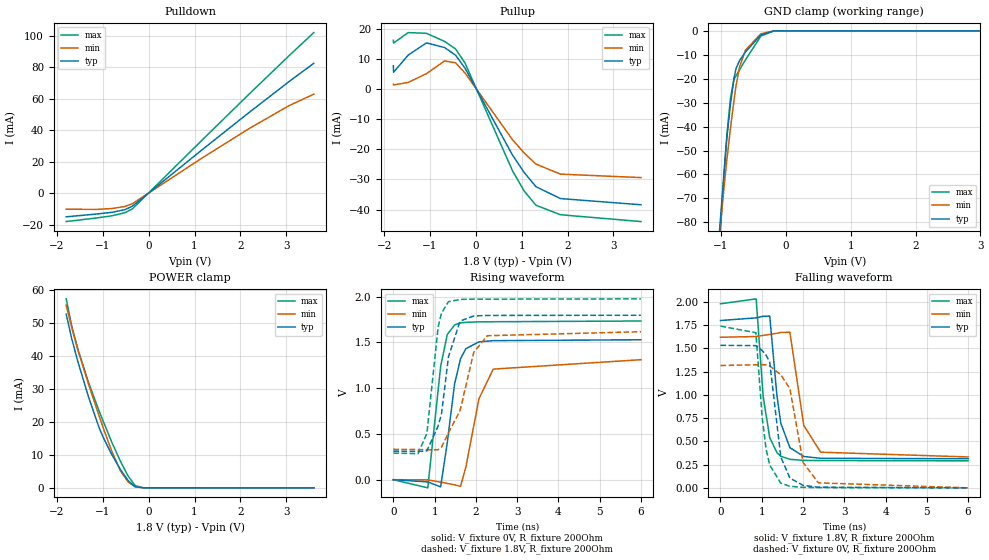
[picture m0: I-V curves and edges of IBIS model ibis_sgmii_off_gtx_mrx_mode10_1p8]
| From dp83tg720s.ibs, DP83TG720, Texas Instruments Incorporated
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|Place the individual model from SIMDE post processing here.
|   ibis_sgmii_off_gtx_mrx_mode10_1p8
[Model]   ibis_sgmii_off_gtx_mrx_mode10_1p8
Model_type   I/O
Polarity   Non-Inverting
Enable   Active-Low
Vinl = 0.54
Vinh = 1.26
Vmeas = 0.9
Vref = 0
Cref = 2pF
Rref = 100000
|   typ   min   max
C_comp   3.8pF   3.76pF   4.1pF
[Voltage Range]   1.8   1.62   1.98
[Temperature Range]   27   150   -40
[Pullup Reference]   1.8   1.62   1.98
[Pulldown Reference]   -0   -0   -0
[Power Clamp Reference]   1.8   1.62   1.98
[GND Clamp Reference]   0   0   0
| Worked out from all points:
|   slope of the pulldown table from 0 to 0.27 V, typ, clamps not added: 42.1 ohm
|   slope of the pullup table from 0 to 0.27 V, typ, clamps not added: 34.5 ohm
|   GND clamp passes 1 mA (typ) near -0.34 V on its own axis
|   POWER clamp passes 1 mA (typ) near -0.37 V on its own axis
|   falling waveform, V_fixture 1.8V, R_fixture 200Ohm: 20-80 % time 226ps typ, 271ps min, 204ps max; typ from 1.8 V to 0.313 V
|   rising waveform, V_fixture 0V, R_fixture 200Ohm: 20-80 % time 281ps typ, 381ps min, 236ps max; typ from 0 V to 1.53 V
|   rising waveform, V_fixture 1.8V, R_fixture 200Ohm: 20-80 % time 283ps typ, 526ps min, 217ps max; typ from 0.313 V to 1.8 V
|   falling waveform, V_fixture 0V, R_fixture 200Ohm: 20-80 % time 251ps typ, 323ps min, 214ps max; typ from 1.53 V to 0 V
[Pulldown]
|   Voltage   I(typ)   I(min)   I(max)
-1.8V     -15.07mA   -10.25mA   -18.09mA
-1.147V   -13.34mA   -10.38mA   -15.84mA
-801mV    -12.23mA   -9.812mA   -14.43mA
-514.8mV  -10.51mA   -8.508mA   -12.42mA
-352.8mV  -8.251mA   -6.687mA   -9.971mA
1.148V    27.12mA    21.97mA    33.18mA
2.191V    51.23mA    40.99mA    62.89mA
3.06V     70.77mA    55.5mA     87.2mA
3.6V      82.43mA    62.79mA    101.9mA
[GND Clamp]
|   Voltage   I(typ)   I(min)   I(max)
-1.8V     -413mA     -361.3mA   -461.4mA
-1.022V   -83.06mA   -84.73mA   -87.93mA
-941.4mV  -54.43mA   -61.85mA   -55.74mA
-909mV    -44.33mA   -53.48mA   -43.2mA
-855mV    -30.54mA   -40.73mA   -28.24mA
-801mV    -19.92mA   -29.1mA    -20.25mA
-768.6mV  -15.71mA   -22.89mA   -18.77mA
-714.6mV  -12.42mA   -15.06mA   -16.29mA
-622.8mV  -8.805mA   -8.036mA   -12.09mA
-385.2mV  -1.682mA   -1.218mA   -2.156mA
-185.4mV  -38.15uA   -31.25uA   -36.48uA
3.6V      0A         0A         0A
[Pullup]
|   Voltage   I(typ)   I(min)   I(max)
-1.8V     7.801mA    1.623mA    16.26mA
-1.795V   5.648mA    1.447mA    15.36mA
-1.476V   11.34mA    2.257mA    18.84mA
-1.076V   15.41mA    5.196mA    18.59mA
-682.2mV  13.86mA    9.417mA    15.91mA
-444.6mV  11.35mA    8.796mA    13.42mA
-239.4mV  7.081mA    5.456mA    8.8mA
797.4mV   -21.84mA   -16.75mA   -27.06mA
1.051V    -27.63mA   -21.17mA   -33.8mA
1.31V     -32.4mA    -24.89mA   -38.57mA
1.845V    -36.36mA   -28.23mA   -41.73mA
3.6V      -38.41mA   -29.38mA   -44mA
[POWER Clamp]
|   Voltage   I(typ)   I(min)   I(max)
-1.8V     52.72mA    55.43mA    57.36mA
-1.681V   45.36mA    48.74mA    49.19mA
-1.546V   38.34mA    41.85mA    42.08mA
-1.319V   27.84mA    31.74mA    32.21mA
-1.082V   18.24mA    21.83mA    23.29mA
-979.2mV  14.91mA    17.7mA     19.75mA
-806.4mV  10.12mA    11.14mA    13.88mA
-612mV    5.438mA    5.014mA    7.891mA
-444.6mV  2.133mA    1.733mA    3.461mA
-293.4mV  326.9uA    317uA      674.2uA
-109.8mV  6.028uA    13.64uA    2.638uA
3.6V      0A         0A         0A
[Ramp]
R_load = 200
|   typ   min   max
dV/dt_r   0.917781/2.79321e-10   0.787416/3.77429e-10   1.04117/2.35852e-10
dV/dt_f   0.891973/2.23452e-10   0.772299/2.67931e-10   1.01309/2.01443e-10
[Falling Waveform]
V_fixture = 1.8V
V_fixture_min = 1.62V
V_fixture_max = 1.98V
R_fixture = 200Ohm
C_fixture = 0F
|   Time   V(typ)   V(min)   V(max)
0s        1.8V       1.62V      1.98V
865.1ps   1.829V     1.628V     2.033V
1.035ns   1.846V     1.64V      981.3mV
1.194ns   1.847V     1.65V      539.7mV
1.368ns   994.6mV    1.663V     379.3mV
1.462ns   695.9mV    1.672V     340.2mV
1.682ns   432.7mV    1.674V     307.1mV
2.019ns   337.1mV    671.1mV    295.7mV
2.428ns   318.2mV    383.7mV    294mV
6ns       313.2mV    332.5mV    291.3mV
[Rising Waveform]
V_fixture = 0V
V_fixture_min = 0V
V_fixture_max = 0V
R_fixture = 200Ohm
C_fixture = 0F
|   Time   V(typ)   V(min)   V(max)
0s        44.44uV    38.89uV    69.25uV
834.6ps   -24.23mV   -1.87mV    -89.05mV
1.146ns   -78.51mV   -26.32mV   1.237V
1.307ns   404mV      -40.44mV   1.587V
1.484ns   1.046V     -56.39mV   1.692V
1.629ns   1.323V     -73.09mV   1.714V
1.757ns   1.432V     137.8mV    1.72V
2.075ns   1.507V     884.7mV    1.726V
2.42ns    1.52V      1.209V     1.727V
6ns       1.53V      1.312V     1.735V
[Rising Waveform]
V_fixture = 1.8V
V_fixture_min = 1.62V
V_fixture_max = 1.98V
R_fixture = 200Ohm
C_fixture = 0F
|   Time   V(typ)   V(min)   V(max)
0s        313.1mV    332.4mV    291.2mV
596.9ps   308.6mV    329.5mV    284.5mV
813.8ps   315.6mV    328.4mV    507.9mV
1.085ns   586.3mV    327.1mV    1.665V
1.166ns   714.4mV    354.1mV    1.821V
1.336ns   1.343V     513mV      1.946V
1.617ns   1.734V     755.3mV    1.971V
1.949ns   1.79V      1.392V     1.974V
2.275ns   1.796V     1.574V     1.974V
6ns       1.798V     1.618V     1.977V
[Falling Waveform]
|Gnd
V_fixture = 0V
V_fixture_min = 0V
V_fixture_max = 0V
R_fixture = 200Ohm
C_fixture = 0F
|   Time   V(typ)   V(min)   V(max)
0s        1.533V     1.316V     1.74V
858.3ps   1.53V      1.324V     1.669V
1.011ns   1.476V     1.325V     757.6mV
1.104ns   1.429V     1.325V     419.4mV
1.194ns   1.352V     1.311V     244.5mV
1.462ns   331.7mV    1.216V     50.62mV
1.682ns   105.6mV    1.068V     17.18mV
2.003ns   26.42mV    272.7mV    5.574mV
2.371ns   7.221mV    53.98mV    3.225mV
6ns       182.1uV    185.6uV    179.8uV
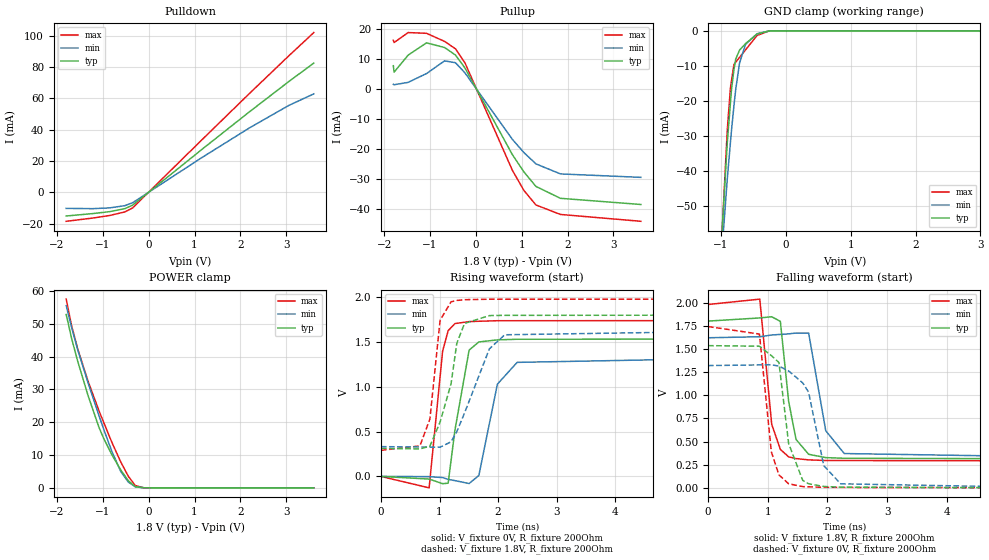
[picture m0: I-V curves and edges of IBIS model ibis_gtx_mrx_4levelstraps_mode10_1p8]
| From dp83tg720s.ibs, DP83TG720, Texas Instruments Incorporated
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|   ibis_gtx_mrx_4levelstraps_mode10_1p8
[Model]   ibis_gtx_mrx_4levelstraps_mode10_1p8
Model_type   I/O
Polarity   Non-Inverting
Enable   Active-Low
Vinl = 0.54
Vinh = 1.26
Vmeas = 0.9
Vref = 0
Cref = 2pF
Rref = 100000
|   typ   min   max
C_comp   2.51pF   2.4pF   2.6pF
[Voltage Range]   1.8   1.62   1.98
[Temperature Range]   27   150   -40
[Pullup Reference]   1.8   1.62   1.98
[Pulldown Reference]   0   0   0
[Power Clamp Reference]   1.8   1.62   1.98
[GND Clamp Reference]   0   0   0
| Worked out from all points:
|   slope of the pulldown table from 0 to 0.27 V, typ, clamps not added: 42.1 ohm
|   slope of the pullup table from 0 to 0.27 V, typ, clamps not added: 34.5 ohm
|   GND clamp passes 1 mA (typ) near -0.45 V on its own axis
|   POWER clamp passes 1 mA (typ) near -0.36 V on its own axis
|   falling waveform, V_fixture 1.8V, R_fixture 200Ohm: 20-80 % time 161ps typ, 197ps min, 154ps max; typ from 1.8 V to 0.313 V
|   rising waveform, V_fixture 0V, R_fixture 200Ohm: 20-80 % time 176ps typ, 255ps min, 141ps max; typ from 0 V to 1.53 V
|   rising waveform, V_fixture 1.8V, R_fixture 200Ohm: 20-80 % time 288ps typ, 460ps min, 151ps max; typ from 0.313 V to 1.8 V
|   falling waveform, V_fixture 0V, R_fixture 200Ohm: 20-80 % time 184ps typ, 254ps min, 161ps max; typ from 1.53 V to 0 V
[Pulldown]
|   Voltage   I(typ)   I(min)   I(max)
-1.8V     -15.11mA   -10.25mA   -18.49mA
-1.222V   -13.57mA   -10.43mA   -16.42mA
-855mV    -12.34mA   -9.942mA   -14.81mA
-520.2mV  -10.44mA   -8.509mA   -12.5mA
-352.8mV  -8.213mA   -6.658mA   -9.977mA
1.165V    27.5mA     22.27mA    33.64mA
2.191V    51.23mA    40.99mA    62.89mA
3.06V     70.77mA    55.5mA     87.2mA
3.6V      82.43mA    62.79mA    101.9mA
[GND Clamp]
|   Voltage   I(typ)   I(min)   I(max)
-1.8V     -379.6mA   -329.3mA   -423.1mA
-1.017V   -67.63mA   -70.66mA   -69.46mA
-903.6mV  -31.87mA   -42.25mA   -28.2mA
-855mV    -20.54mA   -31.86mA   -16.22mA
-838.8mV  -16.76mA   -28.4mA    -14.23mA
-801mV    -11.03mA   -21.37mA   -9.591mA
-774mV    -8.085mA   -16.75mA   -8.964mA
-714.6mV  -5.501mA   -9.181mA   -7.586mA
-622.8mV  -3.665mA   -3.879mA   -5.456mA
-444.6mV  -924.3uA   -826.8uA   -1.321mA
-255.6mV  -12.26uA   -28.29uA   -12.59uA
3.6V      0A         0A         0A
[Pullup]
|   Voltage   I(typ)   I(min)   I(max)
-1.8V     7.801mA    1.623mA    16.26mA
-1.784V   5.659mA    1.465mA    15.52mA
-1.476V   11.34mA    2.257mA    18.84mA
-1.076V   15.41mA    5.196mA    18.59mA
-682.2mV  13.86mA    9.417mA    15.9mA
-444.6mV  11.35mA    8.796mA    13.42mA
-239.4mV  7.081mA    5.456mA    8.8mA
797.4mV   -21.84mA   -16.75mA   -27.06mA
1.051V    -27.63mA   -21.17mA   -33.8mA
1.31V     -32.4mA    -24.89mA   -38.57mA
1.845V    -36.36mA   -28.23mA   -41.73mA
3.6V      -38.41mA   -29.38mA   -44.01mA
[POWER Clamp]
|   Voltage   I(typ)   I(min)   I(max)
-1.8V     52.83mA    55.52mA    57.51mA
-1.681V   45.46mA    48.83mA    49.33mA
-1.546V   38.43mA    41.93mA    42.21mA
-1.319V   27.92mA    31.81mA    32.31mA
-1.082V   18.31mA    21.88mA    23.38mA
-979.2mV  14.97mA    17.75mA    19.83mA
-806.4mV  10.17mA    11.18mA    13.94mA
-612mV    5.477mA    5.044mA    7.945mA
-444.6mV  2.163mA    1.755mA    3.504mA
-293.4mV  350.1uA    334.1uA    708uA
-109.8mV  25.24uA    27.21uA    30.53uA
3.6V      0A         0A         0A
[Ramp]
R_load = 200
|   typ   min   max
dV/dt_r   0.919818/1.76122e-10   0.790484/2.52767e-10   1.04328/1.40855e-10
dV/dt_f   0.891938/1.59769e-10   0.772285/1.94589e-10   1.01304/1.51539e-10
[Falling Waveform]
V_fixture = 1.8V
V_fixture_min = 1.62V
V_fixture_max = 1.98V
R_fixture = 200Ohm
C_fixture = 0F
|   Time   V(typ)   V(min)   V(max)
0s        1.8V       1.62V      1.979V
866.5ps   1.834V     1.631V     2.037V
1.066ns   1.847V     1.65V      686.5mV
1.211ns   1.797V     1.656V     415.5mV
1.35ns    932.9mV    1.662V     334.5mV
1.474ns   522.4mV    1.671V     315.9mV
1.685ns   362.6mV    1.671V     302.1mV
1.972ns   326.3mV    616.3mV    295.4mV
2.282ns   319.4mV    370.4mV    295.1mV
6ns       313mV      332.4mV    291mV
[Rising Waveform]
V_fixture = 0V
V_fixture_min = 0V
V_fixture_max = 0V
R_fixture = 200Ohm
C_fixture = 0F
|   Time   V(typ)   V(min)   V(max)
0s        92.9uV     209.8uV    55.31uV
823ps     -29.62mV   -2.618mV   -127.8mV
1.053ns   -81.1mV    -13.01mV   1.397V
1.148ns   -75.68mV   -33.13mV   1.627V
1.263ns   514.4mV    -46.94mV   1.706V
1.506ns   1.41V      -79.53mV   1.728V
1.672ns   1.501V     10.55mV    1.732V
1.989ns   1.524V     1.03V      1.738V
2.326ns   1.531V     1.273V     1.738V
6ns       1.533V     1.318V     1.739V
[Rising Waveform]
V_fixture = 1.8V
V_fixture_min = 1.62V
V_fixture_max = 1.98V
R_fixture = 200Ohm
C_fixture = 0F
|   Time   V(typ)   V(min)   V(max)
0s        313mV      332.4mV    291mV
665.3ps   306.6mV    328.3mV    341mV
836.2ps   337.7mV    327.3mV    641.3mV
1.01ns    606.7mV    326.2mV    1.742V
1.197ns   1.033V     386.1mV    1.949V
1.296ns   1.487V     500.2mV    1.964V
1.428ns   1.708V     707.8mV    1.973V
1.851ns   1.795V     1.423V     1.978V
2.114ns   1.798V     1.581V     1.978V
6ns       1.8V       1.62V      1.979V
[Falling Waveform]
|Gnd
V_fixture = 0V
V_fixture_min = 0V
V_fixture_max = 0V
R_fixture = 200Ohm
C_fixture = 0F
|   Time   V(typ)   V(min)   V(max)
0s        1.535V     1.32V      1.741V
860.6ps   1.529V     1.327V     1.66V
1.06ns    1.428V     1.329V     389.4mV
1.187ns   1.353V     1.314V     140.3mV
1.35ns    478.4mV    1.262V     43.65mV
1.586ns   80.76mV    1.133V     13.6mV
1.684ns   44.33mV    1.033V     11.38mV
1.939ns   14.94mV    239.6mV    5.603mV
2.222ns   7.432mV    43.74mV    4.695mV
6ns       91.91uV    209.8uV    54.4uV
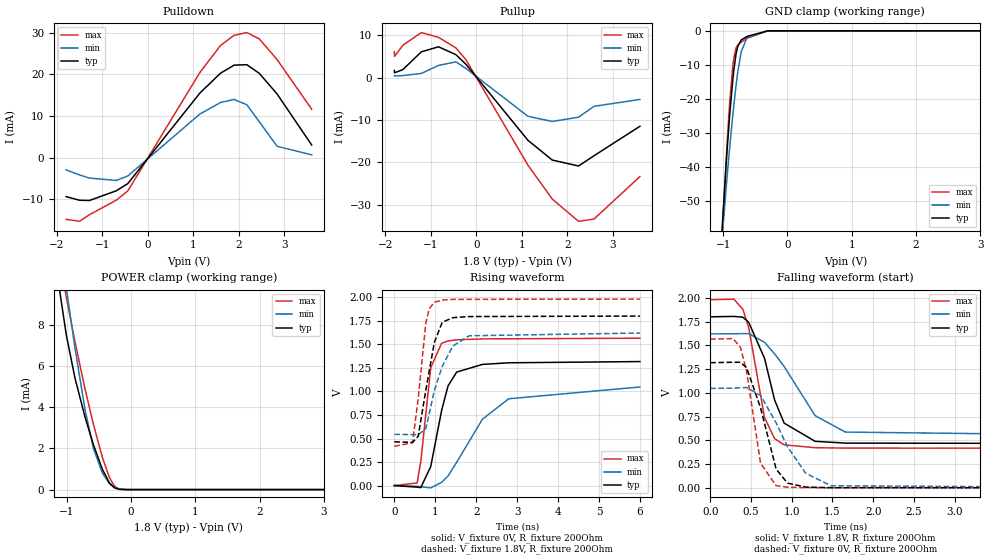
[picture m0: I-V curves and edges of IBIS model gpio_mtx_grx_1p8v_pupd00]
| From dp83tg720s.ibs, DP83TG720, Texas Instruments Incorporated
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|   gpio_mtx_grx_1p8v_pupd00
[Model]   gpio_mtx_grx_1p8v_pupd00
Model_type   I/O
Polarity   Non-Inverting
Enable   Active-Low
Vinl = 0.54
Vinh = 1.26
Vmeas = 0.9
Vref = 0
Cref = 2pF
Rref = 100000
|   typ   min   max
C_comp   1.46pF   1.44pF   1.48pF
[Voltage Range]   1.8   1.62   1.98
[Temperature Range]   27   150   -40
[Pullup Reference]   1.8   1.62   1.98
[Pulldown Reference]   0   0   0
[Power Clamp Reference]   1.8   1.62   1.98
[GND Clamp Reference]   0   0   0
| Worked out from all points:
|   slope of the pulldown table from 0 to 0.27 V, typ, clamps not added: 68.8 ohm
|   slope of the pullup table from 0 to 0.27 V, typ, clamps not added: 71.1 ohm
|   GND clamp passes 1 mA (typ) near -0.54 V on its own axis
|   POWER clamp passes 1 mA (typ) near -0.45 V on its own axis
|   falling waveform, V_fixture 1.8V, R_fixture 200Ohm: 20-80 % time 266ps typ, 493ps min, 194ps max; typ from 1.8 V to 0.465 V
|   rising waveform, V_fixture 0V, R_fixture 200Ohm: 20-80 % time 389ps typ, 983ps min, 229ps max; typ from 0 V to 1.32 V
|   rising waveform, V_fixture 1.8V, R_fixture 200Ohm: 20-80 % time 322ps typ, 467ps min, 220ps max; typ from 0.465 V to 1.8 V
|   falling waveform, V_fixture 0V, R_fixture 200Ohm: 20-80 % time 224ps typ, 394ps min, 162ps max; typ from 1.32 V to 0 V
[Pulldown]
|   Voltage   I(typ)   I(min)   I(max)
-1.8V     -9.373mA   -2.955mA   -14.83mA
-1.503V   -10.24mA   -4.167mA   -15.29mA
-1.287V   -10.3mA    -4.916mA   -13.7mA
-698.4mV  -7.972mA   -5.494mA   -10.23mA
-444.6mV  -6.254mA   -4.425mA   -8.011mA
1.143V    15.5mA     10.46mA    20.44mA
1.597V    20.26mA    13.22mA    26.92mA
1.894V    22.18mA    13.95mA    29.34mA
2.174V    22.29mA    12.67mA    30mA
2.45V     20.2mA     8.58mA     28.46mA
2.839V    15.27mA    2.714mA    23.52mA
3.6V      3.022mA    656uA      11.6mA
[GND Clamp]
|   Voltage   I(typ)   I(min)   I(max)
-1.8V     -346.2mA   -302.9mA   -380.3mA
-1.012V   -56.65mA   -60.01mA   -58.31mA
-941.4mV  -35.72mA   -43.38mA   -33.87mA
-898.2mV  -24.6mA    -34.15mA   -20.97mA
-849.6mV  -14.24mA   -24.66mA   -10.21mA
-833.4mV  -11.4mA    -21.73mA   -7.856mA
-801mV    -6.941mA   -16.28mA   -5.124mA
-774mV    -4.614mA   -12.27mA   -4.191mA
-720mV    -2.708mA   -6.198mA   -3.314mA
-628.2mV  -1.639mA   -1.93mA    -2.196mA
-309.6mV  -16.4uA    -21.72uA   -26.01uA
3.6V      0A         0A         0A
[Pullup]
|   Voltage   I(typ)   I(min)   I(max)
-1.8V     1.744mA    480.7uA    6.165mA
-1.795V   1.177mA    422.4uA    5.078mA
-1.611V   1.951mA    521.8uA    7.703mA
-1.206V   6.14mA     1.032mA    10.69mA
-828mV    7.327mA    2.927mA    9.562mA
-444.6mV  5.46mA     3.758mA    7.052mA
-223.2mV  3.171mA    2.189mA    4.237mA
1.138V    -14.78mA   -9.105mA   -20.65mA
1.672V    -19.44mA   -10.32mA   -28.66mA
2.25V     -20.85mA   -9.32mA    -33.92mA
2.59V     -18.43mA   -6.745mA   -33.39mA
3.6V      -11.46mA   -5.119mA   -23.35mA
[POWER Clamp]
|   Voltage   I(typ)   I(min)   I(max)
-1.8V     52.81mA    31.92mA    32.51mA
-1.13V    10.09mA    12.58mA    11.5mA
-1.006V   7.504mA    9.779mA    9.342mA
-871.2mV  5.41mA     6.878mA    7.176mA
-714.6mV  3.521mA    3.876mA    4.882mA
-585mV    2.184mA    2.004mA    3.173mA
-444.6mV  982.3uA    801.8uA    1.557mA
-336.6mV  328.7uA    288.4uA    594.4uA
-255.6mV  81.4uA     92.37uA    159.3uA
-180mV    13.18uA    22.88uA    22.76uA
-66.6mV   360nA      1.566uA    374.7nA
3.6V      0A         0A         0A
[Ramp]
R_load = 200
|   typ   min   max
dV/dt_r   0.789805/3.87903e-10   0.628237/9.78082e-10   0.938914/2.28306e-10
dV/dt_f   0.800806/2.63607e-10   0.645754/4.91884e-10   0.937756/1.9384e-10
[Falling Waveform]
V_fixture = 1.8V
V_fixture_min = 1.62V
V_fixture_max = 1.98V
R_fixture = 200Ohm
C_fixture = 0F
|   Time   V(typ)   V(min)   V(max)
0s        1.8V       1.62V      1.98V
288.8ps   1.804V     1.622V     1.986V
399.5ps   1.796V     1.623V     1.88V
471.8ps   1.742V     1.623V     1.686V
666ps     1.364V     1.532V     740.1mV
790.1ps   924.2mV    1.41V      517.9mV
907ps     681.3mV    1.277V     453.1mV
1.287ns   490mV      760.1mV    422.7mV
1.659ns   471.1mV    587.2mV    418.6mV
6ns       465.2mV    543.4mV    417mV
[Rising Waveform]
V_fixture = 0V
V_fixture_min = 0V
V_fixture_max = 0V
R_fixture = 200Ohm
C_fixture = 0F
|   Time   V(typ)   V(min)   V(max)
0s        267.1uV    157.4uV    423uV
556.9ps   -16.34mV   -7.615mV   27.92mV
646.4ps   -21.28mV   -12.52mV   256.5mV
889.3ps   202.7mV    -23.97mV   1.252V
1.155ns   797.4mV    34.87mV    1.511V
1.312ns   1.059V     101.9mV    1.536V
1.522ns   1.205V     247.3mV    1.548V
2.153ns   1.287V     705.5mV    1.558V
2.795ns   1.304V     922.1mV    1.559V
6ns       1.317V     1.047V     1.565V
[Rising Waveform]
V_fixture = 1.8V
V_fixture_min = 1.62V
V_fixture_max = 1.98V
R_fixture = 200Ohm
C_fixture = 0F
|   Time   V(typ)   V(min)   V(max)
0s        465.2mV    543.4mV    417mV
445.8ps   458.9mV    542.1mV    455.8mV
582.9ps   523.9mV    537.3mV    925.5mV
769.4ps   1.014V     606.6mV    1.727V
851.4ps   1.212V     760.9mV    1.876V
976.4ps   1.519V     1.008V     1.946V
1.17ns    1.734V     1.266V     1.971V
1.428ns   1.783V     1.481V     1.977V
1.829ns   1.795V     1.591V     1.978V
6ns       1.8V       1.62V      1.98V
[Falling Waveform]
|Gnd
V_fixture = 0V
V_fixture_min = 0V
V_fixture_max = 0V
R_fixture = 200Ohm
C_fixture = 0F
|   Time   V(typ)   V(min)   V(max)
0s        1.317V     1.047V     1.565V
279.9ps   1.322V     1.049V     1.571V
369.8ps   1.321V     1.053V     1.48V
445.8ps   1.265V     1.056V     1.227V
617.5ps   841.8mV    973mV      257.9mV
808.4ps   198.1mV    684.3mV    23.38mV
948.6ps   50.01mV    432.6mV    6.809mV
1.171ns   8.353mV    154.3mV    3.273mV
1.482ns   1.941mV    22.36mV    1.599mV
6ns       267.3uV    157.4uV    423.4uV
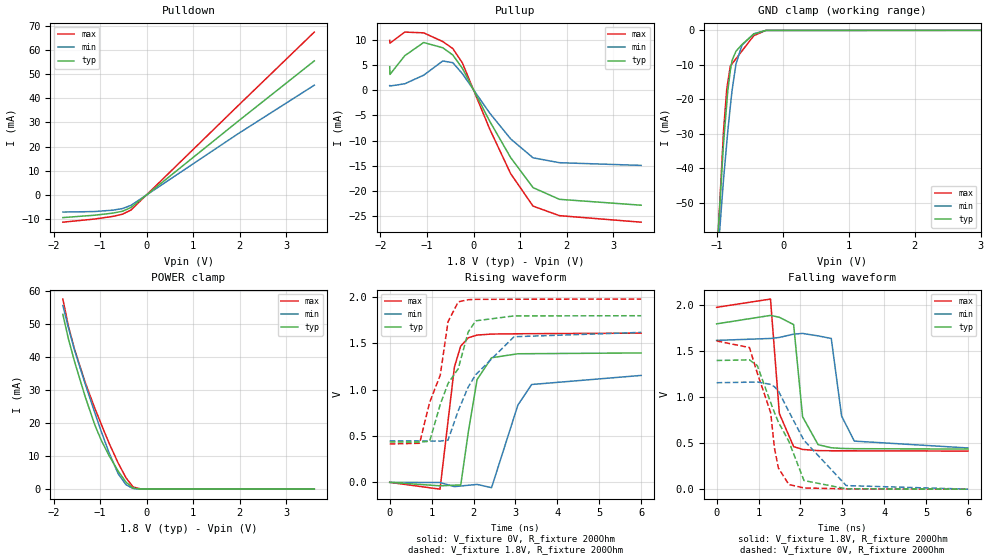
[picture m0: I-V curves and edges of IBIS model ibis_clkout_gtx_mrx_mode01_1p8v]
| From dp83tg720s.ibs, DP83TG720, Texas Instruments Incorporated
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|   ibis_clkout_gtx_mrx_mode01_1p8v
[Model]   ibis_clkout_gtx_mrx_mode01_1p8v
Model_type   I/O
Polarity   Non-Inverting
Enable   Active-Low
Vinl = 0.54
Vinh = 1.26
Vmeas = 0.9
Vref = 0
Cref = 2pF
Rref = 100000
|   typ   min   max
C_comp   3pF   2.97pF   3.04pF
[Voltage Range]   1.8   1.62   1.98
[Temperature Range]   27   150   -40
[Pullup Reference]   1.8   1.62   1.98
[Pulldown Reference]   0   0   0
[Power Clamp Reference]   1.8   1.62   1.98
[GND Clamp Reference]   0   0   0
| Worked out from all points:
|   slope of the pulldown table from 0 to 0.27 V, typ, clamps not added: 64 ohm
|   slope of the pullup table from 0 to 0.27 V, typ, clamps not added: 56 ohm
|   GND clamp passes 1 mA (typ) near -0.44 V on its own axis
|   POWER clamp passes 1 mA (typ) near -0.37 V on its own axis
|   falling waveform, V_fixture 1.8V, R_fixture 200Ohm: 20-80 % time 210ps typ, 247ps min, 182ps max; typ from 1.8 V to 0.437 V
|   rising waveform, V_fixture 0V, R_fixture 200Ohm: 20-80 % time 288ps typ, 439ps min, 244ps max; typ from 0 V to 1.4 V
|   rising waveform, V_fixture 1.8V, R_fixture 200Ohm: 20-80 % time 685ps typ, 1ns min, 487ps max; typ from 0.437 V to 1.8 V
|   falling waveform, V_fixture 0V, R_fixture 200Ohm: 20-80 % time 741ps typ, 1.08ns min, 471ps max; typ from 1.4 V to 0 V
[Pulldown]
|   Voltage   I(typ)   I(min)   I(max)
-1.8V     -9.335mA   -7.039mA   -11.23mA
-1.125V   -8.357mA   -6.843mA   -9.933mA
-730.8mV  -7.492mA   -6.267mA   -8.857mA
-520.2mV  -6.702mA   -5.599mA   -7.923mA
-336.6mV  -5.159mA   -4.278mA   -6.208mA
1.958V    30.4mA     25.25mA    36.82mA
3.6V      55.42mA    45.38mA    67.32mA
[GND Clamp]
|   Voltage   I(typ)   I(min)   I(max)
-1.8V     -382.3mA   -332mA     -425.2mA
-1.017V   -68.67mA   -71.81mA   -70.53mA
-903.6mV  -32.69mA   -43.18mA   -29.12mA
-855mV    -21.28mA   -32.69mA   -17.07mA
-838.8mV  -17.47mA   -29.2mA    -15.06mA
-801mV    -11.68mA   -22.1mA    -10.37mA
-774mV    -8.705mA   -17.42mA   -9.699mA
-714.6mV  -6.046mA   -9.737mA   -8.229mA
-622.8mV  -4.089mA   -4.277mA   -5.956mA
-444.6mV  -1.097mA   -992.9uA   -1.545mA
-261mV    -16.1uA    -40.15uA   -15.49uA
3.6V      0A         0A         0A
[Pullup]
|   Voltage   I(typ)   I(min)   I(max)
-1.8V     4.689mA    939.1uA    9.925mA
-1.795V   3.153mA    845.1uA    9.384mA
-1.476V   6.89mA     1.297mA    11.58mA
-1.071V   9.509mA    3.003mA    11.43mA
-660.6mV  8.461mA    5.831mA    9.698mA
-444.6mV  7.017mA    5.487mA    8.294mA
-239.4mV  4.366mA    3.3mA      5.438mA
343.8mV   -6.101mA   -4.498mA   -7.647mA
797.4mV   -13.4mA    -9.678mA   -16.6mA
1.278V    -19.37mA   -13.44mA   -23.05mA
1.845V    -21.7mA    -14.41mA   -24.95mA
3.6V      -22.87mA   -14.95mA   -26.25mA
[POWER Clamp]
|   Voltage   I(typ)   I(min)   I(max)
-1.8V     53.01mA    55.69mA    57.65mA
-1.681V   45.61mA    48.97mA    49.43mA
-1.546V   38.55mA    42.04mA    42.27mA
-1.319V   27.98mA    31.85mA    32.33mA
-1.114V   19.49mA    23.18mA    24.54mA
-979.2mV  14.96mA    17.66mA    19.84mA
-811.8mV  10.29mA    11.19mA    14.09mA
-612mV    5.452mA    4.68mA     7.912mA
-444.6mV  2.137mA    1.369mA    3.468mA
-293.4mV  327.2uA    184.8uA    675uA
-109.8mV  6.037uA    6.332uA    2.646uA
3.6V      0A         0A         0A
[Ramp]
R_load = 200
|   typ   min   max
dV/dt_r   0.838848/2.87315e-10   0.692873/4.38235e-10   0.966919/2.4247e-10
dV/dt_f   0.817974/2.09252e-10   0.702789/2.45239e-10   0.939142/1.7948e-10
[Falling Waveform]
V_fixture = 1.8V
V_fixture_min = 1.62V
V_fixture_max = 1.98V
R_fixture = 200Ohm
C_fixture = 0F
|   Time   V(typ)   V(min)   V(max)
0s        1.8V       1.62V      1.98V
1.286ns   1.892V     1.641V     2.07V
1.497ns   1.872V     1.652V     823.1mV
1.838ns   1.792V     1.688V     463.4mV
2.052ns   788.5mV    1.696V     432.7mV
2.422ns   484.2mV    1.669V     419.9mV
2.736ns   451.1mV    1.641V     418mV
2.983ns   443.5mV    796mV      417.8mV
3.286ns   440.8mV    523.3mV    417.5mV
6ns       436.7mV    448.6mV    414.8mV
[Rising Waveform]
V_fixture = 0V
V_fixture_min = 0V
V_fixture_max = 0V
R_fixture = 200Ohm
C_fixture = 0F
|   Time   V(typ)   V(min)   V(max)
0s        2.503uV    19.89uV    777.6nV
1.2ns     -37.68mV   -1.647mV   -73.76mV
1.544ns   -30.53mV   -46.12mV   1.247V
1.694ns   -29.97mV   -39.57mV   1.472V
1.877ns   548.3mV    -31.56mV   1.562V
2.085ns   1.111V     -22.49mV   1.591V
2.43ns    1.346V     -57.61mV   1.602V
3.058ns   1.389V     834.7mV    1.605V
3.386ns   1.39V      1.057V     1.606V
6ns       1.398V     1.155V     1.612V
[Rising Waveform]
V_fixture = 1.8V
V_fixture_min = 1.62V
V_fixture_max = 1.98V
R_fixture = 200Ohm
C_fixture = 0F
|   Time   V(typ)   V(min)   V(max)
0s        436.7mV    448.6mV    414.8mV
713.2ps   434.4mV    446.9mV    422.2mV
953.1ps   444.1mV    446.4mV    864.5mV
1.206ns   842.3mV    445.8mV    1.159V
1.391ns   1.068V     456.6mV    1.735V
1.635ns   1.228V     773.8mV    1.95V
1.872ns   1.623V     1.029V     1.973V
2.052ns   1.745V     1.163V     1.977V
2.966ns   1.798V     1.573V     1.978V
6ns       1.8V       1.62V      1.98V
[Falling Waveform]
|Gnd
V_fixture = 0V
V_fixture_min = 0V
V_fixture_max = 0V
R_fixture = 200Ohm
C_fixture = 0F
|   Time   V(typ)   V(min)   V(max)
0s        1.401V     1.159V     1.614V
783.7ps   1.408V     1.165V     1.542V
971.8ps   1.345V     1.167V     1.263V
1.289ns   944.9mV    1.141V     835.5mV
1.381ns   832.9mV    1.115V     446.7mV
1.475ns   730.2mV    1.068V     229.7mV
1.724ns   520.1mV    845.6mV    50.6mV
2.085ns   93.85mV    531.6mV    13.06mV
3.093ns   3.86mV     39.02mV    2.941mV
6ns       2.705uV    19.82uV    1.105uV
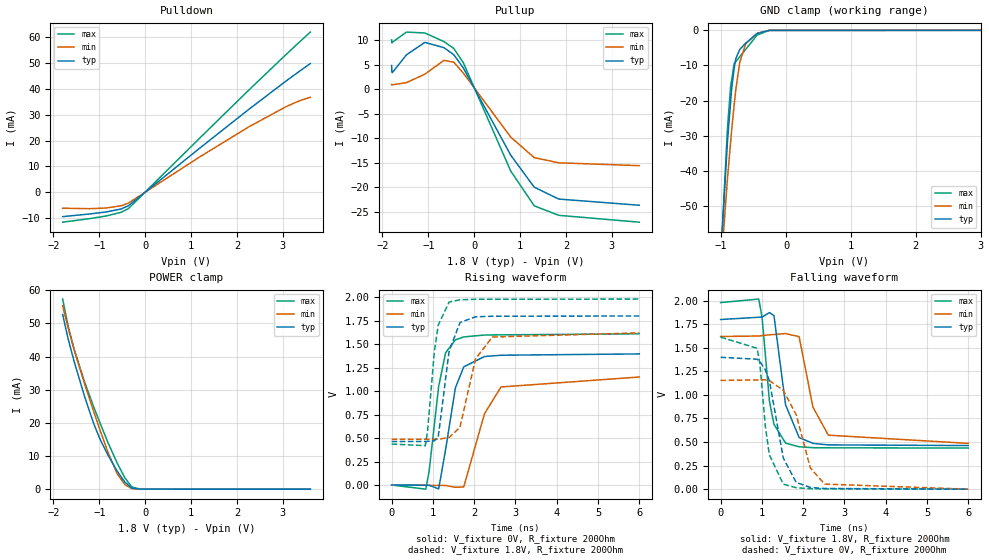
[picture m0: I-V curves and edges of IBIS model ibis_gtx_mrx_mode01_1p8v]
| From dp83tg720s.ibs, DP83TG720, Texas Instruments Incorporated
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| ibis_gtx_mrx_mode01_1p8v
[Model]   ibis_gtx_mrx_mode01_1p8v
Model_type   I/O
Polarity   Non-Inverting
Enable   Active-Low
Vinl = 0.54
Vinh = 1.26
Vmeas = 0.9
Vref = 0.9
Cref = 2pF
Rref = 100000
|   typ   min   max
C_comp   2.91pF   2.88pF   2.94pF
[Voltage Range]   1.8   1.62   1.98
[Temperature Range]   27   150   -40
[Pullup Reference]   1.8   1.62   1.98
[Pulldown Reference]   0   0   0
[Power Clamp Reference]   1.8   1.62   1.98
[GND Clamp Reference]   0   0   0
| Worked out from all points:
|   slope of the pulldown table from 0 to 0.27 V, typ, clamps not added: 69.1 ohm
|   slope of the pullup table from 0 to 0.27 V, typ, clamps not added: 55.9 ohm
|   GND clamp passes 1 mA (typ) near -0.45 V on its own axis
|   POWER clamp passes 1 mA (typ) near -0.37 V on its own axis
|   falling waveform, V_fixture 1.8V, R_fixture 200Ohm: 20-80 % time 268ps typ, 348ps min, 222ps max; typ from 1.8 V to 0.463 V
|   rising waveform, V_fixture 0V, R_fixture 200Ohm: 20-80 % time 320ps typ, 489ps min, 276ps max; typ from 0 V to 1.4 V
|   rising waveform, V_fixture 1.8V, R_fixture 200Ohm: 20-80 % time 251ps typ, 365ps min, 209ps max; typ from 0.463 V to 1.8 V
|   falling waveform, V_fixture 0V, R_fixture 200Ohm: 20-80 % time 342ps typ, 472ps min, 240ps max; typ from 1.4 V to 0 V
[Pulldown]
|   Voltage   I(typ)   I(min)   I(max)
-1.8V     -9.394mA   -6.144mA   -11.54mA
-1.211V   -8.365mA   -6.324mA   -10.16mA
-855mV    -7.603mA   -6.065mA   -9.157mA
-520.2mV  -6.406mA   -5.184mA   -7.692mA
-363.6mV  -5.143mA   -4.14mA    -6.255mA
1.165V    16.73mA    13.42mA    20.53mA
2.261V    32.07mA    25.31mA    39.52mA
3.076V    43.05mA    33.12mA    53.31mA
3.368V    46.82mA    35.39mA    58.12mA
3.6V      49.74mA    36.73mA    61.88mA
[GND Clamp]
|   Voltage   I(typ)   I(min)   I(max)
-1.8V     -380.2mA   -330.5mA   -422.8mA
-1.017V   -67.69mA   -70.97mA   -69.38mA
-903.6mV  -31.87mA   -42.44mA   -28.15mA
-855mV    -20.52mA   -32.01mA   -16.18mA
-838.8mV  -16.74mA   -28.53mA   -14.19mA
-801mV    -11mA      -21.47mA   -9.556mA
-774mV    -8.056mA   -16.83mA   -8.932mA
-714.6mV  -5.478mA   -9.212mA   -7.557mA
-622.8mV  -3.648mA   -3.867mA   -5.433mA
-444.6mV  -916.7uA   -819.7uA   -1.31mA
-261mV    -11.9uA    -29.84uA   -11.43uA
3.6V      0A         0A         0A
[Pullup]
|   Voltage   I(typ)   I(min)   I(max)
-1.8V     4.808mA    957.6uA    10.03mA
-1.795V   3.542mA    861.1uA    9.417mA
-1.784V   3.36mA     871.7uA    9.556mA
-1.476V   6.992mA    1.327mA    11.62mA
-1.076V   9.516mA    3.034mA    11.44mA
-660.6mV  8.453mA    5.857mA    9.69mA
-444.6mV  7.008mA    5.495mA    8.283mA
-239.4mV  4.362mA    3.307mA    5.431mA
797.4mV   -13.47mA   -9.792mA   -16.7mA
1.31V     -19.99mA   -13.97mA   -23.79mA
1.845V    -22.41mA   -15.02mA   -25.72mA
3.6V      -23.67mA   -15.6mA    -27.12mA
[POWER Clamp]
|   Voltage   I(typ)   I(min)   I(max)
-1.8V     52.72mA    55.38mA    57.36mA
-1.681V   45.36mA    48.69mA    49.19mA
-1.546V   38.34mA    41.79mA    42.08mA
-1.319V   27.84mA    31.66mA    32.21mA
-1.114V   19.41mA    23.05mA    24.46mA
-979.2mV  14.91mA    17.57mA    19.78mA
-811.8mV  10.26mA    11.13mA    14.04mA
-612mV    5.438mA    4.663mA    7.891mA
-444.6mV  2.133mA    1.367mA    3.461mA
-293.4mV  326.9uA    184.7uA    674.2uA
-109.8mV  6.036uA    6.315uA    2.646uA
3.6V      0A         0A         0A
[Ramp]
R_load = 200
|   typ   min   max
dV/dt_r   0.837405/3.16973e-10   0.690224/4.8684e-10   0.965873/2.74882e-10
dV/dt_f   0.802303/2.64697e-10   0.680375/3.45056e-10   0.926321/2.21636e-10
[Falling Waveform]
V_fixture = 1.8V
V_fixture_min = 1.62V
V_fixture_max = 1.98V
R_fixture = 200Ohm
C_fixture = 0F
|   Time   V(typ)   V(min)   V(max)
0s        1.8V       1.62V      1.98V
924.6ps   1.824V     1.625V     2.017V
1.005ns   1.826V     1.629V     1.824V
1.184ns   1.874V     1.638V     932.9mV
1.293ns   1.841V     1.641V     689mV
1.575ns   894.4mV    1.651V     488.3mV
1.903ns   548.3mV    1.618V     449.6mV
2.238ns   485.7mV    870.3mV    440mV
2.61ns    469.8mV    573mV      438.8mV
6ns       462.7mV    485.8mV    436.1mV
[Rising Waveform]
V_fixture = 0V
V_fixture_min = 0V
V_fixture_max = 0V
R_fixture = 200Ohm
C_fixture = 0F
|   Time   V(typ)   V(min)   V(max)
0s        2.874uV    15.9uV     1.096uV
828.6ps   -2.215mV   -3.227mV   -44.24mV
907.1ps   -2.425mV   -3.534mV   141.8mV
1.14ns    -41.2mV    -4.445mV   1.051V
1.309ns   380.7mV    -5.107mV   1.409V
1.544ns   1.032V     -24.12mV   1.546V
1.747ns   1.258V     -20.99mV   1.577V
2.249ns   1.368V     757.7mV    1.597V
2.65ns    1.382V     1.044V     1.599V
6ns       1.396V     1.15V      1.61V
[Rising Waveform]
V_fixture = 1.8V
V_fixture_min = 1.62V
V_fixture_max = 1.98V
R_fixture = 200Ohm
C_fixture = 0F
|   Time   V(typ)   V(min)   V(max)
0s        462.7mV    485.8mV    436.1mV
817.5ps   463.4mV    486.8mV    418.9mV
871ps     465.7mV    486.9mV    575.4mV
1.036ns   471.1mV    487.1mV    1.422V
1.129ns   509.8mV    487.2mV    1.703V
1.392ns   1.422V     506.6mV    1.948V
1.656ns   1.73V      614mV      1.972V
2.032ns   1.791V     1.343V     1.978V
2.44ns    1.797V     1.576V     1.978V
6ns       1.8V       1.62V      1.98V
[Falling Waveform]
|Gnd
V_fixture = 0V
V_fixture_min = 0V
V_fixture_max = 0V
R_fixture = 200Ohm
C_fixture = 0F
|   Time   V(typ)   V(min)   V(max)
0s        1.399V     1.154V     1.613V
883.7ps   1.379V     1.159V     1.495V
951.1ps   1.355V     1.159V     1.336V
1.086ns   1.265V     1.16V      660.2mV
1.181ns   1.153V     1.152V     365.4mV
1.519ns   331.2mV    1.049V     53.14mV
1.832ns   71.03mV    789.6mV    15.53mV
2.175ns   18.25mV    224.4mV    4.329mV
2.522ns   7.403mV    53.83mV    3.202mV
6ns       2.542uV    15.89uV    1.068uV
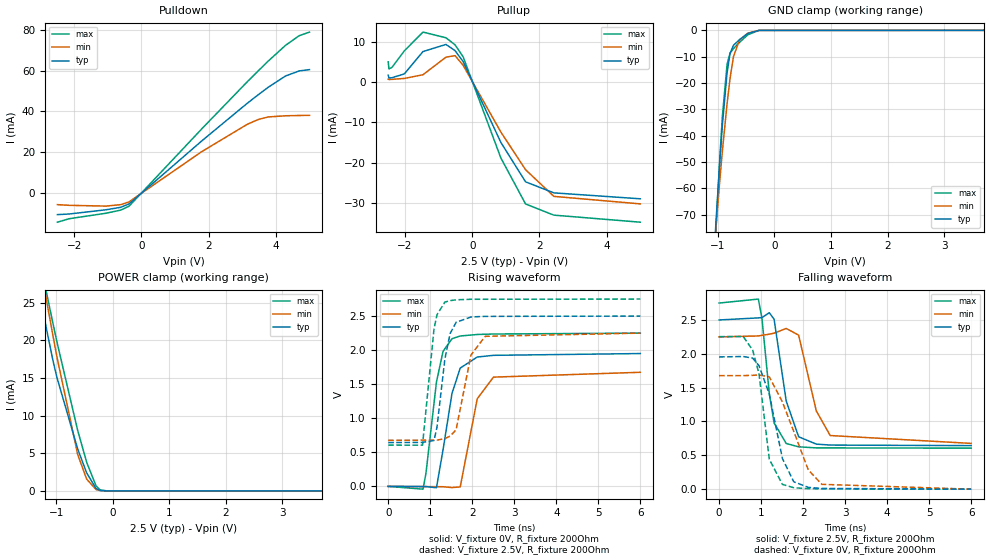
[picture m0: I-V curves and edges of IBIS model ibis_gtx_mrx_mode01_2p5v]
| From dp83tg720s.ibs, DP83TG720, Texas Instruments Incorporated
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| ibis_gtx_mrx_mode01_2p5v
[Model]   ibis_gtx_mrx_mode01_2p5v
Model_type   I/O
Polarity   Non-Inverting
Enable   Active-Low
Vinl = 0.54
Vinh = 1.26
Vmeas = 0.9
Vref = 0.9
Cref = 2pF
Rref = 100000
|   typ   min   max
C_comp   2.89pF   2.86pF   2.93pF
[Voltage Range]   2.5   2.25   2.75
[Temperature Range]   27   150   -40
[Pullup Reference]   2.5   2.25   2.75
[Pulldown Reference]   0   0   0
[Power Clamp Reference]   2.5   2.25   2.75
[GND Clamp Reference]   0   0   0
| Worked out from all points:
|   slope of the pulldown table from 0 to 0.375 V, typ, clamps not added: 69.2 ohm
|   slope of the pullup table from 0 to 0.375 V, typ, clamps not added: 54.5 ohm
|   GND clamp passes 1 mA (typ) near -0.45 V on its own axis
|   POWER clamp passes 1 mA (typ) near -0.37 V on its own axis
|   falling waveform, V_fixture 2.5V, R_fixture 200Ohm: 20-80 % time 278ps typ, 360ps min, 231ps max; typ from 2.5 V to 0.643 V
|   rising waveform, V_fixture 0V, R_fixture 200Ohm: 20-80 % time 325ps typ, 327ps min, 277ps max; typ from 0 V to 1.95 V
|   rising waveform, V_fixture 2.5V, R_fixture 200Ohm: 20-80 % time 232ps typ, 278ps min, 193ps max; typ from 0.643 V to 2.5 V
|   falling waveform, V_fixture 0V, R_fixture 200Ohm: 20-80 % time 423ps typ, 611ps min, 270ps max; typ from 1.95 V to 0 V
[Pulldown]
|   Voltage   I(typ)   I(min)   I(max)
-2.5V     -10.43mA   -5.548mA   -14.13mA
-2.147V   -10.12mA   -5.882mA   -12.43mA
-1.052V   -8.054mA   -6.263mA   -9.745mA
-617.5mV  -6.858mA   -5.55mA    -8.231mA
-370mV    -5.221mA   -4.201mA   -6.338mA
1.798V    25.65mA    20.41mA    31.55mA
3.147V    43.98mA    33.72mA    54.49mA
3.485V    48.3mA     36.14mA    60.02mA
3.777V    51.89mA    37.33mA    64.7mA
4.287V    57.35mA    37.9mA     72.33mA
4.692V    59.82mA    38.04mA    77.04mA
5V        60.47mA    38.12mA    78.82mA
[GND Clamp]
|   Voltage   I(typ)   I(min)   I(max)
-2.5V     -672.4mA   -578.6mA   -749.1mA
-1.097V   -97.01mA   -94.22mA   -103.2mA
-1.03V    -72.28mA   -74.57mA   -74.7mA
-962.5mV  -49.34mA   -56.59mA   -48.07mA
-917.5mV  -35.71mA   -45.65mA   -32.42mA
-835mV    -16.02mA   -27.78mA   -12.86mA
-782.5mV  -8.753mA   -18.2mA    -8.647mA
-722.5mV  -5.688mA   -10.01mA   -6.949mA
-617.5mV  -3.554mA   -3.701mA   -4.596mA
-467.5mV  -1.199mA   -1.052mA   -1.675mA
-272.5mV  -16.77uA   -38.36uA   -18.24uA
5V        0A         0A         0A
[Pullup]
|   Voltage   I(typ)   I(min)   I(max)
-2.5V     1.678mA    684.9uA    4.967mA
-2.478V   944.2uA    591uA      3.207mA
-2.388V   1.038mA    629.8uA    3.61mA
-2.02V    1.986mA    857.1uA    7.704mA
-1.465V   7.527mA    1.782mA    12.35mA
-782.5mV  9.287mA    6.133mA    10.94mA
-512.5mV  7.761mA    6.51mA     9.196mA
-272.5mV  5.053mA    4.138mA    6.248mA
852.5mV   -15.02mA   -12.45mA   -18.88mA
1.587V    -24.78mA   -21.78mA   -30.27mA
2.428V    -27.51mA   -28.38mA   -33.03mA
5V        -28.98mA   -30.24mA   -34.78mA
[POWER Clamp]
|   Voltage   I(typ)   I(min)   I(max)
-2.5V     144.5mA    109.4mA    191.7mA
-1.427V   32.73mA    36.35mA    36.62mA
-1.248V   24.72mA    28.61mA    29.23mA
-1.18V    21.93mA    25.78mA    26.73mA
-1.06V    17.49mA    20.82mA    22.43mA
-985mV    15.08mA    17.8mA     19.8mA
-617.5mV  5.56mA     4.81mA     8.015mA
-460mV    2.396mA    1.576mA    3.822mA
-295mV    328.2uA    185.9uA    693.1uA
-220mV    57.95uA    41.65uA    125.1uA
-92.5mV   988.6nA    1.88uA     1.238uA
5V        0A         0A         0A
[Ramp]
R_load = 200
|   typ   min   max
dV/dt_r   1.16978/3.24103e-10   1.005/3.24301e-10   1.35015/2.76259e-10
dV/dt_f   1.11392/2.75116e-10   0.944118/3.58503e-10   1.28631/2.28808e-10
[Falling Waveform]
V_fixture = 2.5V
V_fixture_min = 2.25V
V_fixture_max = 2.75V
R_fixture = 200Ohm
C_fixture = 0F
|   Time   V(typ)   V(min)   V(max)
0s        2.5V       2.25V      2.75V
935.8ps   2.531V     2.264V     2.809V
1.02ns    2.535V     2.273V     2.53V
1.196ns   2.607V     2.29V      1.413V
1.31ns    2.511V     2.305V     978.6mV
1.599ns   1.301V     2.375V     674.8mV
1.894ns   774.2mV    2.276V     625.8mV
2.315ns   665.7mV    1.156V     609.9mV
2.646ns   651.5mV    792.4mV    609.6mV
6ns       643.4mV    676.2mV    606.1mV
[Rising Waveform]
V_fixture = 0V
V_fixture_min = 0V
V_fixture_max = 0V
R_fixture = 200Ohm
C_fixture = 0F
|   Time   V(typ)   V(min)   V(max)
0s        2.374uV    15.5uV     1.345uV
828.1ps   -2.162mV   -3.221mV   -40.91mV
898.4ps   -2.345mV   -3.496mV   192.5mV
1.148ns   -20.29mV   -4.471mV   1.531V
1.305ns   538mV      -5.084mV   1.983V
1.518ns   1.365V     -17.51mV   2.168V
1.714ns   1.737V     -7.981mV   2.208V
2.119ns   1.899V     1.286V     2.23V
2.506ns   1.924V     1.604V     2.237V
6ns       1.95V      1.675V     2.25V
[Rising Waveform]
V_fixture = 2.5V
V_fixture_min = 2.25V
V_fixture_max = 2.75V
R_fixture = 200Ohm
C_fixture = 0F
|   Time   V(typ)   V(min)   V(max)
0s        643.4mV    676.2mV    606.1mV
815.9ps   645.5mV    678.4mV    604.5mV
1.09ns    674.1mV    679.1mV    2.313V
1.161ns   870.1mV    679.3mV    2.52V
1.348ns   1.868V     701.1mV    2.705V
1.474ns   2.244V     738.4mV    2.727V
1.616ns   2.409V     830.8mV    2.739V
1.97ns    2.487V     1.929V     2.747V
2.308ns   2.496V     2.203V     2.747V
6ns       2.5V       2.25V      2.75V
[Falling Waveform]
|Gnd
V_fixture = 0V
V_fixture_min = 0V
V_fixture_max = 0V
R_fixture = 200Ohm
C_fixture = 0F
|   Time   V(typ)   V(min)   V(max)
0s        1.954V     1.678V     2.254V
576.6ps   1.96V      1.678V     2.255V
802.1ps   1.936V     1.682V     2.052V
951.7ps   1.823V     1.688V     1.703V
1.196ns   1.405V     1.659V     443.1mV
1.507ns   453.5mV    1.29V      70.69mV
1.779ns   109mV      851.1mV    21.44mV
2.124ns   26.4mV     284.7mV    7.113mV
2.446ns   10.67mV    71.22mV    4.021mV
6ns       2.613uV    15.55uV    1.162uV
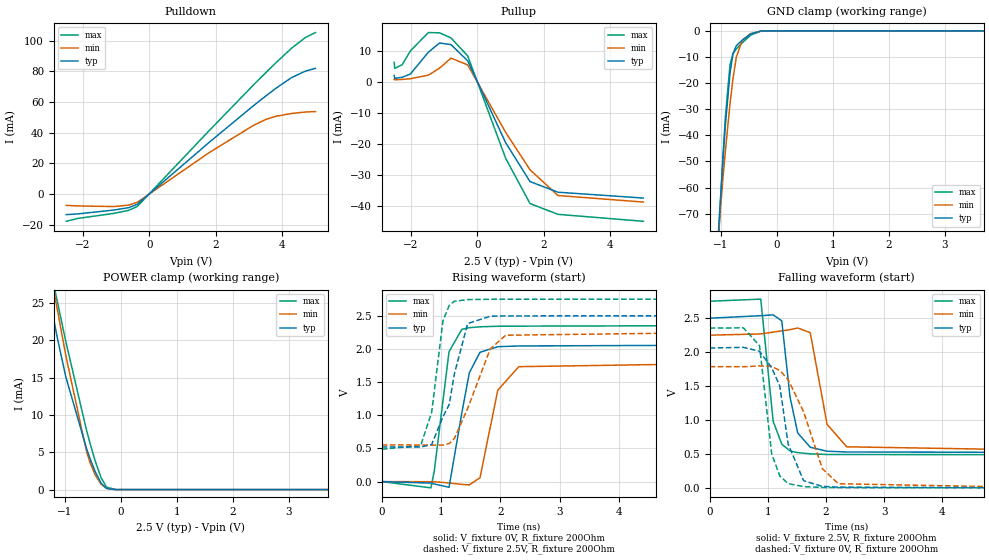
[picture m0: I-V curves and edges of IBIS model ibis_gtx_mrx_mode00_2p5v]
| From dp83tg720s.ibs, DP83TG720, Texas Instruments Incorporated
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| ibis_gtx_mrx_mode00_2p5v
[Model]   ibis_gtx_mrx_mode00_2p5v
Model_type   I/O
Polarity   Non-Inverting
Enable   Active-Low
Vinl = 0.75
Vinh = 1.75
Vmeas = 1.25
Vref = 1.25
Cref = 2pF
Rref = 100000
|   typ   min   max
C_comp   2.91pF   2.88pF   2.94pF
[Voltage Range]   2.5   2.25   2.75
[Temperature Range]   27   150   -40
[Pullup Reference]   2.5   2.25   2.75
[Pulldown Reference]   0   0   0
[Power Clamp Reference]   2.5   2.25   2.75
[GND Clamp Reference]   0   0   0
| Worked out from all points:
|   slope of the pulldown table from 0 to 0.375 V, typ, clamps not added: 52.8 ohm
|   slope of the pullup table from 0 to 0.375 V, typ, clamps not added: 42.1 ohm
|   GND clamp passes 1 mA (typ) near -0.45 V on its own axis
|   POWER clamp passes 1 mA (typ) near -0.37 V on its own axis
|   falling waveform, V_fixture 2.5V, R_fixture 200Ohm: 20-80 % time 178ps typ, 215ps min, 151ps max; typ from 2.5 V to 0.522 V
|   rising waveform, V_fixture 0V, R_fixture 200Ohm: 20-80 % time 231ps typ, 252ps min, 189ps max; typ from 0 V to 2.06 V
|   rising waveform, V_fixture 2.5V, R_fixture 200Ohm: 20-80 % time 317ps typ, 441ps min, 190ps max; typ from 0.522 V to 2.5 V
|   falling waveform, V_fixture 0V, R_fixture 200Ohm: 20-80 % time 263ps typ, 456ps min, 170ps max; typ from 2.06 V to 0 V
[Pulldown]
|   Voltage   I(typ)   I(min)   I(max)
-2.5V     -13.49mA   -7.447mA   -17.85mA
-2.17V    -13.06mA   -7.815mA   -16.03mA
-1.067V   -10.5mA    -8.222mA   -12.67mA
-617.5mV  -8.928mA   -7.264mA   -10.69mA
-362.5mV  -6.716mA   -5.43mA    -8.145mA
1.798V    33.66mA    26.98mA    41.3mA
3.147V    57.88mA    44.96mA    71.47mA
3.515V    64.15mA    48.74mA    79.44mA
3.815V    69.08mA    50.77mA    85.79mA
4.28V     75.97mA    52.55mA    95.16mA
4.692V    80.18mA    53.5mA     102.1mA
5V        82.04mA    53.81mA    105.4mA
[GND Clamp]
|   Voltage   I(typ)   I(min)   I(max)
-2.5V     -672.4mA   -578.6mA   -749.1mA
-1.097V   -97.01mA   -94.22mA   -103.2mA
-1.03V    -72.28mA   -74.57mA   -74.7mA
-962.5mV  -49.34mA   -56.59mA   -48.07mA
-917.5mV  -35.71mA   -45.65mA   -32.42mA
-835mV    -16.02mA   -27.78mA   -12.86mA
-782.5mV  -8.753mA   -18.2mA    -8.647mA
-722.5mV  -5.688mA   -10.01mA   -6.949mA
-617.5mV  -3.554mA   -3.702mA   -4.596mA
-467.5mV  -1.199mA   -1.052mA   -1.675mA
-272.5mV  -16.77uA   -38.63uA   -18.24uA
5V        0A         0A         0A
[Pullup]
|   Voltage   I(typ)   I(min)   I(max)
-2.5V     2.157mA    868.3uA    6.373mA
-2.485V   1.208mA    740.3uA    4.414mA
-2.26V    1.571mA    875.1uA    5.61mA
-2.013V   2.607mA    1.09mA     10.05mA
-1.472V   9.629mA    2.234mA    15.95mA
-1.135V   12.59mA    4.492mA    15.87mA
-790mV    12.07mA    7.725mA    14.22mA
-287.5mV  6.857mA    5.545mA    8.444mA
852.5mV   -19.44mA   -16.14mA   -24.45mA
1.587V    -32mA      -28.2mA    -39.07mA
2.428V    -35.43mA   -36.49mA   -42.55mA
5V        -37.31mA   -38.6mA    -44.79mA
[POWER Clamp]
|   Voltage   I(typ)   I(min)   I(max)
-2.5V     144.5mA    109.4mA    191.7mA
-1.42V    32.38mA    36.09mA    36.29mA
-1.248V   24.72mA    28.69mA    29.23mA
-1.15V    20.76mA    24.63mA    25.64mA
-985mV    15.08mA    17.93mA    19.8mA
-617.5mV  5.56mA     5.156mA    8.015mA
-550mV    4.112mA    3.562mA    6.126mA
-460mV    2.396mA    1.954mA    3.822mA
-355mV    860uA      725.3uA    1.597mA
-257.5mV  148.6uA    170.2uA    327.9uA
-92.5mV   988.6nA    4.315uA    1.238uA
5V        0A         0A         0A
[Ramp]
R_load = 200
|   typ   min   max
dV/dt_r   1.23438/2.30716e-10   1.06981/2.51046e-10   1.41077/1.88997e-10
dV/dt_f   1.18653/1.76194e-10   1.01854/2.12735e-10   1.35689/1.5082e-10
[Falling Waveform]
V_fixture = 2.5V
V_fixture_min = 2.25V
V_fixture_max = 2.75V
R_fixture = 200Ohm
C_fixture = 0F
|   Time   V(typ)   V(min)   V(max)
0s        2.5V       2.25V      2.75V
878.7ps   2.537V     2.268V     2.781V
1.092ns   2.549V     2.295V     984mV
1.24ns    2.462V     2.313V     644.6mV
1.382ns   1.34V      2.331V     544.1mV
1.514ns   809.8mV    2.356V     519.2mV
1.73ns    598mV      2.287V     501.1mV
2.02ns    540.1mV    934.8mV    491.8mV
2.357ns   528.6mV    605.1mV    491.6mV
6ns       522.4mV    552.3mV    488.5mV
[Rising Waveform]
V_fixture = 0V
V_fixture_min = 0V
V_fixture_max = 0V
R_fixture = 200Ohm
C_fixture = 0F
|   Time   V(typ)   V(min)   V(max)
0s        1.909uV    24.69uV    896.8nV
829.1ps   -22.76mV   -2.126mV   -94.4mV
887.2ps   -35.77mV   -2.277mV   168.9mV
1.135ns   -86.04mV   -20.53mV   1.959V
1.352ns   1.042V     -42.15mV   2.296V
1.477ns   1.64V      -49.8mV    2.319V
1.657ns   1.949V     58.92mV    2.333V
1.957ns   2.033V     1.378V     2.341V
2.311ns   2.044V     1.732V     2.343V
6ns       2.057V     1.783V     2.351V
[Rising Waveform]
V_fixture = 2.5V
V_fixture_min = 2.25V
V_fixture_max = 2.75V
R_fixture = 200Ohm
C_fixture = 0F
|   Time   V(typ)   V(min)   V(max)
0s        522.4mV    552.3mV    488.5mV
656.5ps   520.6mV    551.4mV    542.5mV
842ps     558.7mV    551.1mV    1.045V
1.032ns   976.9mV    550.8mV    2.422V
1.138ns   1.161V     573.6mV    2.655V
1.224ns   1.621V     647.5mV    2.718V
1.449ns   2.381V     1.102V     2.743V
1.829ns   2.493V     1.998V     2.748V
2.09ns    2.497V     2.206V     2.748V
6ns       2.5V       2.25V      2.75V
[Falling Waveform]
|Gnd
V_fixture = 0V
V_fixture_min = 0V
V_fixture_max = 0V
R_fixture = 200Ohm
C_fixture = 0F
|   Time   V(typ)   V(min)   V(max)
0s        2.061V     1.786V     2.354V
580.6ps   2.07V      1.785V     2.358V
857.4ps   2.013V     1.796V     2.096V
1.067ns   1.77V      1.79V      500.9mV
1.206ns   1.503V     1.73V      175.4mV
1.35ns    646.3mV    1.596V     62.13mV
1.616ns   105.4mV    1.12V      18.22mV
1.938ns   21.3mV     282.9mV    6.015mV
2.214ns   10.25mV    60.51mV    3.497mV
6ns       1.984uV    24.71uV    983.4nV
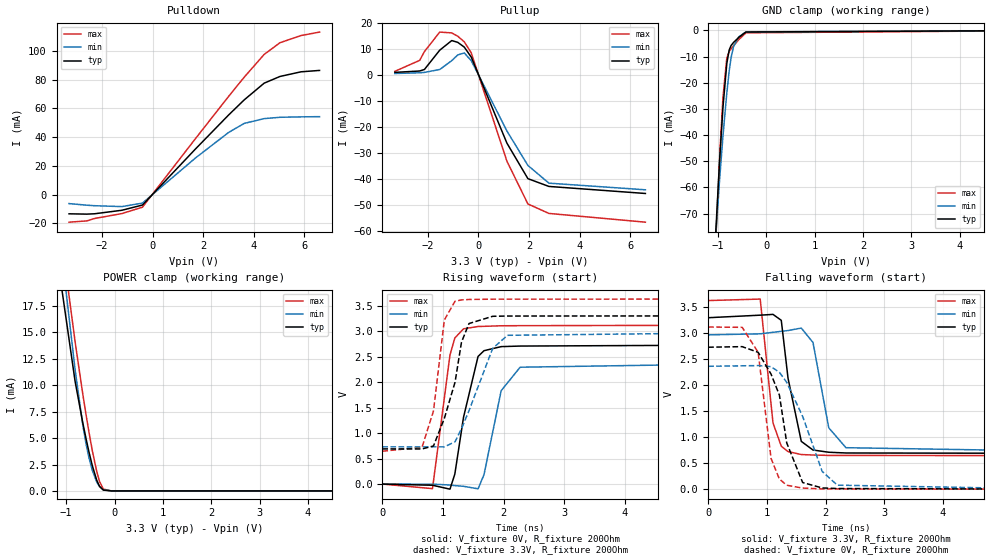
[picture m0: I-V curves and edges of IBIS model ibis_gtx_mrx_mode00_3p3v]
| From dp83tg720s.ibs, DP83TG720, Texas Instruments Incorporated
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| ibis_gtx_mrx_mode00_3p3v
[Model]   ibis_gtx_mrx_mode00_3p3v
Model_type   I/O
Polarity   Non-Inverting
Enable   Active-Low
Vinl = 0.99
Vinh = 2.31
Vmeas = 1.65
Vref = 1.65
Cref = 2pF
Rref = 100000
|   typ   min   max
C_comp   2.9pF   2.93pF   2.87pF
[Voltage Range]   3.3   2.97   3.63
[Temperature Range]   27   150   -40
[Pullup Reference]   3.3   2.97   3.63
[Pulldown Reference]   0   0   0
[Power Clamp Reference]   3.3   2.97   3.63
[GND Clamp Reference]   0   0   0
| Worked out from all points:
|   slope of the pulldown table from 0 to 0.495 V, typ, clamps not added: 52.8 ohm
|   slope of the pullup table from 0 to 0.495 V, typ, clamps not added: 41.1 ohm
|   GND clamp passes 1 mA (typ) near -0.45 V on its own axis
|   POWER clamp passes 1 mA (typ) near -0.37 V on its own axis
|   falling waveform, V_fixture 3.3V, R_fixture 200Ohm: 20-80 % time 180ps typ, 219ps min, 151ps max; typ from 3.3 V to 0.69 V
|   rising waveform, V_fixture 0V, R_fixture 200Ohm: 20-80 % time 228ps typ, 252ps min, 187ps max; typ from 0 V to 2.73 V
|   rising waveform, V_fixture 3.3V, R_fixture 200Ohm: 20-80 % time 308ps typ, 432ps min, 195ps max; typ from 0.69 V to 3.3 V
|   falling waveform, V_fixture 0V, R_fixture 200Ohm: 20-80 % time 316ps typ, 487ps min, 179ps max; typ from 2.73 V to 0 V
[Pulldown]
|   Voltage   I(typ)   I(min)   I(max)
-3.3V     -13.32mA   -6.214mA   -19.15mA
-2.597V   -13.54mA   -7.325mA   -18.24mA
-2.29V    -13.29mA   -7.689mA   -16.56mA
-1.211V   -10.85mA   -8.305mA   -13.15mA
-399.3mV  -7.224mA   -5.844mA   -8.717mA
1.69V     31.67mA    25.43mA    38.85mA
3.006V    55.42mA    43.29mA    68.37mA
3.62V     65.9mA     49.57mA    81.68mA
4.412V    77.59mA    52.92mA    97.6mA
5.036V    82.23mA    53.83mA    105.7mA
5.867V    85.47mA    54.12mA    110.7mA
6.6V      86.43mA    54.28mA    113.1mA
[GND Clamp]
|   Voltage   I(typ)   I(min)   I(max)
-3.3V     -1.011A    -865.8mA   -1.126A
-1.082V   -91.37mA   -89.71mA   -96.69mA
-1.053V   -80.45mA   -81.02mA   -84.12mA
-963.6mV  -49.69mA   -56.87mA   -48.48mA
-894.3mV  -29.4mA    -40.34mA   -25.48mA
-815.1mV  -12.66mA   -23.94mA   -10.6mA
-765.6mV  -7.479mA   -15.54mA   -8.067mA
-726mV    -5.787mA   -10.39mA   -7.032mA
-676.5mV  -4.645mA   -6.247mA   -5.893mA
-567.6mV  -2.701mA   -2.49mA    -3.55mA
-419.1mV  -641.7uA   -597.9uA   -944.7uA
6.6V      0A         0A         0A
[Pullup]
|   Voltage   I(typ)   I(min)   I(max)
-3.3V     1.024mA    596.1uA    1.43mA
-2.32V    1.558mA    868.7uA    5.65mA
-2.132V   2.15mA     1.016mA    9.03mA
-1.528V   9.563mA    2.138mA    16.53mA
-1.053V   13.27mA    5.538mA    16.22mA
-815.1mV  12.58mA    7.751mA    14.93mA
-557.7mV  10.75mA    8.499mA    12.79mA
-280.5mV  6.871mA    5.515mA    8.509mA
1.125V    -26.16mA   -21.49mA   -33.1mA
1.957V    -39.88mA   -34.79mA   -49.62mA
2.788V    -42.87mA   -41.61mA   -53.26mA
6.6V      -45.58mA   -44.16mA   -56.63mA
[POWER Clamp]
|   Voltage   I(typ)   I(min)   I(max)
-3.3V     317.9mA    237mA      400.5mA
-1.181V   21.99mA    25.93mA    26.78mA
-815.1mV  10.35mA    11.45mA    14.1mA
-656.7mV  6.45mA     6.234mA    9.162mA
-587.4mV  4.9mA      4.403mA    7.158mA
-528mV    3.668mA    3.117mA    5.537mA
-458.7mV  2.373mA    1.935mA    3.791mA
-369.6mV  1.032mA    856.8uA    1.866mA
-310.2mV  435.4uA    402.4uA    888uA
-231mV    77.39uA    103.3uA    169.6uA
-62.7mV   288.6nA    1.815uA    282.8nA
6.6V      0A         0A         0A
[Ramp]
R_load = 200
|   typ   min   max
dV/dt_r   1.63673/2.28449e-10   1.41658/2.50163e-10   1.87047/1.86163e-10
dV/dt_f   1.56582/1.78632e-10   1.34358/2.1855e-10   1.79086/1.50296e-10
[Falling Waveform]
V_fixture = 3.3V
V_fixture_min = 2.97V
V_fixture_max = 3.63V
R_fixture = 200Ohm
C_fixture = 0F
|   Time   V(typ)   V(min)   V(max)
0s        3.3V       2.97V      3.63V
886.1ps   3.349V     2.99V      3.659V
1.104ns   3.364V     3.019V     1.274V
1.245ns   3.25V      3.038V     827.6mV
1.36ns    2.135V     3.053V     723.3mV
1.586ns   919.7mV    3.101V     666.4mV
1.785ns   753.6mV    2.824V     657.2mV
2.054ns   710.6mV    1.181V     649.5mV
2.347ns   696.3mV    798.3mV    649.2mV
6ns       690.3mV    730.6mV    645.2mV
[Rising Waveform]
V_fixture = 0V
V_fixture_min = 0V
V_fixture_max = 0V
R_fixture = 200Ohm
C_fixture = 0F
|   Time   V(typ)   V(min)   V(max)
0s        1.97uV     25.02uV    1.138uV
826.9ps   -22.52mV   -1.982mV   -88.84mV
1.115ns   -99.52mV   -17.63mV   2.534V
1.195ns   196mV      -29.74mV   2.866V
1.338ns   1.309V     -42.95mV   3.046V
1.578ns   2.504V     -93.04mV   3.092V
1.676ns   2.617V     184.3mV    3.095V
1.959ns   2.697V     1.832V     3.106V
2.272ns   2.708V     2.293V     3.108V
6ns       2.728V     2.361V     3.117V
[Rising Waveform]
V_fixture = 3.3V
V_fixture_min = 2.97V
V_fixture_max = 3.63V
R_fixture = 200Ohm
C_fixture = 0F
|   Time   V(typ)   V(min)   V(max)
0s        690.3mV    730.6mV    645.2mV
654.3ps   689.6mV    730.4mV    722.6mV
843ps     747.8mV    730.4mV    1.435V
1.022ns   1.288V     730.4mV    3.219V
1.199ns   2.001V     829.6mV    3.589V
1.305ns   2.785V     1.088V     3.613V
1.429ns   3.15V      1.441V     3.622V
1.819ns   3.292V     2.663V     3.628V
2.065ns   3.297V     2.919V     3.628V
6ns       3.3V       2.97V      3.63V
[Falling Waveform]
|Gnd
V_fixture = 0V
V_fixture_min = 0V
V_fixture_max = 0V
R_fixture = 200Ohm
C_fixture = 0F
|   Time   V(typ)   V(min)   V(max)
0s        2.732V     2.365V     3.121V
579.1ps   2.743V     2.374V     3.115V
850.9ps   2.634V     2.379V     2.635V
1.071ns   2.214V     2.357V     590.4mV
1.213ns   1.81V      2.249V     193.9mV
1.338ns   890.1mV    2.056V     75.94mV
1.609ns   127.7mV    1.401V     20.82mV
1.941ns   23.61mV    341.8mV    5.193mV
2.2ns     12.32mV    76.96mV    4.636mV
6ns       2.035uV    25.1uV     1.208uV
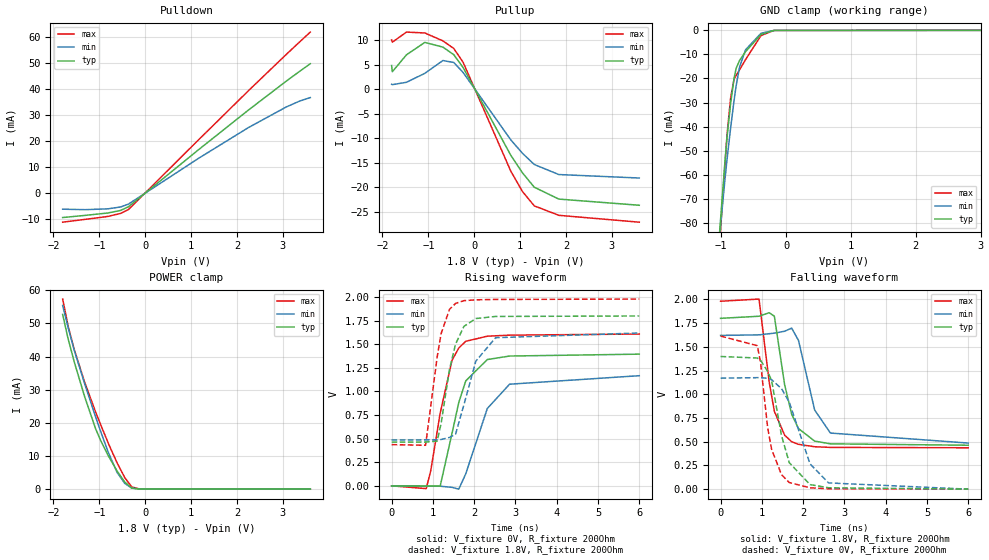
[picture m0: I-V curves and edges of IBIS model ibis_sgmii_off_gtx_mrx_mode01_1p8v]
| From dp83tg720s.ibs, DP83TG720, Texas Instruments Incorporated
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| ibis_sgmii_off_gtx_mrx_mode01_1p8v
[Model]   ibis_sgmii_off_gtx_mrx_mode01_1p8v
Model_type   I/O
Polarity   Non-Inverting
Enable   Active-Low
Vinl = 0.54
Vinh = 1.26
Vmeas = 0.9
Vref = 0.9
Cref = 2pF
Rref = 100000
|   typ   min   max
C_comp   3.96pF   3.92pF   4.01pF
[Voltage Range]   1.8   1.62   1.98
[Temperature Range]   27   150   -40
[Pullup Reference]   1.8   1.62   1.98
[Pulldown Reference]   0   0   0
[Power Clamp Reference]   1.8   1.62   1.98
[GND Clamp Reference]   0   0   0
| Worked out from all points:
|   slope of the pulldown table from 0 to 0.27 V, typ, clamps not added: 69.1 ohm
|   slope of the pullup table from 0 to 0.27 V, typ, clamps not added: 55.9 ohm
|   GND clamp passes 1 mA (typ) near -0.34 V on its own axis
|   POWER clamp passes 1 mA (typ) near -0.37 V on its own axis
|   falling waveform, V_fixture 1.8V, R_fixture 200Ohm: 20-80 % time 358ps typ, 440ps min, 300ps max; typ from 1.8 V to 0.463 V
|   rising waveform, V_fixture 0V, R_fixture 200Ohm: 20-80 % time 465ps typ, 593ps min, 420ps max; typ from 0 V to 1.39 V
|   rising waveform, V_fixture 1.8V, R_fixture 200Ohm: 20-80 % time 348ps typ, 444ps min, 298ps max; typ from 0.463 V to 1.8 V
|   falling waveform, V_fixture 0V, R_fixture 200Ohm: 20-80 % time 409ps typ, 569ps min, 315ps max; typ from 1.4 V to 0 V
[Pulldown]
|   Voltage   I(typ)   I(min)   I(max)
-1.8V     -9.357mA   -6.143mA   -11.14mA
-1.314V   -8.53mA    -6.332mA   -10.07mA
-817.2mV  -7.619mA   -6.018mA   -8.943mA
-536.4mV  -6.617mA   -5.291mA   -7.764mA
-363.6mV  -5.19mA    -4.174mA   -6.249mA
1.165V    16.73mA    13.42mA    20.53mA
2.255V    31.99mA    25.25mA    39.43mA
3.076V    43.05mA    33.12mA    53.31mA
3.368V    46.82mA    35.39mA    58.12mA
3.6V      49.74mA    36.73mA    61.88mA
[GND Clamp]
|   Voltage   I(typ)   I(min)   I(max)
-1.8V     -413mA     -361.3mA   -461.4mA
-1.022V   -83.06mA   -84.73mA   -87.93mA
-941.4mV  -54.43mA   -61.85mA   -55.74mA
-909mV    -44.33mA   -53.48mA   -43.2mA
-855mV    -30.54mA   -40.73mA   -28.24mA
-801mV    -19.92mA   -29.1mA    -20.25mA
-768.6mV  -15.71mA   -22.89mA   -18.77mA
-714.6mV  -12.42mA   -15.06mA   -16.29mA
-622.8mV  -8.805mA   -8.036mA   -12.09mA
-385.2mV  -1.682mA   -1.218mA   -2.156mA
-185.4mV  -38.15uA   -31.25uA   -36.48uA
3.6V      0A         0A         0A
[Pullup]
|   Voltage   I(typ)   I(min)   I(max)
-1.8V     4.808mA    1.002mA    10.03mA
-1.784V   3.543mA    903.4uA    9.57mA
-1.476V   6.992mA    1.393mA    11.62mA
-1.076V   9.516mA    3.213mA    11.44mA
-682.2mV  8.561mA    5.824mA    9.831mA
-444.6mV  7.009mA    5.431mA    8.283mA
-239.4mV  4.37mA     3.367mA    5.431mA
797.4mV   -13.47mA   -10.33mA   -16.7mA
1.051V    -17.04mA   -13.06mA   -20.85mA
1.31V     -19.99mA   -15.36mA   -23.79mA
1.845V    -22.41mA   -17.41mA   -25.72mA
3.6V      -23.67mA   -18.12mA   -27.12mA
[POWER Clamp]
|   Voltage   I(typ)   I(min)   I(max)
-1.8V     52.72mA    55.43mA    57.36mA
-1.681V   45.36mA    48.74mA    49.19mA
-1.546V   38.34mA    41.85mA    42.08mA
-1.319V   27.84mA    31.74mA    32.21mA
-1.082V   18.24mA    21.83mA    23.29mA
-979.2mV  14.91mA    17.7mA     19.75mA
-806.4mV  10.12mA    11.14mA    13.88mA
-612mV    5.438mA    5.014mA    7.891mA
-444.6mV  2.133mA    1.733mA    3.461mA
-293.4mV  326.9uA    317uA      674.2uA
-109.8mV  6.028uA    13.64uA    2.638uA
3.6V      0A         0A         0A
[Ramp]
R_load = 200
|   typ   min   max
dV/dt_r   0.836625/4.6343e-10   0.699395/5.92737e-10   0.964308/4.16869e-10
dV/dt_f   0.80208/3.56393e-10   0.680128/4.39905e-10   0.926047/2.99055e-10
[Falling Waveform]
V_fixture = 1.8V
V_fixture_min = 1.62V
V_fixture_max = 1.98V
R_fixture = 200Ohm
C_fixture = 0F
|   Time   V(typ)   V(min)   V(max)
0s        1.8V       1.62V      1.98V
931.6ps   1.822V     1.626V     2.003V
1.177ns   1.859V     1.638V     1.132V
1.303ns   1.822V     1.644V     820.3mV
1.552ns   1.1V       1.664V     568.9mV
1.722ns   789.9mV    1.697V     500.1mV
1.888ns   638.4mV    1.567V     472.4mV
2.279ns   506.7mV    834mV      447.3mV
2.661ns   477.9mV    591.4mV    440.2mV
6ns       463mV      486mV      436.3mV
[Rising Waveform]
V_fixture = 0V
V_fixture_min = 0V
V_fixture_max = 0V
R_fixture = 200Ohm
C_fixture = 0F
|   Time   V(typ)   V(min)   V(max)
0s        60.38uV    61.77uV    96.55uV
837.9ps   -1.786mV   -2.655mV   -29.1mV
948.6ps   -2.03mV    -3.013mV   161.1mV
1.177ns   -1.82mV    -3.754mV   771mV
1.463ns   555.1mV    -15.91mV   1.329V
1.627ns   882.6mV    -34.97mV   1.459V
1.796ns   1.111V     127.4mV    1.53V
2.318ns   1.337V     818.7mV    1.584V
2.858ns   1.374V     1.076V     1.595V
6ns       1.394V     1.166V     1.607V
[Rising Waveform]
V_fixture = 1.8V
V_fixture_min = 1.62V
V_fixture_max = 1.98V
R_fixture = 200Ohm
C_fixture = 0F
|   Time   V(typ)   V(min)   V(max)
0s        462.8mV    485.8mV    436.2mV
823ps     463.7mV    486.7mV    429.6mV
1.104ns   473.4mV    487mV      1.365V
1.199ns   660.7mV    490.7mV    1.611V
1.401ns   1.231V     512.2mV    1.867V
1.549ns   1.5V       546.7mV    1.931V
1.752ns   1.688V     859.1mV    1.96V
2.04ns    1.771V     1.32V      1.969V
2.519ns   1.793V     1.568V     1.973V
6ns       1.798V     1.618V     1.977V
[Falling Waveform]
|Gnd
V_fixture = 0V
V_fixture_min = 0V
V_fixture_max = 0V
R_fixture = 200Ohm
C_fixture = 0F
|   Time   V(typ)   V(min)   V(max)
0s        1.398V     1.17V      1.613V
889.6ps   1.382V     1.175V     1.512V
966ps     1.359V     1.176V     1.344V
1.139ns   1.242V     1.168V     650.6mV
1.237ns   1.144V     1.153V     419mV
1.477ns   564.3mV    1.059V     152.4mV
1.664ns   279.4mV    916.6mV    70.1mV
2.167ns   48.52mV    267.1mV    14.8mV
2.616ns   15.19mV    66.15mV    4.118mV
6ns       253.7uV    245uV      264.9uV
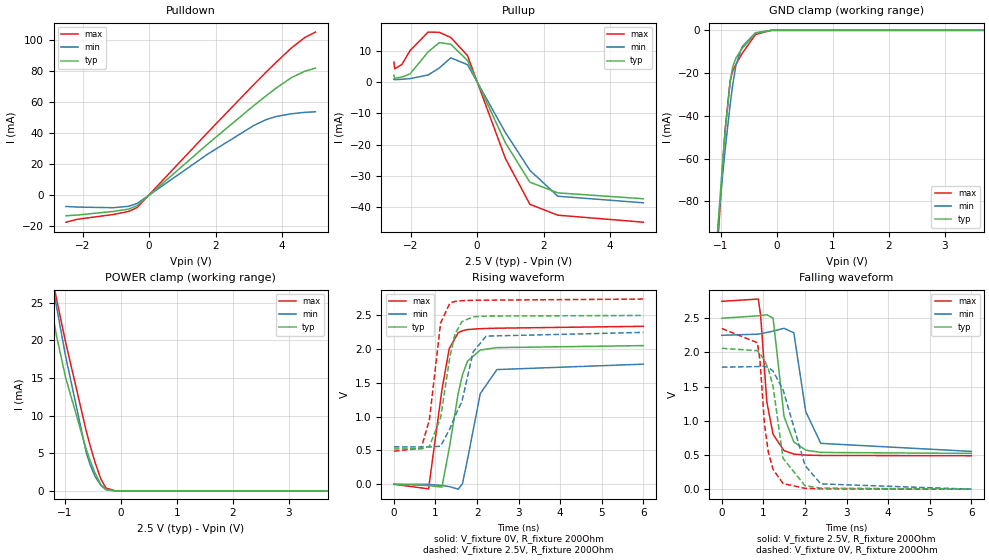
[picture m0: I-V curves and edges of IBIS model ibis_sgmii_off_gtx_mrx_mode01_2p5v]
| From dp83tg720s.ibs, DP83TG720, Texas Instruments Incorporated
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| ibis_sgmii_off_gtx_mrx_mode01_2p5v
[Model]   ibis_sgmii_off_gtx_mrx_mode01_2p5v
Model_type   I/O
Polarity   Non-Inverting
Enable   Active-Low
Vinl = 0.75
Vinh = 1.75
Vmeas = 1.25
Vref = 1.25
Cref = 2pF
Rref = 100000
|   typ   min   max
C_comp   3.97pF   3.96pF   4.03pF
[Voltage Range]   2.5   2.25   2.75
[Temperature Range]   27   150   -40
[Pullup Reference]   2.5   2.25   2.75
[Pulldown Reference]   0   -0   0
[Power Clamp Reference]   2.5   2.25   2.75
[GND Clamp Reference]   0   0   0
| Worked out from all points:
|   slope of the pulldown table from 0 to 0.375 V, typ, clamps not added: 52.8 ohm
|   slope of the pullup table from 0 to 0.375 V, typ, clamps not added: 42.1 ohm
|   GND clamp passes 1 mA (typ) near -0.35 V on its own axis
|   POWER clamp passes 1 mA (typ) near -0.37 V on its own axis
|   falling waveform, V_fixture 2.5V, R_fixture 200Ohm: 20-80 % time 248ps typ, 296ps min, 210ps max; typ from 2.5 V to 0.523 V
|   rising waveform, V_fixture 0V, R_fixture 200Ohm: 20-80 % time 359ps typ, 360ps min, 304ps max; typ from 0 V to 2.05 V
|   rising waveform, V_fixture 2.5V, R_fixture 200Ohm: 20-80 % time 346ps typ, 490ps min, 246ps max; typ from 0.522 V to 2.49 V
|   falling waveform, V_fixture 0V, R_fixture 200Ohm: 20-80 % time 305ps typ, 506ps min, 226ps max; typ from 2.06 V to 0 V
[Pulldown]
|   Voltage   I(typ)   I(min)   I(max)
-2.5V     -13.45mA   -7.447mA   -17.61mA
-2.155V   -12.97mA   -7.831mA   -15.71mA
-1.075V   -10.65mA   -8.235mA   -12.62mA
-617.5mV  -9.154mA   -7.316mA   -10.68mA
-362.5mV  -6.904mA   -5.51mA    -8.139mA
1.768V    33.1mA     26.55mA    40.62mA
3.147V    57.88mA    44.96mA    71.47mA
3.515V    64.15mA    48.74mA    79.44mA
3.815V    69.08mA    50.77mA    85.79mA
4.28V     75.97mA    52.55mA    95.16mA
4.692V    80.18mA    53.5mA     102.1mA
5V        82.04mA    53.81mA    105.4mA
[GND Clamp]
|   Voltage   I(typ)   I(min)   I(max)
-2.5V     -724mA     -627mA     -809.2mA
-1.105V   -115.2mA   -110.6mA   -124.9mA
-1.038V   -88.81mA   -89.31mA   -94.59mA
-970mV    -64.1mA    -69.63mA   -65.98mA
-917.5mV  -46.91mA   -55.66mA   -46.17mA
-827.5mV  -23.96mA   -34.42mA   -23.36mA
-782.5mV  -17.1mA    -25.4mA    -18.99mA
-722.5mV  -12.81mA   -16.03mA   -15.81mA
-617.5mV  -8.604mA   -7.803mA   -10.94mA
-377.5mV  -1.419mA   -1.113mA   -1.967mA
-92.5mV   -1.691uA   -3.604uA   -1.18uA
5V        0A         0A         0A
[Pullup]
|   Voltage   I(typ)   I(min)   I(max)
-2.5V     2.157mA    868.3uA    6.373mA
-2.478V   1.217mA    744.2uA    4.236mA
-2.26V    1.571mA    875uA      5.609mA
-2.013V   2.607mA    1.09mA     10.05mA
-1.472V   9.629mA    2.234mA    15.95mA
-1.135V   12.59mA    4.492mA    15.87mA
-790mV    12.07mA    7.724mA    14.22mA
-287.5mV  6.857mA    5.545mA    8.443mA
852.5mV   -19.44mA   -16.14mA   -24.44mA
1.587V    -32mA      -28.2mA    -39.07mA
2.428V    -35.42mA   -36.49mA   -42.55mA
5V        -37.3mA    -38.59mA   -44.79mA
[POWER Clamp]
|   Voltage   I(typ)   I(min)   I(max)
-2.5V     144.5mA    109.4mA    191.7mA
-1.42V    32.38mA    36.09mA    36.29mA
-1.248V   24.72mA    28.69mA    29.23mA
-1.15V    20.76mA    24.63mA    25.64mA
-985mV    15.08mA    17.93mA    19.8mA
-617.5mV  5.56mA     5.156mA    8.015mA
-550mV    4.112mA    3.562mA    6.126mA
-460mV    2.396mA    1.954mA    3.822mA
-355mV    860uA      725.4uA    1.597mA
-265mV    175.4uA    194.5uA    387.3uA
-92.5mV   977.4nA    4.357uA    1.228uA
5V        0A         0A         0A
[Ramp]
R_load = 200
|   typ   min   max
dV/dt_r   1.22796/3.57426e-10   1.06374/3.57289e-10   1.39888/3.03777e-10
dV/dt_f   1.18613/2.45817e-10   1.01817/2.92876e-10   1.35519/2.08436e-10
[Falling Waveform]
V_fixture = 2.5V
V_fixture_min = 2.25V
V_fixture_max = 2.75V
R_fixture = 200Ohm
C_fixture = 0F
|   Time   V(typ)   V(min)   V(max)
0s        2.5V       2.25V      2.747V
878.5ps   2.535V     2.267V     2.78V
933.7ps   2.539V     2.274V     2.537V
1.083ns   2.551V     2.292V     1.272V
1.233ns   2.501V     2.311V     801.5mV
1.496ns   1.063V     2.353V     564.1mV
1.731ns   691.1mV    2.287V     513.9mV
2.019ns   570.6mV    1.133V     497.8mV
2.38ns    537.4mV    670mV      493.4mV
6ns       522.7mV    552.6mV    488.8mV
[Rising Waveform]
V_fixture = 0V
V_fixture_min = 0V
V_fixture_max = 0V
R_fixture = 200Ohm
C_fixture = 0F
|   Time   V(typ)   V(min)   V(max)
0s        83.38uV    67.03uV    95.95uV
833.5ps   -18.87mV   -1.441mV   -67.91mV
1.154ns   -42.22mV   -18.73mV   1.391V
1.329ns   523.6mV    -33.53mV   1.999V
1.546ns   1.339V     -72.31mV   2.237V
1.648ns   1.615V     5.495mV    2.266V
1.771ns   1.819V     370.6mV    2.284V
2.078ns   1.982V     1.339V     2.297V
2.477ns   2.017V     1.693V     2.304V
6ns       2.047V     1.773V     2.332V
[Rising Waveform]
V_fixture = 2.5V
V_fixture_min = 2.25V
V_fixture_max = 2.75V
R_fixture = 200Ohm
C_fixture = 0F
|   Time   V(typ)   V(min)   V(max)
0s        522.5mV    552.3mV    488.6mV
657.4ps   520.9mV    551.6mV    532.7mV
854.2ps   560.2mV    551.4mV    955.3mV
1.123ns   980.9mV    562.2mV    2.38V
1.347ns   1.884V     821.2mV    2.676V
1.468ns   2.215V     1.004V     2.699V
1.634ns   2.401V     1.218V     2.71V
1.907ns   2.472V     1.955V     2.716V
2.218ns   2.483V     2.187V     2.718V
6ns       2.492V     2.242V     2.734V
[Falling Waveform]
|Gnd
V_fixture = 0V
V_fixture_min = 0V
V_fixture_max = 0V
R_fixture = 200Ohm
C_fixture = 0F
|   Time   V(typ)   V(min)   V(max)
0s        2.06V      1.784V     2.35V
854.2ps   2.025V     1.793V     2.142V
915.9ps   1.985V     1.795V     1.893V
1.025ns   1.886V     1.798V     955.5mV
1.117ns   1.76V      1.781V     544.5mV
1.233ns   1.501V     1.726V     288.3mV
1.473ns   451mV      1.452V     82.26mV
2ns       50.7mV     347.1mV    12.33mV
2.38ns    16.14mV    77.34mV    5.532mV
6ns       273uV      302.6uV    272.7uV
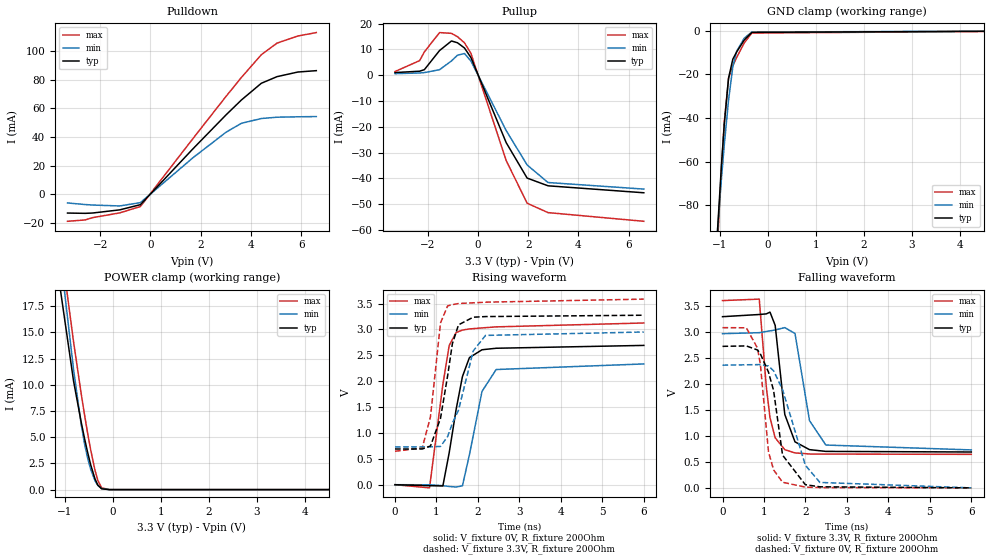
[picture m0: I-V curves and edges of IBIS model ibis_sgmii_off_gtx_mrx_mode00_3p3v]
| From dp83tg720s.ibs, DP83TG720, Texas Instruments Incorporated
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| ibis_sgmii_off_gtx_mrx_mode00_3p3v
[Model]   ibis_sgmii_off_gtx_mrx_mode00_3p3v
Model_type   I/O
Polarity   Non-Inverting
Enable   Active-Low
Vinl = 0.99
Vinh = 2.31
Vmeas = 1.65
Vref = 1.65
Cref = 2pF
Rref = 100000
|   typ   min   max
C_comp   3.97pF   3.92pF   4.01pF
[Voltage Range]   3.3   2.97   3.63
[Temperature Range]   27   150   -40
[Pullup Reference]   3.3   2.97   3.63
[Pulldown Reference]   -0   -0   -0
[Power Clamp Reference]   3.3   2.97   3.63
[GND Clamp Reference]   0   0   0
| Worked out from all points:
|   slope of the pulldown table from 0 to 0.495 V, typ, clamps not added: 52.8 ohm
|   slope of the pullup table from 0 to 0.495 V, typ, clamps not added: 41.1 ohm
|   GND clamp passes 1 mA (typ) near -0.35 V on its own axis
|   POWER clamp passes 1 mA (typ) near -0.37 V on its own axis
|   falling waveform, V_fixture 3.3V, R_fixture 200Ohm: 20-80 % time 246ps typ, 297ps min, 207ps max; typ from 3.3 V to 0.691 V
|   rising waveform, V_fixture 0V, R_fixture 200Ohm: 20-80 % time 355ps typ, 359ps min, 294ps max; typ from 0 V to 2.69 V
|   rising waveform, V_fixture 3.3V, R_fixture 200Ohm: 20-80 % time 342ps typ, 477ps min, 233ps max; typ from 0.69 V to 3.27 V
|   falling waveform, V_fixture 0V, R_fixture 200Ohm: 20-80 % time 344ps typ, 531ps min, 229ps max; typ from 2.73 V to 0 V
[Pulldown]
|   Voltage   I(typ)   I(min)   I(max)
-3.3V     -13.28mA   -6.213mA   -19.06mA
-2.597V   -13.49mA   -7.325mA   -18.1mA
-2.3V     -13.26mA   -7.679mA   -16.49mA
-1.221V   -11.04mA   -8.314mA   -13.16mA
-399.3mV  -7.421mA   -5.978mA   -8.71mA
1.68V     31.49mA    25.28mA    38.62mA
3.006V    55.42mA    43.29mA    68.37mA
3.62V     65.9mA     49.57mA    81.68mA
4.412V    77.59mA    52.92mA    97.6mA
5.036V    82.23mA    53.83mA    105.7mA
5.867V    85.47mA    54.12mA    110.7mA
6.6V      86.43mA    54.28mA    113.1mA
[GND Clamp]
|   Voltage   I(typ)   I(min)   I(max)
-3.3V     -1.085A    -934.6mA   -1.211A
-1.092V   -110.2mA   -106.5mA   -119.2mA
-1.063V   -98.5mA    -97.09mA   -105.8mA
-1.053V   -94.66mA   -94.01mA   -101.4mA
-963.6mV  -61.91mA   -67.88mA   -63.46mA
-904.2mV  -42.96mA   -52.32mA   -41.79mA
-815.1mV  -21.71mA   -31.82mA   -21.8mA
-726mV    -13mA      -16.49mA   -16mA
-646.8mV  -9.718mA   -9.376mA   -12.28mA
-488.4mV  -4.237mA   -3.373mA   -5.539mA
-330mV    -723.2uA   -565.9uA   -1.02mA
6.6V      0A         0A         0A
[Pullup]
|   Voltage   I(typ)   I(min)   I(max)
-3.3V     1.024mA    596.1uA    1.43mA
-2.32V    1.558mA    868.7uA    5.65mA
-2.132V   2.15mA     1.016mA    9.03mA
-1.528V   9.563mA    2.138mA    16.53mA
-1.053V   13.27mA    5.538mA    16.22mA
-815.1mV  12.58mA    7.751mA    14.93mA
-537.9mV  10.57mA    8.413mA    12.58mA
-280.5mV  6.872mA    5.513mA    8.508mA
1.125V    -26.16mA   -21.49mA   -33.1mA
1.957V    -39.88mA   -34.79mA   -49.62mA
2.788V    -42.87mA   -41.6mA    -53.26mA
6.6V      -45.57mA   -44.14mA   -56.63mA
[POWER Clamp]
|   Voltage   I(typ)   I(min)   I(max)
-3.3V     317.9mA    237mA      400.5mA
-1.181V   21.99mA    25.93mA    26.78mA
-815.1mV  10.35mA    11.45mA    14.1mA
-656.7mV  6.45mA     6.234mA    9.162mA
-587.4mV  4.9mA      4.403mA    7.158mA
-528mV    3.668mA    3.117mA    5.537mA
-458.7mV  2.373mA    1.935mA    3.791mA
-369.6mV  1.032mA    856.8uA    1.866mA
-310.2mV  435.4uA    402.5uA    888uA
-231mV    77.38uA    103.3uA    169.6uA
-72.6mV   430.9nA    2.491uA    462.9nA
6.6V      0A         0A         0A
[Ramp]
R_load = 200
|   typ   min   max
dV/dt_r   1.61441/3.54859e-10   1.39973/3.55903e-10   1.87422/2.94253e-10
dV/dt_f   1.56334/2.43575e-10   1.34259/2.93428e-10   1.77634/2.04835e-10
[Falling Waveform]
V_fixture = 3.3V
V_fixture_min = 2.97V
V_fixture_max = 3.63V
R_fixture = 200Ohm
C_fixture = 0F
|   Time   V(typ)   V(min)   V(max)
0s        3.296V     2.969V     3.606V
886.1ps   3.338V     2.988V     3.634V
1.056ns   3.35V      3.011V     1.945V
1.145ns   3.384V     3.023V     1.352V
1.27ns    3.129V     3.04V      965.1mV
1.502ns   1.413V     3.086V     734.7mV
1.748ns   886mV      2.972V     673.1mV
2.098ns   736.1mV    1.295V     652.2mV
2.492ns   702.6mV    824.7mV    650.8mV
6ns       690.6mV    730.9mV    645.5mV
[Rising Waveform]
V_fixture = 0V
V_fixture_min = 0V
V_fixture_max = 0V
R_fixture = 200Ohm
C_fixture = 0F
|   Time   V(typ)   V(min)   V(max)
0s        74.45uV    77.73uV    -846.1nV
832.5ps   -19.12mV   -1.386mV   -60.91mV
1.154ns   -23.75mV   -18.65mV   1.936V
1.306ns   614.6mV    -34.51mV   2.688V
1.475ns   1.46V      -44.48mV   2.94V
1.626ns   2.089V     -21.13mV   2.987V
1.794ns   2.455V     577.8mV    3.009V
2.098ns   2.607V     1.803V     3.029V
2.439ns   2.636V     2.225V     3.049V
6ns       2.691V     2.333V     3.124V
[Rising Waveform]
V_fixture = 3.3V
V_fixture_min = 2.97V
V_fixture_max = 3.63V
R_fixture = 200Ohm
C_fixture = 0F
|   Time   V(typ)   V(min)   V(max)
0s        690.3mV    730.6mV    645.3mV
656.1ps   689.8mV    730.5mV    710.4mV
855.5ps   747.9mV    730.5mV    1.313V
1.097ns   1.282V     739.6mV    3.125V
1.27ns    2.11V      931.4mV    3.456V
1.383ns   2.722V     1.187V     3.478V
1.531ns   3.088V     1.44V      3.5V
1.886ns   3.236V     2.584V     3.514V
2.182ns   3.248V     2.884V     3.526V
6ns       3.274V     2.95V      3.585V
[Falling Waveform]
|Gnd
V_fixture = 0V
V_fixture_min = 0V
V_fixture_max = 0V
R_fixture = 200Ohm
C_fixture = 0F
|   Time   V(typ)   V(min)   V(max)
0s        2.725V     2.362V     3.085V
574.3ps   2.733V     2.37V      3.082V
843ps     2.655V     2.373V     2.691V
912.8ps   2.58V      2.374V     2.378V
1.109ns   2.228V     2.346V     692.4mV
1.232ns   1.874V     2.254V     346.5mV
1.448ns   630.5mV    1.892V     108.6mV
1.997ns   61.61mV    436.2mV    14.37mV
2.349ns   20.51mV    104.7mV    6.35mV
6ns       344.3uV    347.5uV    320.6uV
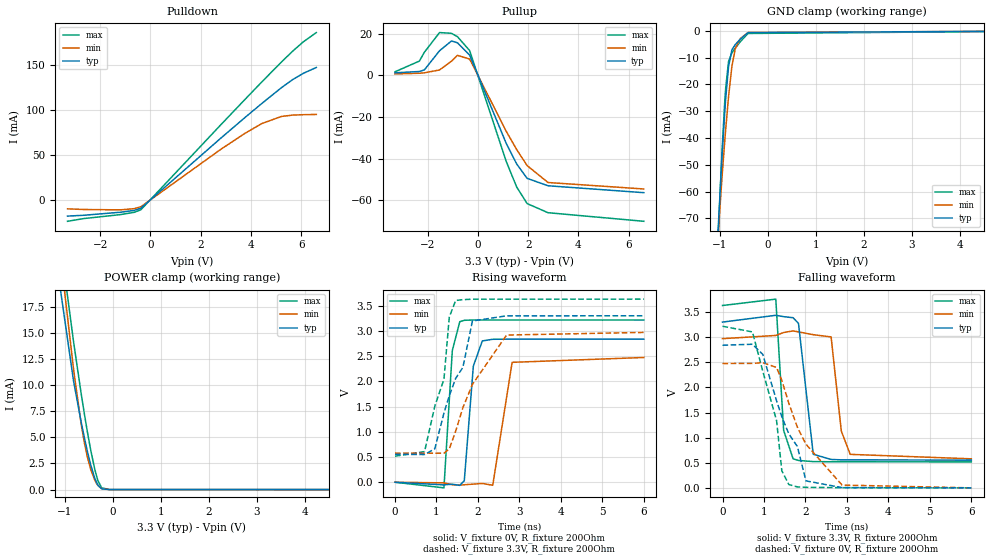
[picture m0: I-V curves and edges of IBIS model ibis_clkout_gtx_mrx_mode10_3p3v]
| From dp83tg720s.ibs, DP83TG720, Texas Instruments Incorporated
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| ibis_clkout_gtx_mrx_mode10_3p3v
[Model]   ibis_clkout_gtx_mrx_mode10_3p3v
Model_type   I/O
Polarity   Non-Inverting
Enable   Active-Low
Vinl = 0.99
Vinh = 2.31
Vmeas = 1.65
Vref = 1.65
Cref = 2pF
Rref = 100000
|   typ   min   max
C_comp   2.99pF   3.02pF   2.96pF
[Voltage Range]   3.3   2.97   3.63
[Temperature Range]   27   150   -40
[Pullup Reference]   3.3   2.97   3.63
[Pulldown Reference]   0   0   0
[Power Clamp Reference]   3.3   2.97   3.63
[GND Clamp Reference]   0   0   0
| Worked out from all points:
|   slope of the pulldown table from 0 to 0.495 V, typ, clamps not added: 40.2 ohm
|   slope of the pullup table from 0 to 0.495 V, typ, clamps not added: 32.8 ohm
|   GND clamp passes 1 mA (typ) near -0.44 V on its own axis
|   POWER clamp passes 1 mA (typ) near -0.37 V on its own axis
|   falling waveform, V_fixture 3.3V, R_fixture 200Ohm: 20-80 % time 147ps typ, 179ps min, 123ps max; typ from 3.3 V to 0.552 V
|   rising waveform, V_fixture 0V, R_fixture 200Ohm: 20-80 % time 155ps typ, 188ps min, 123ps max; typ from 0 V to 2.84 V
|   rising waveform, V_fixture 3.3V, R_fixture 200Ohm: 20-80 % time 621ps typ, 902ps min, 420ps max; typ from 0.552 V to 3.3 V
|   falling waveform, V_fixture 0V, R_fixture 200Ohm: 20-80 % time 748ps typ, 908ps min, 476ps max; typ from 2.84 V to 0 V
[Pulldown]
|   Voltage   I(typ)   I(min)   I(max)
-3.3V     -17.94mA   -9.855mA   -23.73mA
-2.656V   -17.02mA   -10.57mA   -20.7mA
-1.201V   -13.65mA   -10.99mA   -16.3mA
-646.8mV  -11.59mA   -9.655mA   -13.74mA
-379.5mV  -9.06mA    -7.476mA   -10.85mA
2.788V    68.63mA    56.25mA    83.47mA
3.759V    91.88mA    74.27mA    112mA
4.432V    107.6mA    85.19mA    131.6mA
5.214V    125.2mA    93.15mA    153.8mA
5.66V     134.2mA    94.62mA    165.9mA
6.085V    141.2mA    95.07mA    176.3mA
6.6V      147.7mA    95.36mA    186.6mA
[GND Clamp]
|   Voltage   I(typ)   I(min)   I(max)
-3.3V     -1.014A    -868.6mA   -1.13A
-1.063V   -85.1mA    -84.77mA   -89.5mA
-1.053V   -81.47mA   -81.9mA    -85.32mA
-953.7mV  -47.44mA   -55.17mA   -45.88mA
-894.3mV  -30.21mA   -41.06mA   -26.44mA
-874.5mV  -25.24mA   -36.68mA   -21.3mA
-815.1mV  -13.37mA   -24.58mA   -11.43mA
-745.8mV  -7.082mA   -13.32mA   -8.246mA
-676.5mV  -5.16mA    -6.725mA   -6.511mA
-567.6mV  -3.063mA   -2.829mA   -3.996mA
-409.2mV  -674.4uA   -648.8uA   -987.1uA
6.6V      0A         0A         0A
[Pullup]
|   Voltage   I(typ)   I(min)   I(max)
-3.3V     1.276mA    743.5uA    1.781mA
-2.33V    1.916mA    1.075mA    6.942mA
-2.132V   2.676mA    1.267mA    11.18mA
-1.528V   11.92mA    2.66mA     20.67mA
-1.053V   16.61mA    6.899mA    20.31mA
-815.1mV  15.75mA    9.683mA    18.69mA
-330mV    9.829mA    7.908mA    12mA
1.125V    -32.71mA   -26.88mA   -41.4mA
1.541V    -42.63mA   -35.68mA   -53.72mA
1.957V    -49.57mA   -43.41mA   -61.71mA
2.788V    -53.13mA   -51.56mA   -66.11mA
6.6V      -56.46mA   -54.68mA   -70.25mA
[POWER Clamp]
|   Voltage   I(typ)   I(min)   I(max)
-3.3V     318.6mA    237.7mA    401.3mA
-1.181V   22.09mA    26.08mA    26.87mA
-815.1mV  10.38mA    11.51mA    14.14mA
-656.7mV  6.467mA    6.258mA    9.187mA
-587.4mV  4.912mA    4.417mA    7.176mA
-528mV    3.676mA    3.125mA    5.551mA
-458.7mV  2.378mA    1.939mA    3.799mA
-369.6mV  1.034mA    857.9uA    1.869mA
-310.2mV  435.8uA    402.8uA    889.1uA
-231mV    77.41uA    103.3uA    169.7uA
-62.7mV   288.2nA    1.832uA    281.8nA
6.6V      0A         0A         0A
[Ramp]
R_load = 200
|   typ   min   max
dV/dt_r   1.70148/1.54545e-10   1.48367/1.86825e-10   1.92872/1.21991e-10
dV/dt_f   1.64878/1.4693e-10   1.43538/1.7826e-10   1.86829/1.22701e-10
[Falling Waveform]
V_fixture = 3.3V
V_fixture_min = 2.97V
V_fixture_max = 3.63V
R_fixture = 200Ohm
C_fixture = 0F
|   Time   V(typ)   V(min)   V(max)
0s        3.3V       2.97V      3.63V
1.285ns   3.435V     3.034V     3.757V
1.474ns   3.408V     3.092V     1.144V
1.702ns   3.387V     3.125V     578mV
1.832ns   3.275V     3.105V     545.7mV
2.188ns   669.1mV    3.049V     522.9mV
2.619ns   565.3mV    3.005V     519.7mV
2.865ns   557.8mV    1.13V      519.5mV
3.08ns    557.4mV    666.8mV    519.3mV
6ns       552.3mV    578mV      516.4mV
[Rising Waveform]
V_fixture = 0V
V_fixture_min = 0V
V_fixture_max = 0V
R_fixture = 200Ohm
C_fixture = 0F
|   Time   V(typ)   V(min)   V(max)
0s        1.843uV    21.79uV    840.8nV
1.18ns    -52.74mV   -12.73mV   -111.4mV
1.382ns   -38.54mV   -49.13mV   2.612V
1.562ns   -62.28mV   -56.45mV   3.183V
1.671ns   31.07mV    -49.94mV   3.21V
1.889ns   2.303V     -36.9mV    3.217V
2.105ns   2.801V     -24.02mV   3.217V
2.357ns   2.834V     -60.03mV   3.216V
2.824ns   2.837V     2.377V     3.216V
6ns       2.836V     2.473V     3.215V
[Rising Waveform]
V_fixture = 3.3V
V_fixture_min = 2.97V
V_fixture_max = 3.63V
R_fixture = 200Ohm
C_fixture = 0F
|   Time   V(typ)   V(min)   V(max)
0s        552.3mV    578mV      516.4mV
712.7ps   549.3mV    575.9mV    607.9mV
960.1ps   663.4mV    575.2mV    1.51V
1.18ns    1.372V     574.6mV    2.041V
1.309ns   1.715V     662.1mV    3.275V
1.463ns   2.059V     1.012V     3.603V
1.637ns   2.277V     1.479V     3.62V
1.867ns   3.197V     1.94V      3.629V
2.691ns   3.299V     2.918V     3.629V
6ns       3.3V       2.97V      3.63V
[Falling Waveform]
|Gnd
V_fixture = 0V
V_fixture_min = 0V
V_fixture_max = 0V
R_fixture = 200Ohm
C_fixture = 0F
|   Time   V(typ)   V(min)   V(max)
0s        2.839V     2.476V     3.217V
722.3ps   2.859V     2.477V     3.104V
971.1ps   2.656V     2.492V     2.322V
1.304ns   1.732V     2.396V     1.337V
1.43ns    1.414V     2.141V     341.5mV
1.6ns     1.074V     1.681V     65.28mV
1.804ns   825.2mV    1.211V     19.18mV
2.012ns   138.9mV    868.8mV    10.67mV
2.884ns   4.867mV    55.52mV    3.533mV
6ns       1.872uV    21.72uV    907.4nV
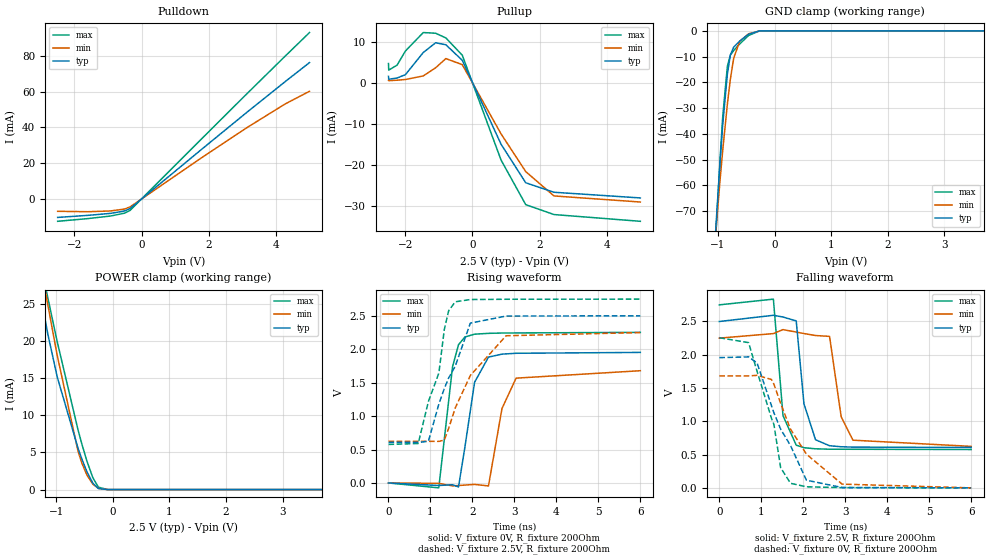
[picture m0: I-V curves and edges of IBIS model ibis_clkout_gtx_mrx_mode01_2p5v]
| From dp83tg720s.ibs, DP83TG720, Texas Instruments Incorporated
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| ibis_clkout_gtx_mrx_mode01_2p5v
[Model]   ibis_clkout_gtx_mrx_mode01_2p5v
Model_type   I/O
Polarity   Non-Inverting
Enable   Active-Low
Vinl = 0.75
Vinh = 1.75
Vmeas = 1.25
Vref = 1.25
Cref = 2pF
Rref = 100000
|   typ   min   max
C_comp   2.97pF   2.97pF   2.97pF
[Voltage Range]   2.5   2.25   2.75
[Temperature Range]   27   150   -40
[Pullup Reference]   2.5   2.25   2.75
[Pulldown Reference]   0   0   0
[Power Clamp Reference]   2.5   2.25   2.75
[GND Clamp Reference]   0   0   0
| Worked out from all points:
|   slope of the pulldown table from 0 to 0.375 V, typ, clamps not added: 64.1 ohm
|   slope of the pullup table from 0 to 0.375 V, typ, clamps not added: 54.5 ohm
|   GND clamp passes 1 mA (typ) near -0.44 V on its own axis
|   POWER clamp passes 1 mA (typ) near -0.37 V on its own axis
|   falling waveform, V_fixture 2.5V, R_fixture 200Ohm: 20-80 % time 206ps typ, 237ps min, 176ps max; typ from 2.5 V to 0.607 V
|   rising waveform, V_fixture 0V, R_fixture 200Ohm: 20-80 % time 286ps typ, 305ps min, 238ps max; typ from 0 V to 1.95 V
|   rising waveform, V_fixture 2.5V, R_fixture 200Ohm: 20-80 % time 661ps typ, 923ps min, 471ps max; typ from 0.607 V to 2.5 V
|   falling waveform, V_fixture 0V, R_fixture 200Ohm: 20-80 % time 797ps typ, 951ps min, 528ps max; typ from 1.96 V to 0 V
[Pulldown]
|   Voltage   I(typ)   I(min)   I(max)
-2.5V     -10.23mA   -6.816mA   -12.39mA
-1.6V     -9.074mA   -7.044mA   -10.88mA
-925mV    -7.971mA   -6.618mA   -9.445mA
-512.5mV  -6.662mA   -5.564mA   -7.877mA
-347.5mV  -5.301mA   -4.394mA   -6.366mA
1.798V    27.92mA    23.21mA    33.81mA
3.147V    48.58mA    39.98mA    58.96mA
4.28V     65.58mA    53.11mA    79.81mA
5V        76.13mA    60.13mA    92.88mA
[GND Clamp]
|   Voltage   I(typ)   I(min)   I(max)
-2.5V     -675.5mA   -580.7mA   -753.8mA
-1.097V   -98.09mA   -95.14mA   -104.4mA
-1.03V    -73.27mA   -75.43mA   -75.86mA
-962.5mV  -50.24mA   -57.38mA   -49.13mA
-917.5mV  -36.56mA   -46.4mA    -33.41mA
-835mV    -16.75mA   -28.44mA   -13.72mA
-782.5mV  -9.414mA   -18.8mA    -9.429mA
-722.5mV  -6.267mA   -10.55mA   -7.639mA
-617.5mV  -3.988mA   -4.105mA   -5.121mA
-460mV    -1.307mA   -1.167mA   -1.815mA
-265mV    -17.78uA   -43.66uA   -18.24uA
5V        0A         0A         0A
[Pullup]
|   Voltage   I(typ)   I(min)   I(max)
-2.5V     1.625mA    664.5uA    4.755mA
-2.493V   915.5uA    563.2uA    3.146mA
-2.245V   1.217mA    676.9uA    4.353mA
-1.998V   2.024mA    845.2uA    7.797mA
-1.465V   7.44mA     1.724mA    12.32mA
-1.097V   9.826mA    3.71mA     12.16mA
-790mV    9.332mA    5.96mA     11mA
-302.5mV  5.533mA    4.477mA    6.785mA
852.5mV   -14.97mA   -12.45mA   -18.84mA
1.587V    -24.39mA   -21.66mA   -29.74mA
2.428V    -26.71mA   -27.61mA   -32.16mA
5V        -28.1mA    -29.1mA    -33.81mA
[POWER Clamp]
|   Voltage   I(typ)   I(min)   I(max)
-2.5V     145mA      109.9mA    192.3mA
-1.42V    32.56mA    36.3mA     36.43mA
-1.248V   24.84mA    28.86mA    29.33mA
-1.15V    20.85mA    24.77mA    25.73mA
-985mV    15.14mA    18.03mA    19.87mA
-617.5mV  5.574mA    5.174mA    8.036mA
-550mV    4.122mA    3.573mA    6.141mA
-460mV    2.4mA      1.958mA    3.831mA
-355mV    861.1uA    726.2uA    1.6mA
-257.5mV  148.6uA    170.2uA    328.1uA
-92.5mV   988.3nA    4.331uA    1.237uA
5V        0A         0A         0A
[Ramp]
R_load = 200
|   typ   min   max
dV/dt_r   1.17157/2.83723e-10   1.00713/3.022e-10   1.35155/2.36075e-10
dV/dt_f   1.13593/2.02571e-10   0.975791/2.36662e-10   1.30427/1.73374e-10
[Falling Waveform]
V_fixture = 2.5V
V_fixture_min = 2.25V
V_fixture_max = 2.75V
R_fixture = 200Ohm
C_fixture = 0F
|   Time   V(typ)   V(min)   V(max)
0s        2.5V       2.25V      2.75V
1.288ns   2.593V     2.318V     2.836V
1.517ns   2.567V     2.378V     1.085V
1.832ns   2.509V     2.341V     641.4mV
2.017ns   1.261V     2.319V     603.3mV
2.292ns   722.7mV    2.289V     586.8mV
2.626ns   632.9mV    2.276V     580.7mV
2.904ns   617.7mV    1.066V     580.3mV
3.184ns   612.2mV    716.3mV    579.9mV
6ns       606.8mV    623.6mV    576.3mV
[Rising Waveform]
V_fixture = 0V
V_fixture_min = 0V
V_fixture_max = 0V
R_fixture = 200Ohm
C_fixture = 0F
|   Time   V(typ)   V(min)   V(max)
0s        2.665uV    32.51uV    1.124uV
1.198ns   -37.97mV   -5.978mV   -73.32mV
1.526ns   -26.25mV   -44.51mV   1.739V
1.668ns   -59.35mV   -38.27mV   2.068V
1.819ns   530.1mV    -31.62mV   2.183V
2.051ns   1.506V     -21.47mV   2.226V
2.382ns   1.883V     -44.67mV   2.238V
2.704ns   1.927V     1.114V     2.243V
3.04ns    1.94V      1.568V     2.244V
6ns       1.953V     1.679V     2.253V
[Rising Waveform]
V_fixture = 2.5V
V_fixture_min = 2.25V
V_fixture_max = 2.75V
R_fixture = 200Ohm
C_fixture = 0F
|   Time   V(typ)   V(min)   V(max)
0s        606.8mV    623.6mV    576.3mV
708.1ps   605.4mV    622.5mV    589.9mV
951.6ps   625.2mV    622.1mV    1.22V
1.2ns     1.18V      621.7mV    1.644V
1.33ns    1.412V     641.8mV    2.297V
1.433ns   1.57V      815.5mV    2.575V
1.59ns    1.746V     1.122V     2.71V
1.95ns    2.391V     1.608V     2.744V
2.802ns   2.497V     2.202V     2.748V
6ns       2.5V       2.25V      2.75V
[Falling Waveform]
|Gnd
V_fixture = 0V
V_fixture_min = 0V
V_fixture_max = 0V
R_fixture = 200Ohm
C_fixture = 0F
|   Time   V(typ)   V(min)   V(max)
0s        1.957V     1.682V     2.256V
697.7ps   1.968V     1.682V     2.182V
900.3ps   1.876V     1.691V     1.749V
1.242ns   1.235V     1.629V     1.046V
1.3ns     1.128V     1.559V     954.7mV
1.461ns   882.6mV    1.269V     303.3mV
1.696ns   635.5mV    882.1mV    68.76mV
2.075ns   115mV      506.1mV    15.89mV
2.925ns   4.989mV    55.97mV    3.501mV
6ns       2.708uV    32.52uV    1.191uV
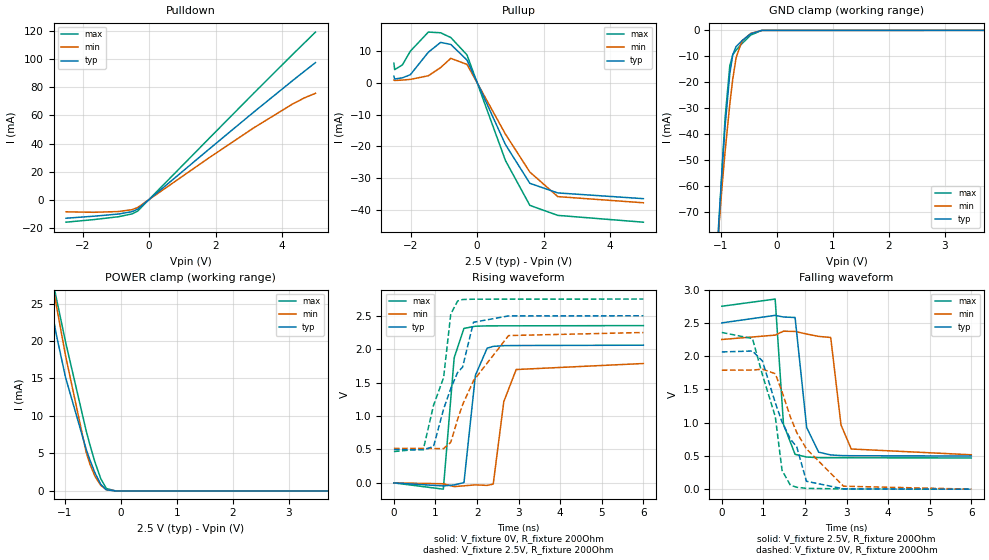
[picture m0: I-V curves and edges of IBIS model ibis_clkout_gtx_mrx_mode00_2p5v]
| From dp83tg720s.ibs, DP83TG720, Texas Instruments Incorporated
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| ibis_clkout_gtx_mrx_mode00_2p5v
[Model]   ibis_clkout_gtx_mrx_mode00_2p5v
Model_type   I/O
Polarity   Non-Inverting
Enable   Active-Low
Vinl = 0.75
Vinh = 1.75
Vmeas = 1.25
Vref = 1.25
Cref = 2pF
Rref = 100000
|   typ   min   max
C_comp   2.97pF   2.94pF   3pF
[Voltage Range]   2.5   2.25   2.75
[Temperature Range]   27   150   -40
[Pullup Reference]   2.5   2.25   2.75
[Pulldown Reference]   0   0   0
[Power Clamp Reference]   2.5   2.25   2.75
[GND Clamp Reference]   0   0   0
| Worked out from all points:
|   slope of the pulldown table from 0 to 0.375 V, typ, clamps not added: 49.8 ohm
|   slope of the pullup table from 0 to 0.375 V, typ, clamps not added: 42.1 ohm
|   GND clamp passes 1 mA (typ) near -0.44 V on its own axis
|   POWER clamp passes 1 mA (typ) near -0.37 V on its own axis
|   falling waveform, V_fixture 2.5V, R_fixture 200Ohm: 20-80 % time 168ps typ, 201ps min, 143ps max; typ from 2.5 V to 0.498 V
|   rising waveform, V_fixture 0V, R_fixture 200Ohm: 20-80 % time 212ps typ, 242ps min, 170ps max; typ from 0 V to 2.06 V
|   rising waveform, V_fixture 2.5V, R_fixture 200Ohm: 20-80 % time 646ps typ, 924ps min, 446ps max; typ from 0.498 V to 2.5 V
|   falling waveform, V_fixture 0V, R_fixture 200Ohm: 20-80 % time 755ps typ, 947ps min, 479ps max; typ from 2.06 V to 0 V
[Pulldown]
|   Voltage   I(typ)   I(min)   I(max)
-2.5V     -13.28mA   -8.715mA   -16.11mA
-1.667V   -11.85mA   -9.048mA   -14.26mA
-925mV    -10.3mA    -8.522mA   -12.22mA
-512.5mV  -8.594mA   -7.16mA    -10.18mA
-347.5mV  -6.829mA   -5.648mA   -8.211mA
1.798V    35.93mA    29.78mA    43.56mA
3.147V    62.48mA    51.22mA    75.94mA
4.303V    84.69mA    68.07mA    103.3mA
4.67V     91.6mA     72.6mA     111.8mA
5V        97.71mA    75.83mA    119.5mA
[GND Clamp]
|   Voltage   I(typ)   I(min)   I(max)
-2.5V     -675.5mA   -580.7mA   -753.8mA
-1.097V   -98.09mA   -95.14mA   -104.4mA
-1.03V    -73.27mA   -75.43mA   -75.86mA
-962.5mV  -50.24mA   -57.38mA   -49.13mA
-917.5mV  -36.56mA   -46.4mA    -33.41mA
-835mV    -16.75mA   -28.44mA   -13.72mA
-782.5mV  -9.414mA   -18.8mA    -9.429mA
-722.5mV  -6.267mA   -10.55mA   -7.639mA
-617.5mV  -3.988mA   -4.105mA   -5.121mA
-460mV    -1.307mA   -1.167mA   -1.815mA
-265mV    -17.78uA   -43.66uA   -18.24uA
5V        0A         0A         0A
[Pullup]
|   Voltage   I(typ)   I(min)   I(max)
-2.5V     2.104mA    859.6uA    6.16mA
-2.478V   1.201mA    737uA      4.151mA
-2.245V   1.576mA    876.5uA    5.635mA
-2.005V   2.569mA    1.086mA    9.972mA
-1.465V   9.629mA    2.229mA    15.96mA
-1.097V   12.72mA    4.794mA    15.75mA
-790mV    12.08mA    7.704mA    14.25mA
-302.5mV  7.165mA    5.797mA    8.787mA
852.5mV   -19.39mA   -16.12mA   -24.4mA
1.587V    -31.6mA    -28.06mA   -38.53mA
2.428V    -34.62mA   -35.78mA   -41.68mA
5V        -36.42mA   -37.71mA   -43.82mA
[POWER Clamp]
|   Voltage   I(typ)   I(min)   I(max)
-2.5V     145mA      109.9mA    192.3mA
-1.42V    32.56mA    36.3mA     36.43mA
-1.248V   24.84mA    28.86mA    29.33mA
-1.15V    20.85mA    24.77mA    25.73mA
-985mV    15.14mA    18.03mA    19.87mA
-617.5mV  5.574mA    5.174mA    8.036mA
-550mV    4.122mA    3.573mA    6.141mA
-460mV    2.4mA      1.958mA    3.831mA
-355mV    861.1uA    726.2uA    1.6mA
-257.5mV  148.6uA    170.2uA    328.1uA
-92.5mV   988.3nA    4.331uA    1.237uA
5V        0A         0A         0A
[Ramp]
R_load = 200
|   typ   min   max
dV/dt_r   1.23608/2.11374e-10   1.07172/2.40182e-10   1.41196/1.7022e-10
dV/dt_f   1.20115/1.67699e-10   1.03984/1.99816e-10   1.36866/1.41736e-10
[Falling Waveform]
V_fixture = 2.5V
V_fixture_min = 2.25V
V_fixture_max = 2.75V
R_fixture = 200Ohm
C_fixture = 0F
|   Time   V(typ)   V(min)   V(max)
0s        2.5V       2.25V      2.75V
1.283ns   2.613V     2.316V     2.858V
1.483ns   2.588V     2.375V     975.4mV
1.762ns   2.581V     2.371V     523.3mV
2.041ns   926.7mV    2.332V     483mV
2.329ns   555.8mV    2.297V     473.7mV
2.619ns   514.8mV    2.28V      472.2mV
2.867ns   505mV      964.6mV    471.9mV
3.113ns   502.7mV    603.8mV    471.7mV
6ns       498.2mV    517mV      469mV
[Rising Waveform]
V_fixture = 0V
V_fixture_min = 0V
V_fixture_max = 0V
R_fixture = 200Ohm
C_fixture = 0F
|   Time   V(typ)   V(min)   V(max)
0s        2.086uV    25.08uV    898.1nV
1.189ns   -45.6mV    -12.63mV   -93.45mV
1.449ns   -29.73mV   -55.2mV    1.87V
1.685ns   4.885mV    -43.37mV   2.311V
1.96ns    1.609V     -29.05mV   2.344V
2.242ns   2.015V     -37.06mV   2.349V
2.389ns   2.042V     -17.6mV    2.349V
2.643ns   2.053V     1.216V     2.35V
2.941ns   2.055V     1.696V     2.35V
6ns       2.06V      1.786V     2.353V
[Rising Waveform]
V_fixture = 2.5V
V_fixture_min = 2.25V
V_fixture_max = 2.75V
R_fixture = 200Ohm
C_fixture = 0F
|   Time   V(typ)   V(min)   V(max)
0s        498.2mV    517mV      469mV
711.8ps   495.2mV    515mV      511.5mV
953.5ps   545.2mV    514.3mV    1.162V
1.195ns   1.105V     513.5mV    1.574V
1.367ns   1.411V     607.5mV    2.525V
1.533ns   1.653V     952.4mV    2.721V
1.651ns   1.731V     1.168V     2.743V
1.914ns   2.403V     1.529V     2.748V
2.758ns   2.498V     2.204V     2.749V
6ns       2.5V       2.25V      2.75V
[Falling Waveform]
|Gnd
V_fixture = 0V
V_fixture_min = 0V
V_fixture_max = 0V
R_fixture = 200Ohm
C_fixture = 0F
|   Time   V(typ)   V(min)   V(max)
0s        2.063V     1.789V     2.356V
737.6ps   2.077V     1.79V      2.264V
976.5ps   1.927V     1.804V     1.719V
1.286ns   1.298V     1.736V     1.091V
1.448ns   1.01V      1.465V     282.7mV
1.649ns   751.6mV    1.086V     59.27mV
1.803ns   634.4mV    850.4mV    28.55mV
2.035ns   118.7mV    605.9mV    12.18mV
2.929ns   4.074mV    44.29mV    3.259mV
6ns       2.085uV    25.05uV    951.9nV
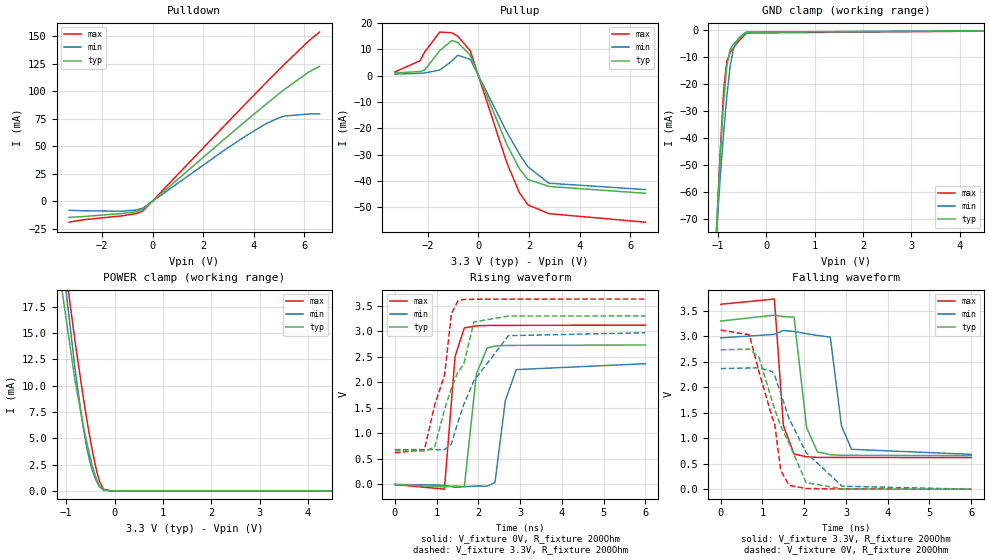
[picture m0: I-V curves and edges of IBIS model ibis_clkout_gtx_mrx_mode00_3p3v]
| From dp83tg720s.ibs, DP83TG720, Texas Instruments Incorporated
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| ibis_clkout_gtx_mrx_mode00_3p3v
[Model]   ibis_clkout_gtx_mrx_mode00_3p3v
Model_type   I/O
Polarity   Non-Inverting
Enable   Active-Low
Vinl = 0.99
Vinh = 2.31
Vmeas = 1.65
Vref = 1.65
Cref = 2pF
Rref = 100000
|   typ   min   max
C_comp   3.01pF   2.97pF   3.04pF
[Voltage Range]   3.3   2.97   3.63
[Temperature Range]   27   150   -40
[Pullup Reference]   3.3   2.97   3.63
[Pulldown Reference]   0   0   0
[Power Clamp Reference]   3.3   2.97   3.63
[GND Clamp Reference]   0   0   0
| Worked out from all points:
|   slope of the pulldown table from 0 to 0.495 V, typ, clamps not added: 49.8 ohm
|   slope of the pullup table from 0 to 0.495 V, typ, clamps not added: 41 ohm
|   GND clamp passes 1 mA (typ) near -0.44 V on its own axis
|   POWER clamp passes 1 mA (typ) near -0.37 V on its own axis
|   falling waveform, V_fixture 3.3V, R_fixture 200Ohm: 20-80 % time 171ps typ, 206ps min, 145ps max; typ from 3.3 V to 0.658 V
|   rising waveform, V_fixture 0V, R_fixture 200Ohm: 20-80 % time 205ps typ, 237ps min, 164ps max; typ from 0 V to 2.73 V
|   rising waveform, V_fixture 3.3V, R_fixture 200Ohm: 20-80 % time 638ps typ, 902ps min, 440ps max; typ from 0.658 V to 3.3 V
|   falling waveform, V_fixture 0V, R_fixture 200Ohm: 20-80 % time 789ps typ, 909ps min, 518ps max; typ from 2.73 V to 0 V
[Pulldown]
|   Voltage   I(typ)   I(min)   I(max)
-3.3V     -14.49mA   -8.072mA   -18.88mA
-2.775V   -13.84mA   -8.519mA   -16.8mA
-1.211V   -10.99mA   -8.89mA    -13.11mA
-636.9mV  -9.285mA   -7.755mA   -10.99mA
-379.5mV  -7.307mA   -6.043mA   -8.741mA
2.788V    55.47mA    45.63mA    67.36mA
3.769V    74.5mA     60.57mA    90.69mA
4.471V    87.88mA    70.25mA    107.2mA
4.996V    97.64mA    75.79mA    119.4mA
5.234V    101.9mA    77.44mA    124.8mA
6.174V    117.3mA    79.22mA    145.5mA
6.6V      122.4mA    79.43mA    153.5mA
[GND Clamp]
|   Voltage   I(typ)   I(min)   I(max)
-3.3V     -1.014A    -868.6mA   -1.13A
-1.063V   -85.1mA    -84.77mA   -89.5mA
-1.053V   -81.47mA   -81.9mA    -85.32mA
-953.7mV  -47.44mA   -55.17mA   -45.88mA
-894.3mV  -30.21mA   -41.06mA   -26.44mA
-874.5mV  -25.24mA   -36.68mA   -21.3mA
-815.1mV  -13.37mA   -24.58mA   -11.43mA
-745.8mV  -7.082mA   -13.32mA   -8.246mA
-676.5mV  -5.16mA    -6.725mA   -6.511mA
-567.6mV  -3.063mA   -2.829mA   -3.996mA
-409.2mV  -674.4uA   -648.8uA   -987.1uA
6.6V      0A         0A         0A
[Pullup]
|   Voltage   I(typ)   I(min)   I(max)
-3.3V     1.008mA    591.2uA    1.4mA
-2.31V    1.553mA    866.8uA    5.633mA
-2.122V   2.14mA     1.015mA    8.974mA
-1.528V   9.475mA    2.106mA    16.51mA
-1.053V   13.28mA    5.485mA    16.26mA
-815.1mV  12.6mA     7.732mA    14.96mA
-320.1mV  7.681mA    6.175mA    9.406mA
1.125V    -26.12mA   -21.47mA   -33.07mA
1.62V     -35.28mA   -29.72mA   -44.38mA
1.957V    -39.37mA   -34.59mA   -49.01mA
2.788V    -42.02mA   -40.8mA    -52.34mA
6.6V      -44.62mA   -43.21mA   -55.58mA
[POWER Clamp]
|   Voltage   I(typ)   I(min)   I(max)
-3.3V     318.6mA    237.7mA    401.3mA
-1.181V   22.09mA    26.08mA    26.87mA
-815.1mV  10.38mA    11.51mA    14.14mA
-656.7mV  6.467mA    6.258mA    9.187mA
-587.4mV  4.912mA    4.417mA    7.176mA
-528mV    3.676mA    3.125mA    5.551mA
-458.7mV  2.378mA    1.939mA    3.799mA
-369.6mV  1.034mA    857.9uA    1.869mA
-310.2mV  435.8uA    402.8uA    889.1uA
-231mV    77.41uA    103.3uA    169.7uA
-62.7mV   288.1nA    1.832uA    281.8nA
6.6V      0A         0A         0A
[Ramp]
R_load = 200
|   typ   min   max
dV/dt_r   1.63867/2.0433e-10   1.41894/2.34352e-10   1.87186/1.64153e-10
dV/dt_f   1.58534/1.7132e-10   1.37219/2.04272e-10   1.80651/1.44691e-10
[Falling Waveform]
V_fixture = 3.3V
V_fixture_min = 2.97V
V_fixture_max = 3.63V
R_fixture = 200Ohm
C_fixture = 0F
|   Time   V(typ)   V(min)   V(max)
0s        3.3V       2.97V      3.63V
1.286ns   3.417V     3.039V     3.732V
1.5ns     3.387V     3.114V     1.251V
1.756ns   3.378V     3.096V     691mV
2.056ns   1.214V     3.052V     635.9mV
2.316ns   733mV      3.018V     624.2mV
2.625ns   677.7mV    2.985V     623.2mV
2.892ns   664.3mV    1.243V     622.9mV
3.132ns   663.9mV    782.5mV    622.6mV
6ns       658mV      683.2mV    619.3mV
[Rising Waveform]
V_fixture = 0V
V_fixture_min = 0V
V_fixture_max = 0V
R_fixture = 200Ohm
C_fixture = 0F
|   Time   V(typ)   V(min)   V(max)
0s        1.718uV    26.89uV    1.075uV
1.186ns   -45.9mV    -12.71mV   -91.47mV
1.442ns   -30.23mV   -54.66mV   2.508V
1.664ns   -40.79mV   -44.36mV   3.066V
1.952ns   2.157V     -29.38mV   3.106V
2.209ns   2.673V     -30.49mV   3.113V
2.397ns   2.711V     36.54mV    3.114V
2.646ns   2.721V     1.643V     3.114V
2.907ns   2.723V     2.249V     3.115V
6ns       2.731V     2.365V     3.12V
[Rising Waveform]
V_fixture = 3.3V
V_fixture_min = 2.97V
V_fixture_max = 3.63V
R_fixture = 200Ohm
C_fixture = 0F
|   Time   V(typ)   V(min)   V(max)
0s        658mV      683.2mV    619.3mV
709ps     656.1mV    681.9mV    680.7mV
950.1ps   725.9mV    681.4mV    1.547V
1.191ns   1.471V     681mV      2.145V
1.352ns   1.882V     790.9mV    3.34V
1.509ns   2.201V     1.217V     3.593V
1.647ns   2.348V     1.561V     3.621V
1.894ns   3.181V     2.034V     3.627V
2.722ns   3.298V     2.914V     3.629V
6ns       3.3V       2.97V      3.63V
[Falling Waveform]
|Gnd
V_fixture = 0V
V_fixture_min = 0V
V_fixture_max = 0V
R_fixture = 200Ohm
C_fixture = 0F
|   Time   V(typ)   V(min)   V(max)
0s        2.735V     2.368V     3.123V
683.9ps   2.75V      2.379V     3.032V
918.7ps   2.585V     2.383V     2.3V
1.235ns   1.719V     2.306V     1.401V
1.294ns   1.566V     2.231V     1.276V
1.437ns   1.241V     1.886V     370.2mV
1.635ns   906.2mV    1.388V     75.18mV
2.044ns   129.8mV    721.2mV    13.21mV
2.907ns   5.095mV    57.87mV    4.024mV
6ns       2.249uV    26.95uV    1.151uV
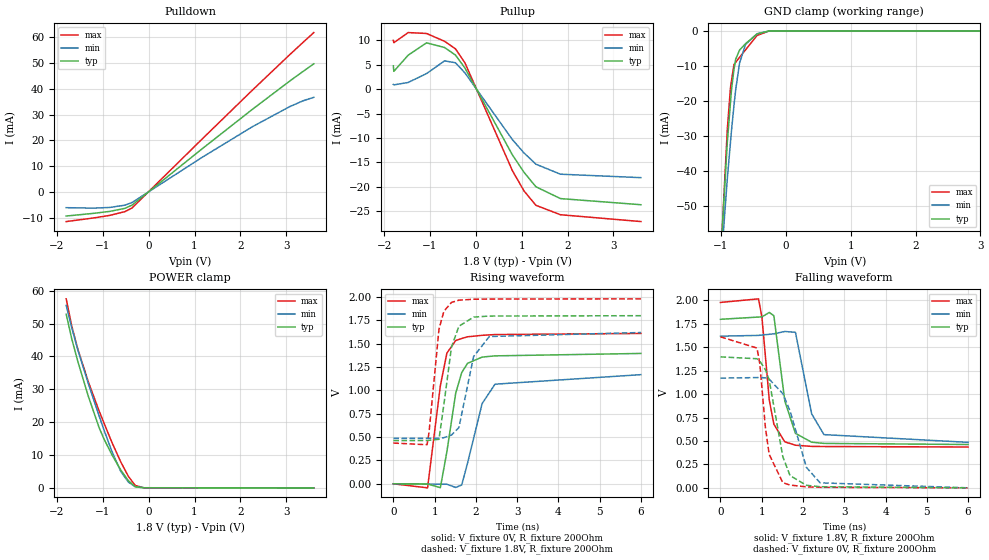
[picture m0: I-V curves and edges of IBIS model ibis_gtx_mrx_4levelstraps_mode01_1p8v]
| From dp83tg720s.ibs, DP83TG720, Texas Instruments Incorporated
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| ibis_gtx_mrx_4levelstraps_mode01_1p8v
[Model]   ibis_gtx_mrx_4levelstraps_mode01_1p8v
Model_type   I/O
Polarity   Non-Inverting
Enable   Active-Low
Vinl = 0.54
Vinh = 1.26
Vmeas = 0.9
Vref = 0.9
Cref = 2pF
Rref = 100000
|   typ   min   max
C_comp   2.5pF   2.47pF   2.53pF
[Voltage Range]   1.8   1.62   1.98
[Temperature Range]   27   150   -40
[Pullup Reference]   1.8   1.62   1.98
[Pulldown Reference]   0   0   0
[Power Clamp Reference]   1.8   1.62   1.98
[GND Clamp Reference]   0   0   0
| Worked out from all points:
|   slope of the pulldown table from 0 to 0.27 V, typ, clamps not added: 69.1 ohm
|   slope of the pullup table from 0 to 0.27 V, typ, clamps not added: 55.9 ohm
|   GND clamp passes 1 mA (typ) near -0.45 V on its own axis
|   POWER clamp passes 1 mA (typ) near -0.36 V on its own axis
|   falling waveform, V_fixture 1.8V, R_fixture 200Ohm: 20-80 % time 263ps typ, 327ps min, 222ps max; typ from 1.8 V to 0.463 V
|   rising waveform, V_fixture 0V, R_fixture 200Ohm: 20-80 % time 315ps typ, 424ps min, 274ps max; typ from 0 V to 1.4 V
|   rising waveform, V_fixture 1.8V, R_fixture 200Ohm: 20-80 % time 248ps typ, 329ps min, 207ps max; typ from 0.463 V to 1.8 V
|   falling waveform, V_fixture 0V, R_fixture 200Ohm: 20-80 % time 336ps typ, 493ps min, 234ps max; typ from 1.4 V to 0 V
[Pulldown]
|   Voltage   I(typ)   I(min)   I(max)
-1.8V     -9.394mA   -6.144mA   -11.54mA
-1.211V   -8.365mA   -6.324mA   -10.16mA
-855mV    -7.603mA   -6.065mA   -9.157mA
-520.2mV  -6.406mA   -5.184mA   -7.692mA
-363.6mV  -5.143mA   -4.14mA    -6.255mA
1.165V    16.73mA    13.42mA    20.53mA
2.261V    32.07mA    25.31mA    39.52mA
3.076V    43.05mA    33.12mA    53.31mA
3.368V    46.82mA    35.39mA    58.12mA
3.6V      49.74mA    36.73mA    61.88mA
[GND Clamp]
|   Voltage   I(typ)   I(min)   I(max)
-1.8V     -379.6mA   -329.3mA   -423.1mA
-1.017V   -67.63mA   -70.66mA   -69.46mA
-903.6mV  -31.87mA   -42.25mA   -28.2mA
-855mV    -20.54mA   -31.86mA   -16.22mA
-838.8mV  -16.76mA   -28.4mA    -14.23mA
-801mV    -11.03mA   -21.37mA   -9.591mA
-774mV    -8.085mA   -16.75mA   -8.964mA
-714.6mV  -5.501mA   -9.181mA   -7.586mA
-622.8mV  -3.665mA   -3.879mA   -5.456mA
-444.6mV  -924.3uA   -826.8uA   -1.321mA
-255.6mV  -12.26uA   -28.29uA   -12.59uA
3.6V      0A         0A         0A
[Pullup]
|   Voltage   I(typ)   I(min)   I(max)
-1.8V     4.808mA    1.002mA    10.03mA
-1.789V   3.678mA    897.7uA    9.542mA
-1.476V   6.991mA    1.393mA    11.62mA
-1.076V   9.515mA    3.213mA    11.44mA
-682.2mV  8.559mA    5.824mA    9.831mA
-444.6mV  7.008mA    5.431mA    8.283mA
-239.4mV  4.372mA    3.369mA    5.431mA
797.4mV   -13.47mA   -10.33mA   -16.7mA
1.051V    -17.04mA   -13.06mA   -20.85mA
1.31V     -19.99mA   -15.36mA   -23.79mA
1.845V    -22.41mA   -17.41mA   -25.72mA
3.6V      -23.67mA   -18.12mA   -27.12mA
[POWER Clamp]
|   Voltage   I(typ)   I(min)   I(max)
-1.8V     52.83mA    55.52mA    57.51mA
-1.681V   45.46mA    48.83mA    49.33mA
-1.546V   38.43mA    41.93mA    42.21mA
-1.319V   27.92mA    31.81mA    32.31mA
-1.082V   18.31mA    21.88mA    23.38mA
-979.2mV  14.97mA    17.75mA    19.83mA
-806.4mV  10.17mA    11.18mA    13.94mA
-612mV    5.477mA    5.044mA    7.945mA
-444.6mV  2.163mA    1.755mA    3.504mA
-293.4mV  350.1uA    334.1uA    708uA
-109.8mV  25.24uA    27.21uA    30.53uA
3.6V      0A         0A         0A
[Ramp]
R_load = 200
|   typ   min   max
dV/dt_r   0.836925/3.15194e-10   0.700464/4.21321e-10   0.965325/2.73093e-10
dV/dt_f   0.801907/2.59744e-10   0.679929/3.2471e-10   0.925865/2.19643e-10
[Falling Waveform]
V_fixture = 1.8V
V_fixture_min = 1.62V
V_fixture_max = 1.98V
R_fixture = 200Ohm
C_fixture = 0F
|   Time   V(typ)   V(min)   V(max)
0s        1.799V     1.619V     1.979V
922.6ps   1.823V     1.627V     2.017V
1.005ns   1.825V     1.631V     1.821V
1.183ns   1.872V     1.639V     937.3mV
1.294ns   1.837V     1.644V     679.1mV
1.56ns    925.5mV    1.669V     491.1mV
1.817ns   581.5mV    1.66V      455.1mV
2.21ns    487.2mV    789.3mV    442.6mV
2.508ns   474.4mV    568.2mV    441.1mV
6ns       462.6mV    485.8mV    435.9mV
[Rising Waveform]
V_fixture = 0V
V_fixture_min = 0V
V_fixture_max = 0V
R_fixture = 200Ohm
C_fixture = 0F
|   Time   V(typ)   V(min)   V(max)
0s        150.8uV    343.2uV    88.68uV
829.4ps   -2.273mV   -2.988mV   -43.33mV
1.14ns    -41.1mV    -4.236mV   1.051V
1.298ns   344.4mV    -4.869mV   1.398V
1.511ns   968mV      -39.08mV   1.533V
1.657ns   1.19V      -12.82mV   1.555V
1.797ns   1.289V     218.6mV    1.573V
2.152ns   1.356V     858.8mV    1.589V
2.464ns   1.369V     1.066V     1.597V
6ns       1.395V     1.168V     1.609V
[Rising Waveform]
V_fixture = 1.8V
V_fixture_min = 1.62V
V_fixture_max = 1.98V
R_fixture = 200Ohm
C_fixture = 0F
|   Time   V(typ)   V(min)   V(max)
0s        462.6mV    485.8mV    435.9mV
817ps     463.3mV    486.5mV    418.2mV
866.4ps   465.4mV    486.6mV    554.8mV
1.106ns   476.1mV    486.8mV    1.654V
1.226ns   851.1mV    493.8mV    1.847V
1.409ns   1.463V     521.1mV    1.941V
1.589ns   1.686V     602mV      1.965V
1.945ns   1.784V     1.361V     1.975V
2.326ns   1.795V     1.576V     1.977V
6ns       1.799V     1.619V     1.979V
[Falling Waveform]
|Gnd
V_fixture = 0V
V_fixture_min = 0V
V_fixture_max = 0V
R_fixture = 200Ohm
C_fixture = 0F
|   Time   V(typ)   V(min)   V(max)
0s        1.398V     1.171V     1.612V
884.8ps   1.378V     1.177V     1.492V
952.4ps   1.354V     1.178V     1.329V
1.089ns   1.261V     1.174V     644.1mV
1.18ns    1.153V     1.16V      358.4mV
1.511ns   333.3mV    1.005V     55.11mV
1.686ns   130.6mV    821.8mV    29.84mV
2.083ns   27.67mV    218.3mV    10.36mV
2.415ns   12.12mV    53.64mV    6.094mV
6ns       149uV      342.9uV    87.3uV
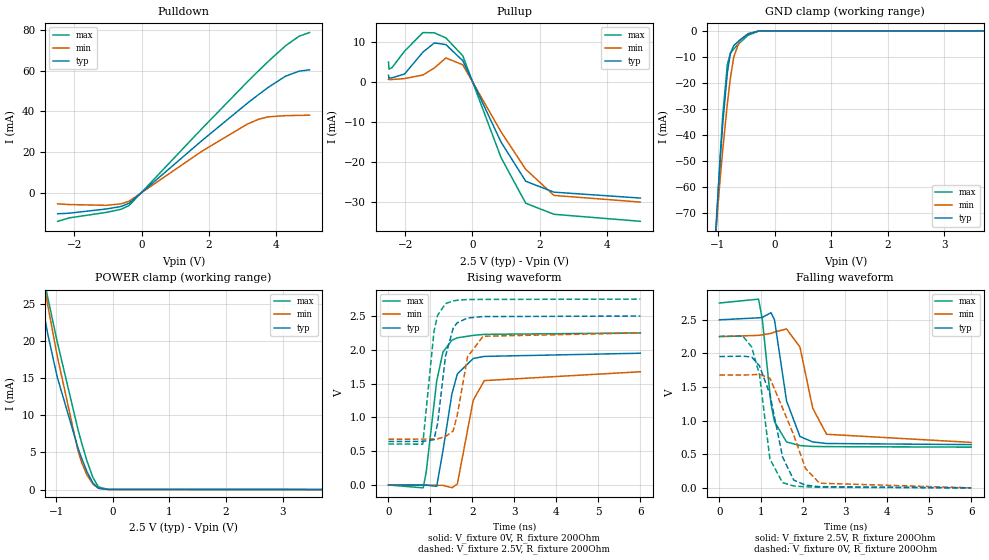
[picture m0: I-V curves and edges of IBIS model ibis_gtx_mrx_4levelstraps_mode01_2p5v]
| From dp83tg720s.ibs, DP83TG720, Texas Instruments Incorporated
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| ibis_gtx_mrx_4levelstraps_mode01_2p5v
[Model]   ibis_gtx_mrx_4levelstraps_mode01_2p5v
Model_type   I/O
Polarity   Non-Inverting
Enable   Active-Low
Vinl = 0.75
Vinh = 1.75
Vmeas = 1.25
Vref = 1.25
Cref = 2pF
Rref = 100000
|   typ   min   max
C_comp   2.49pF   2.46pF   2.52pF
[Voltage Range]   2.5   2.25   2.75
[Temperature Range]   27   150   -40
[Pullup Reference]   2.5   2.25   2.75
[Pulldown Reference]   0   0   0
[Power Clamp Reference]   2.5   2.25   2.75
[GND Clamp Reference]   0   0   0
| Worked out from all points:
|   slope of the pulldown table from 0 to 0.375 V, typ, clamps not added: 69.2 ohm
|   slope of the pullup table from 0 to 0.375 V, typ, clamps not added: 54.5 ohm
|   GND clamp passes 1 mA (typ) near -0.45 V on its own axis
|   POWER clamp passes 1 mA (typ) near -0.36 V on its own axis
|   falling waveform, V_fixture 2.5V, R_fixture 200Ohm: 20-80 % time 283ps typ, 356ps min, 238ps max; typ from 2.5 V to 0.643 V
|   rising waveform, V_fixture 0V, R_fixture 200Ohm: 20-80 % time 325ps typ, 326ps min, 275ps max; typ from 0 V to 1.95 V
|   rising waveform, V_fixture 2.5V, R_fixture 200Ohm: 20-80 % time 238ps typ, 279ps min, 197ps max; typ from 0.643 V to 2.5 V
|   falling waveform, V_fixture 0V, R_fixture 200Ohm: 20-80 % time 424ps typ, 602ps min, 274ps max; typ from 1.95 V to 0 V
[Pulldown]
|   Voltage   I(typ)   I(min)   I(max)
-2.5V     -10.43mA   -5.548mA   -14.13mA
-2.147V   -10.12mA   -5.882mA   -12.43mA
-1.052V   -8.054mA   -6.263mA   -9.745mA
-617.5mV  -6.858mA   -5.55mA    -8.231mA
-370mV    -5.221mA   -4.201mA   -6.338mA
1.798V    25.65mA    20.41mA    31.55mA
3.147V    43.98mA    33.72mA    54.49mA
3.485V    48.3mA     36.14mA    60.02mA
3.777V    51.89mA    37.33mA    64.7mA
4.287V    57.35mA    37.9mA     72.33mA
4.692V    59.82mA    38.04mA    77.04mA
5V        60.47mA    38.12mA    78.82mA
[GND Clamp]
|   Voltage   I(typ)   I(min)   I(max)
-2.5V     -677.3mA   -580.6mA   -757.7mA
-1.097V   -97.67mA   -94.67mA   -103.9mA
-1.03V    -72.76mA   -74.95mA   -75.14mA
-962.5mV  -49.65mA   -56.89mA   -48.25mA
-917.5mV  -35.92mA   -45.91mA   -32.49mA
-835mV    -16.09mA   -27.95mA   -12.9mA
-782.5mV  -8.787mA   -18.33mA   -8.679mA
-722.5mV  -5.711mA   -10.1mA    -6.977mA
-617.5mV  -3.571mA   -3.731mA   -4.617mA
-467.5mV  -1.208mA   -1.06mA    -1.687mA
-272.5mV  -19.58uA   -40.96uA   -21.97uA
5V        0A         0A         0A
[Pullup]
|   Voltage   I(typ)   I(min)   I(max)
-2.5V     1.678mA    673.1uA    4.967mA
-2.485V   937.3uA    573.3uA    3.2mA
-2.395V   1.029mA    611.1uA    3.563mA
-2.02V    1.986mA    839uA      7.704mA
-1.472V   7.46mA     1.735mA    12.32mA
-1.135V   9.733mA    3.491mA    12.25mA
-790mV    9.318mA    5.98mA     10.98mA
-287.5mV  5.294mA    4.281mA    6.516mA
852.5mV   -15.02mA   -12.47mA   -18.88mA
1.587V    -24.79mA   -21.81mA   -30.27mA
2.428V    -27.51mA   -28.32mA   -33.03mA
5V        -28.98mA   -29.98mA   -34.78mA
[POWER Clamp]
|   Voltage   I(typ)   I(min)   I(max)
-2.5V     144.7mA    109.6mA    192mA
-1.42V    32.48mA    36.17mA    36.41mA
-1.248V   24.8mA     28.76mA    29.34mA
-1.15V    20.83mA    24.69mA    25.75mA
-985mV    15.15mA    17.98mA    19.89mA
-617.5mV  5.606mA    5.192mA    8.079mA
-550mV    4.155mA    3.595mA    6.186mA
-460mV    2.433mA    1.982mA    3.876mA
-355mV    892.7uA    749.4uA    1.645mA
-257.5mV  177.5uA    191.2uA    370.1uA
-92.5mV   26.93uA    22.57uA    39.12uA
5V        0A         0A         0A
[Ramp]
R_load = 200
|   typ   min   max
dV/dt_r   1.16911/3.22058e-10   1.00462/3.22526e-10   1.34944/2.74653e-10
dV/dt_f   1.11339/2.80428e-10   0.943548/3.51876e-10   1.28571/2.35728e-10
[Falling Waveform]
V_fixture = 2.5V
V_fixture_min = 2.25V
V_fixture_max = 2.75V
R_fixture = 200Ohm
C_fixture = 0F
|   Time   V(typ)   V(min)   V(max)
0s        2.499V     2.249V     2.749V
935.1ps   2.529V     2.268V     2.807V
1.024ns   2.535V     2.277V     2.505V
1.23ns    2.605V     2.297V     1.254V
1.314ns   2.5V       2.317V     985.7mV
1.602ns   1.292V     2.364V     682.2mV
1.921ns   763.3mV    2.094V     629.4mV
2.225ns   683.3mV    1.185V     616.2mV
2.555ns   659.8mV    797.1mV    613.2mV
6ns       643.2mV    676.3mV    605.8mV
[Rising Waveform]
V_fixture = 0V
V_fixture_min = 0V
V_fixture_max = 0V
R_fixture = 200Ohm
C_fixture = 0F
|   Time   V(typ)   V(min)   V(max)
0s        182.1uV    406.9uV    105.8uV
827.2ps   -1.988mV   -2.959mV   -42.21mV
899.5ps   -2.177mV   -3.253mV   197.2mV
1.149ns   -18.8mV    -4.268mV   1.54V
1.298ns   509.1mV    -4.875mV   1.966V
1.511ns   1.348V     -40.6mV    2.142V
1.641ns   1.643V     15.64mV    2.177V
2.018ns   1.871V     1.252V     2.213V
2.282ns   1.902V     1.544V     2.228V
6ns       1.949V     1.675V     2.249V
[Rising Waveform]
V_fixture = 2.5V
V_fixture_min = 2.25V
V_fixture_max = 2.75V
R_fixture = 200Ohm
C_fixture = 0F
|   Time   V(typ)   V(min)   V(max)
0s        643.2mV    676.3mV    605.8mV
816.4ps   645.3mV    679mV      604.9mV
1.084ns   670.3mV    679.9mV    2.273V
1.17ns    909.9mV    682.7mV    2.509V
1.358ns   1.905V     716.5mV    2.682V
1.541ns   2.319V     799.8mV    2.723V
1.637ns   2.399V     1.03V      2.732V
1.884ns   2.47V      1.896V     2.743V
2.252ns   2.491V     2.2V       2.745V
6ns       2.499V     2.249V     2.749V
[Falling Waveform]
|Gnd
V_fixture = 0V
V_fixture_min = 0V
V_fixture_max = 0V
R_fixture = 200Ohm
C_fixture = 0F
|   Time   V(typ)   V(min)   V(max)
0s        1.953V     1.678V     2.253V
562.9ps   1.959V     1.678V     2.256V
770.7ps   1.946V     1.682V     2.095V
957.5ps   1.814V     1.689V     1.68V
1.205ns   1.393V     1.631V     428.2mV
1.506ns   461.3mV    1.187V     77.57mV
1.772ns   115.8mV    787.2mV    27.54mV
2.053ns   40.66mV    288.7mV    16.05mV
2.388ns   17.6mV     69.34mV    8.565mV
6ns       180.4uV    406.4uV    104.7uV
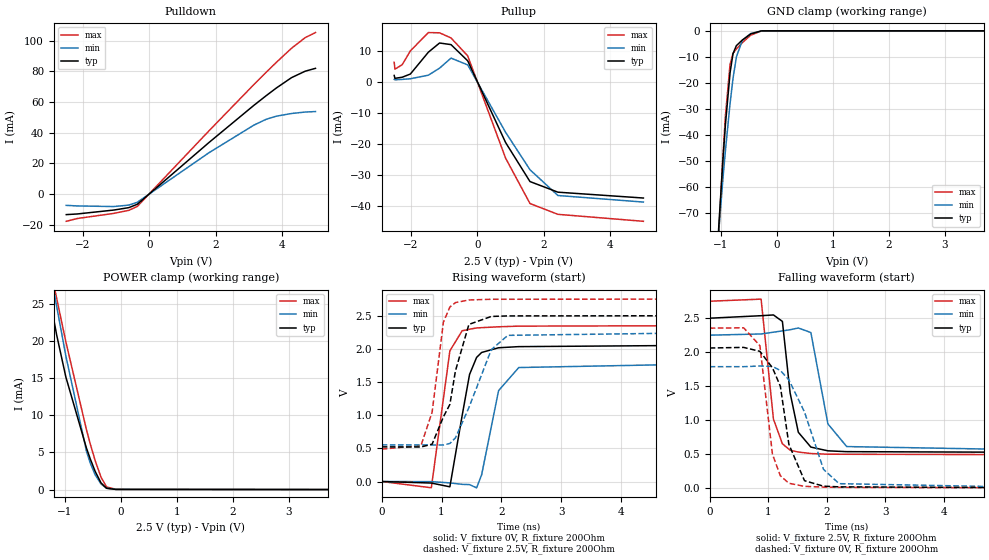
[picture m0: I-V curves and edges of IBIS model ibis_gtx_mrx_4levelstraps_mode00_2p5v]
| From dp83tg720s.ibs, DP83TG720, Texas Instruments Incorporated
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| ibis_gtx_mrx_4levelstraps_mode00_2p5v
[Model]   ibis_gtx_mrx_4levelstraps_mode00_2p5v
Model_type   I/O
Polarity   Non-Inverting
Enable   Active-Low
Vinl = 0.75
Vinh = 1.75
Vmeas = 1.25
Vref = 1.25
Cref = 2pF
Rref = 100000
|   typ   min   max
C_comp   2.5pF   2.45pF   2.55pF
[Voltage Range]   2.5   2.25   2.75
[Temperature Range]   27   150   -40
[Pullup Reference]   2.5   2.25   2.75
[Pulldown Reference]   0   0   0
[Power Clamp Reference]   2.5   2.25   2.75
[GND Clamp Reference]   0   0   0
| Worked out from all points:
|   slope of the pulldown table from 0 to 0.375 V, typ, clamps not added: 52.8 ohm
|   slope of the pullup table from 0 to 0.375 V, typ, clamps not added: 42.1 ohm
|   GND clamp passes 1 mA (typ) near -0.45 V on its own axis
|   POWER clamp passes 1 mA (typ) near -0.36 V on its own axis
|   falling waveform, V_fixture 2.5V, R_fixture 200Ohm: 20-80 % time 181ps typ, 217ps min, 156ps max; typ from 2.5 V to 0.522 V
|   rising waveform, V_fixture 0V, R_fixture 200Ohm: 20-80 % time 230ps typ, 252ps min, 188ps max; typ from 0 V to 2.06 V
|   rising waveform, V_fixture 2.5V, R_fixture 200Ohm: 20-80 % time 321ps typ, 447ps min, 193ps max; typ from 0.522 V to 2.5 V
|   falling waveform, V_fixture 0V, R_fixture 200Ohm: 20-80 % time 265ps typ, 460ps min, 173ps max; typ from 2.06 V to 0 V
[Pulldown]
|   Voltage   I(typ)   I(min)   I(max)
-2.5V     -13.49mA   -7.447mA   -17.85mA
-2.17V    -13.06mA   -7.815mA   -16.03mA
-1.067V   -10.5mA    -8.222mA   -12.67mA
-617.5mV  -8.928mA   -7.264mA   -10.69mA
-362.5mV  -6.716mA   -5.43mA    -8.145mA
1.798V    33.66mA    26.98mA    41.3mA
3.147V    57.88mA    44.96mA    71.47mA
3.515V    64.15mA    48.74mA    79.44mA
3.815V    69.08mA    50.77mA    85.79mA
4.28V     75.97mA    52.55mA    95.16mA
4.692V    80.18mA    53.5mA     102.1mA
5V        82.04mA    53.81mA    105.4mA
[GND Clamp]
|   Voltage   I(typ)   I(min)   I(max)
-2.5V     -677.3mA   -580.6mA   -757.7mA
-1.097V   -97.67mA   -94.67mA   -103.9mA
-1.03V    -72.76mA   -74.95mA   -75.14mA
-962.5mV  -49.65mA   -56.89mA   -48.25mA
-917.5mV  -35.92mA   -45.91mA   -32.49mA
-835mV    -16.09mA   -27.95mA   -12.9mA
-782.5mV  -8.787mA   -18.33mA   -8.679mA
-722.5mV  -5.711mA   -10.1mA    -6.977mA
-617.5mV  -3.571mA   -3.731mA   -4.617mA
-467.5mV  -1.208mA   -1.06mA    -1.687mA
-272.5mV  -19.58uA   -40.95uA   -21.97uA
5V        0A         0A         0A
[Pullup]
|   Voltage   I(typ)   I(min)   I(max)
-2.5V     2.157mA    868.3uA    6.373mA
-2.478V   1.216mA    744.3uA    4.172mA
-2.26V    1.571mA    875.1uA    5.61mA
-2.013V   2.607mA    1.09mA     10.05mA
-1.472V   9.629mA    2.234mA    15.95mA
-1.135V   12.59mA    4.492mA    15.87mA
-790mV    12.07mA    7.725mA    14.22mA
-287.5mV  6.857mA    5.545mA    8.444mA
852.5mV   -19.43mA   -16.14mA   -24.45mA
1.587V    -32mA      -28.2mA    -39.07mA
2.428V    -35.42mA   -36.49mA   -42.55mA
5V        -37.3mA    -38.6mA    -44.79mA
[POWER Clamp]
|   Voltage   I(typ)   I(min)   I(max)
-2.5V     144.7mA    109.6mA    192mA
-1.42V    32.48mA    36.17mA    36.41mA
-1.248V   24.8mA     28.76mA    29.34mA
-1.15V    20.83mA    24.69mA    25.75mA
-985mV    15.15mA    17.98mA    19.89mA
-617.5mV  5.606mA    5.192mA    8.079mA
-550mV    4.155mA    3.595mA    6.186mA
-460mV    2.433mA    1.982mA    3.876mA
-355mV    892.7uA    749.4uA    1.645mA
-257.5mV  177.5uA    191.2uA    370.1uA
-92.5mV   26.93uA    22.57uA    39.12uA
5V        0A         0A         0A
[Ramp]
R_load = 200
|   typ   min   max
dV/dt_r   1.23383/2.29221e-10   1.06927/2.49837e-10   1.41019/1.87718e-10
dV/dt_f   1.18608/1.79406e-10   1.01809/2.14612e-10   1.35638/1.55301e-10
[Falling Waveform]
V_fixture = 2.5V
V_fixture_min = 2.25V
V_fixture_max = 2.75V
R_fixture = 200Ohm
C_fixture = 0F
|   Time   V(typ)   V(min)   V(max)
0s        2.499V     2.249V     2.749V
878.5ps   2.536V     2.267V     2.78V
1.089ns   2.547V     2.293V     1.014V
1.242ns   2.452V     2.312V     649.1mV
1.374ns   1.397V     2.329V     554.8mV
1.514ns   818.8mV    2.355V     527.6mV
1.728ns   600.6mV    2.288V     506.1mV
2.019ns   545.5mV    942mV      495.7mV
2.34ns    533.3mV    608.3mV    494.9mV
6ns       522.3mV    552.3mV    488.3mV
[Rising Waveform]
V_fixture = 0V
V_fixture_min = 0V
V_fixture_max = 0V
R_fixture = 200Ohm
C_fixture = 0F
|   Time   V(typ)   V(min)   V(max)
0s        138.1uV    307.8uV    80.24uV
829.1ps   -22.73mV   -2.07mV    -94.15mV
1.139ns   -79.6mV    -20.79mV   1.969V
1.344ns   993.2mV    -42.33mV   2.272V
1.468ns   1.614V     -46.46mV   2.295V
1.586ns   1.871V     -95.47mV   2.315V
1.67ns    1.945V     101.8mV    2.319V
1.953ns   2.016V     1.37V      2.332V
2.291ns   2.033V     1.718V     2.342V
6ns       2.057V     1.782V     2.35V
[Rising Waveform]
V_fixture = 2.5V
V_fixture_min = 2.25V
V_fixture_max = 2.75V
R_fixture = 200Ohm
C_fixture = 0F
|   Time   V(typ)   V(min)   V(max)
0s        522.3mV    552.3mV    488.3mV
655.6ps   520.5mV    551.3mV    540.5mV
842.1ps   563mV      551mV      1.045V
1.031ns   975.3mV    550.7mV    2.402V
1.139ns   1.162V     573.9mV    2.63V
1.232ns   1.667V     657.3mV    2.697V
1.457ns   2.368V     1.114V     2.736V
1.831ns   2.488V     1.987V     2.747V
2.108ns   2.496V     2.203V     2.747V
6ns       2.499V     2.249V     2.749V
[Falling Waveform]
|Gnd
V_fixture = 0V
V_fixture_min = 0V
V_fixture_max = 0V
R_fixture = 200Ohm
C_fixture = 0F
|   Time   V(typ)   V(min)   V(max)
0s        2.06V      1.785V     2.353V
580.7ps   2.069V     1.785V     2.357V
857.9ps   2.011V     1.795V     2.094V
1.072ns   1.769V     1.788V     495.4mV
1.207ns   1.498V     1.729V     178.9mV
1.353ns   640.1mV    1.59V      67.73mV
1.62ns    105.4mV    1.116V     22.38mV
1.944ns   24.88mV    272.6mV    11.43mV
2.21ns    14.94mV    61.89mV    7.337mV
6ns       136.7uV    307.9uV    79.35uV
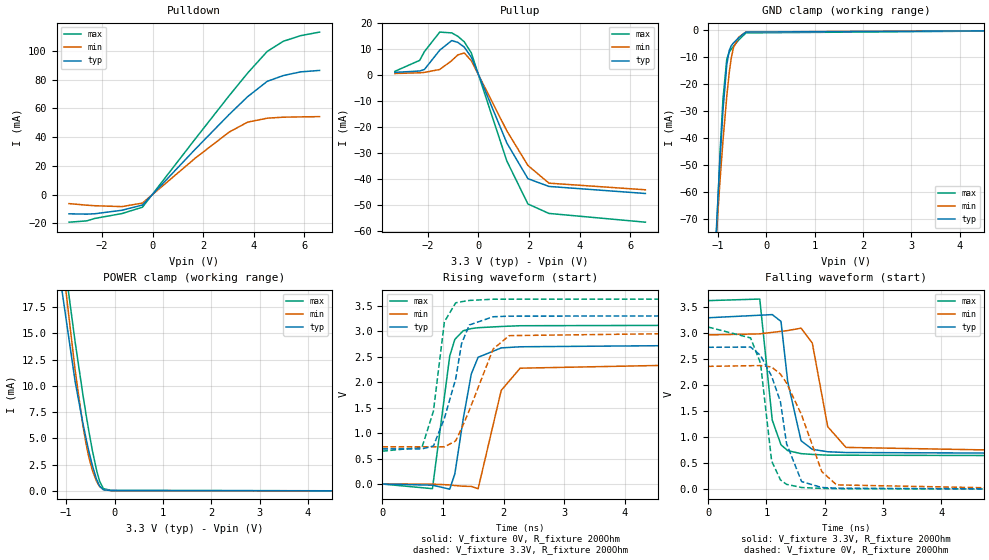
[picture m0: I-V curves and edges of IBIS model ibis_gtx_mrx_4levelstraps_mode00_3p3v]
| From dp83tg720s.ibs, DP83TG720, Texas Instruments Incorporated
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| ibis_gtx_mrx_4levelstraps_mode00_3p3v
[Model]   ibis_gtx_mrx_4levelstraps_mode00_3p3v
Model_type   I/O
Polarity   Non-Inverting
Enable   Active-Low
Vinl = 0.99
Vinh = 2.31
Vmeas = 1.65
Vref = 1.65
Cref = 2pF
Rref = 100000
|   typ   min   max
C_comp   2.5pF   2.45pF   2.53pF
[Voltage Range]   3.3   2.97   3.63
[Temperature Range]   27   150   -40
[Pullup Reference]   3.3   2.97   3.63
[Pulldown Reference]   0   0   0
[Power Clamp Reference]   3.3   2.97   3.63
[GND Clamp Reference]   0   0   0
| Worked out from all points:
|   slope of the pulldown table from 0 to 0.495 V, typ, clamps not added: 52.8 ohm
|   slope of the pullup table from 0 to 0.495 V, typ, clamps not added: 41.1 ohm
|   GND clamp passes 1 mA (typ) near -0.45 V on its own axis
|   POWER clamp passes 1 mA (typ) near -0.36 V on its own axis
|   falling waveform, V_fixture 3.3V, R_fixture 200Ohm: 20-80 % time 186ps typ, 225ps min, 157ps max; typ from 3.3 V to 0.69 V
|   rising waveform, V_fixture 0V, R_fixture 200Ohm: 20-80 % time 228ps typ, 251ps min, 186ps max; typ from 0 V to 2.73 V
|   rising waveform, V_fixture 3.3V, R_fixture 200Ohm: 20-80 % time 315ps typ, 441ps min, 200ps max; typ from 0.69 V to 3.3 V
|   falling waveform, V_fixture 0V, R_fixture 200Ohm: 20-80 % time 322ps typ, 493ps min, 188ps max; typ from 2.73 V to 0 V
[Pulldown]
|   Voltage   I(typ)   I(min)   I(max)
-3.3V     -13.32mA   -6.214mA   -19.15mA
-2.597V   -13.54mA   -7.325mA   -18.24mA
-2.29V    -13.29mA   -7.689mA   -16.56mA
-1.211V   -10.85mA   -8.305mA   -13.15mA
-399.3mV  -7.224mA   -5.844mA   -8.717mA
1.69V     31.67mA    25.43mA    38.85mA
3.026V    55.76mA    43.52mA    68.81mA
3.759V    68.17mA    50.47mA    84.61mA
4.531V    78.83mA    53.2mA     99.65mA
5.165V    82.85mA    53.9mA     106.7mA
5.848V    85.42mA    54.11mA    110.6mA
6.6V      86.43mA    54.28mA    113.1mA
[GND Clamp]
|   Voltage   I(typ)   I(min)   I(max)
-3.3V     -1.029A    -875.3mA   -1.153A
-1.063V   -85.35mA   -85.15mA   -89.45mA
-1.053V   -81.67mA   -82.25mA   -85.19mA
-953.7mV  -47.17mA   -55.29mA   -45.08mA
-894.3mV  -29.71mA   -41.04mA   -25.54mA
-815.1mV  -12.73mA   -24.4mA    -10.64mA
-765.6mV  -7.51mA    -15.86mA   -8.098mA
-726mV    -5.811mA   -10.61mA   -7.061mA
-676.5mV  -4.664mA   -6.37mA    -5.918mA
-567.6mV  -2.714mA   -2.512mA   -3.568mA
-419.1mV  -648.2uA   -603.7uA   -953.7uA
6.6V      0A         0A         0A
[Pullup]
|   Voltage   I(typ)   I(min)   I(max)
-3.3V     1.024mA    596.1uA    1.43mA
-2.32V    1.558mA    868.7uA    5.65mA
-2.132V   2.15mA     1.016mA    9.031mA
-1.528V   9.563mA    2.138mA    16.53mA
-1.053V   13.27mA    5.538mA    16.22mA
-815.1mV  12.58mA    7.751mA    14.93mA
-557.7mV  10.75mA    8.5mA      12.79mA
-280.5mV  6.871mA    5.515mA    8.509mA
1.125V    -26.16mA   -21.49mA   -33.1mA
1.957V    -39.88mA   -34.79mA   -49.62mA
2.788V    -42.87mA   -41.61mA   -53.26mA
6.6V      -45.58mA   -44.16mA   -56.63mA
[POWER Clamp]
|   Voltage   I(typ)   I(min)   I(max)
-3.3V     318.1mA    237.2mA    400.7mA
-1.181V   22.08mA    26mA       26.9mA
-815.1mV  10.41mA    11.5mA     14.19mA
-656.7mV  6.506mA    6.277mA    9.241mA
-587.4mV  4.953mA    4.443mA    7.232mA
-528mV    3.717mA    3.154mA    5.608mA
-458.7mV  2.419mA    1.969mA    3.857mA
-369.6mV  1.074mA    887uA      1.926mA
-310.2mV  474.3uA    430.6uA    944.6uA
-231mV    113.6uA    129.2uA    222.5uA
-72.6mV   34.18uA    26.12uA    49.79uA
6.6V      0A         0A         0A
[Ramp]
R_load = 200
|   typ   min   max
dV/dt_r   1.636/2.2781e-10   1.41587/2.4922e-10   1.86971/1.85671e-10
dV/dt_f   1.56525/1.8362e-10   1.343/2.22809e-10   1.7902/1.56046e-10
[Falling Waveform]
V_fixture = 3.3V
V_fixture_min = 2.97V
V_fixture_max = 3.63V
R_fixture = 200Ohm
C_fixture = 0F
|   Time   V(typ)   V(min)   V(max)
0s        3.299V     2.969V     3.629V
885ps     3.348V     2.989V     3.659V
1.099ns   3.36V      3.018V     1.329V
1.249ns   3.229V     3.037V     853.8mV
1.365ns   2.067V     3.053V     741.4mV
1.593ns   932.5mV    3.099V     684mV
1.786ns   767.4mV    2.814V     669.1mV
2.051ns   719.9mV    1.202V     654.8mV
2.364ns   705.3mV    803.9mV    653.7mV
6ns       690.1mV    730.6mV    645mV
[Rising Waveform]
V_fixture = 0V
V_fixture_min = 0V
V_fixture_max = 0V
R_fixture = 200Ohm
C_fixture = 0F
|   Time   V(typ)   V(min)   V(max)
0s        163.9uV    363.8uV    97.22uV
826ps     -22.27mV   -1.829mV   -90.74mV
1.111ns   -100.4mV   -16.78mV   2.511V
1.195ns   198.9mV    -29.57mV   2.838V
1.335ns   1.289V     -42.77mV   3.009V
1.467ns   2.161V     -46.11mV   3.05V
1.579ns   2.487V     -92.12mV   3.067V
1.96ns    2.671V     1.837V     3.091V
2.272ns   2.693V     2.273V     3.106V
6ns       2.727V     2.36V      3.116V
[Rising Waveform]
V_fixture = 3.3V
V_fixture_min = 2.97V
V_fixture_max = 3.63V
R_fixture = 200Ohm
C_fixture = 0F
|   Time   V(typ)   V(min)   V(max)
0s        690.1mV    730.6mV    645mV
653.5ps   689.5mV    730.2mV    720.2mV
842ps     746.1mV    730.1mV    1.428V
1.023ns   1.289V     730mV      3.183V
1.209ns   2.062V     846.3mV    3.555V
1.306ns   2.755V     1.09V      3.577V
1.434ns   3.121V     1.447V     3.602V
1.827ns   3.282V     2.65V      3.626V
2.093ns   3.294V     2.912V     3.626V
6ns       3.299V     2.969V     3.629V
[Falling Waveform]
|Gnd
V_fixture = 0V
V_fixture_min = 0V
V_fixture_max = 0V
R_fixture = 200Ohm
C_fixture = 0F
|   Time   V(typ)   V(min)   V(max)
0s        2.731V     2.364V     3.12V
727.5ps   2.735V     2.376V     2.911V
897.6ps   2.575V     2.379V     2.425V
1.088ns   2.176V     2.352V     543.7mV
1.24ns    1.681V     2.214V     178mV
1.345ns   873.3mV    2.041V     92.63mV
1.603ns   146mV      1.426V     31.69mV
1.948ns   32.37mV    339.9mV    15.28mV
2.203ns   19.35mV    82.53mV    9.725mV
6ns       162.7uV    363.4uV    96.23uV
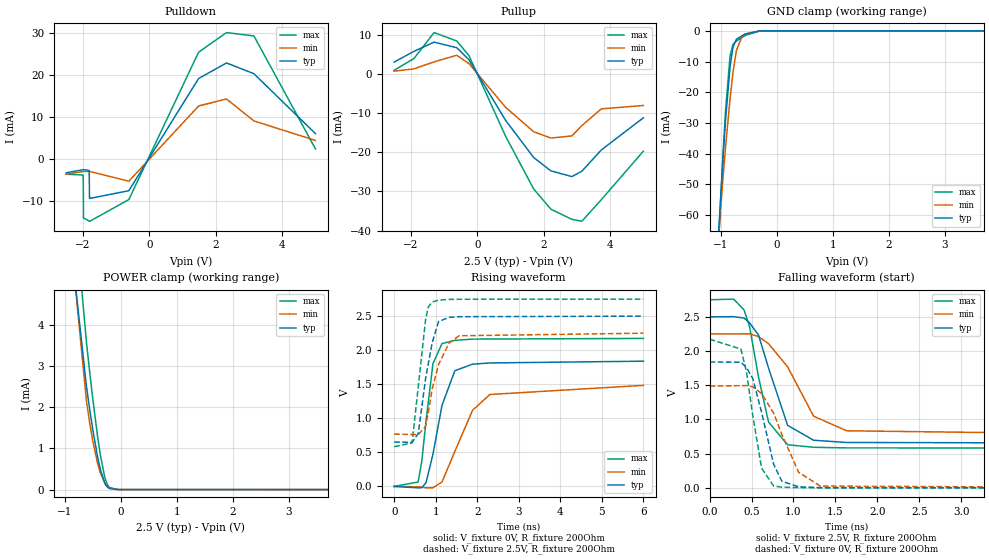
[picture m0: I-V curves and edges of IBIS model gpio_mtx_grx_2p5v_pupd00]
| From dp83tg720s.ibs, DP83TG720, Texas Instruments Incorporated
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[Model]   gpio_mtx_grx_2p5v_pupd00
Model_type   I/O
Polarity   Non-Inverting
Enable   Active-Low
Vinl = 0.75
Vinh = 1.75
Vmeas = 1.25
Vref = 0
Cref = 2pF
Rref = 100000
|   typ   min   max
C_comp   1.19pF   1.18pF   1.2pF
[Voltage Range]   2.5   2.25   2.75
[Temperature Range]   27   150   -40
[Pullup Reference]   2.5   2.25   2.75
[Pulldown Reference]   0   0   0
[Power Clamp Reference]   2.5   2.25   2.75
[GND Clamp Reference]   0   0   0
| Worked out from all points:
|   slope of the pulldown table from 0 to 0.375 V, typ, clamps not added: 69.3 ohm
|   slope of the pullup table from 0 to 0.375 V, typ, clamps not added: 69.5 ohm
|   GND clamp passes 1 mA (typ) near -0.55 V on its own axis
|   POWER clamp passes 1 mA (typ) near -0.45 V on its own axis
|   falling waveform, V_fixture 2.5V, R_fixture 200Ohm: 20-80 % time 264ps typ, 392ps min, 206ps max; typ from 2.5 V to 0.652 V
|   rising waveform, V_fixture 0V, R_fixture 200Ohm: 20-80 % time 362ps typ, 625ps min, 241ps max; typ from 0 V to 1.84 V
|   rising waveform, V_fixture 2.5V, R_fixture 200Ohm: 20-80 % time 290ps typ, 372ps min, 227ps max; typ from 0.652 V to 2.5 V
|   falling waveform, V_fixture 0V, R_fixture 200Ohm: 20-80 % time 208ps typ, 303ps min, 161ps max; typ from 1.84 V to 0 V
[Pulldown]
|   Voltage   I(typ)   I(min)   I(max)
-2.5V     -3.265mA   -3.621mA   -3.605mA
-1.998V   -2.547mA   -2.969mA   -3.806mA
-1.99V    -2.541mA   -2.964mA   -3.987mA
-1.982V   -2.535mA   -2.958mA   -14.07mA
-1.81V    -2.716mA   -2.945mA   -14.8mA
-1.802V   -9.363mA   -2.952mA   -14.82mA
-1.795V   -9.394mA   -2.961mA   -14.85mA
-617.5mV  -7.551mA   -5.289mA   -9.664mA
1.482V    19.21mA    12.66mA    25.49mA
2.322V    22.93mA    14.34mA    30.18mA
3.147V    20.37mA    9.1mA      29.38mA
5V        6.062mA    4.441mA    2.42mA
[GND Clamp]
|   Voltage   I(typ)   I(min)   I(max)
-2.5V     -617.6mA   -534.2mA   -680.9mA
-1.097V   -85.09mA   -82.87mA   -90.88mA
-1.038V   -64.99mA   -66.65mA   -67.92mA
-962.5mV  -41.7mA    -48.17mA   -40.89mA
-917.5mV  -29.37mA   -38.19mA   -26.44mA
-835mV    -11.67mA   -22.01mA   -8.061mA
-782.5mV  -5.215mA   -13.48mA   -4.415mA
-722.5mV  -2.757mA   -6.416mA   -3.35mA
-617.5mV  -1.543mA   -1.724mA   -2.076mA
-565mV    -1.09mA    -1.009mA   -1.503mA
-302.5mV  -17.01uA   -21.56uA   -25.06uA
5V        0A         0A         0A
[Pullup]
|   Voltage   I(typ)   I(min)   I(max)
-2.5V     3.036mA    720.5uA    942.2uA
-1.907V   5.772mA    1.297mA    3.93mA
-1.3V     8.128mA    3.091mA    10.57mA
-617.5mV  6.711mA    4.78mA     8.425mA
-250mV    3.626mA    2.646mA    4.708mA
852.5mV   -11.84mA   -8.504mA   -15.89mA
1.7V      -21.35mA   -14.76mA   -29.38mA
2.217V    -24.74mA   -16.36mA   -34.52mA
2.848V    -26.19mA   -15.81mA   -37.11mA
3.147V    -24.84mA   -13.2mA    -37.61mA
3.732V    -19.41mA   -8.91mA    -32.11mA
5V        -11.19mA   -8.043mA   -19.7mA
[POWER Clamp]
|   Voltage   I(typ)   I(min)   I(max)
-2.5V     97.49mA    60.51mA    150.3mA
-1.09V    8.414mA    8.774mA    10.77mA
-617.5mV  2.512mA    2.161mA    3.586mA
-565mV    2.004mA    1.67mA     2.925mA
-505mV    1.468mA    1.19mA     2.215mA
-422.5mV  826.1uA    666.4uA    1.335mA
-370mV    496.7uA    414.2uA    855.5uA
-287.5mV  151.9uA    151.4uA    292.8uA
-250mV    72.26uA    84.13uA    141.2uA
-205mV    25.22uA    37.45uA    46.37uA
-47.5mV   157nA      847.7nA    141.5nA
5V        0A         0A         0A
[Ramp]
R_load = 200
|   typ   min   max
dV/dt_r   1.10317/3.60703e-10   0.890452/6.21849e-10   1.30318/2.39113e-10
dV/dt_f   1.10849/2.62745e-10   0.889191/3.9141e-10   1.30009/2.05663e-10
[Falling Waveform]
V_fixture = 2.5V
V_fixture_min = 2.25V
V_fixture_max = 2.75V
R_fixture = 200Ohm
C_fixture = 0F
|   Time   V(typ)   V(min)   V(max)
0s        2.5V       2.25V      2.75V
286.6ps   2.503V     2.251V     2.759V
410.5ps   2.482V     2.252V     2.601V
476.8ps   2.411V     2.252V     2.354V
583.4ps   2.233V     2.211V     1.617V
702.5ps   1.752V     2.108V     962.1mV
929.8ps   914.8mV    1.77V      630.4mV
1.24ns    696.1mV    1.048V     593.5mV
1.635ns   663.7mV    834.7mV    584.3mV
6ns       652.4mV    767.8mV    583.1mV
[Rising Waveform]
V_fixture = 0V
V_fixture_min = 0V
V_fixture_max = 0V
R_fixture = 200Ohm
C_fixture = 0F
|   Time   V(typ)   V(min)   V(max)
0s        401uV      384.2uV    538uV
575.4ps   -20.78mV   -6.056mV   64.98mV
662.8ps   -18.94mV   -10.45mV   360.7mV
767.1ps   55.76mV    -20.39mV   966.5mV
933.4ps   474.4mV    -19.87mV   1.804V
1.151ns   1.191V     65.77mV    2.097V
1.461ns   1.699V     514.9mV    2.145V
1.887ns   1.795V     1.119V     2.163V
2.305ns   1.813V     1.35V      2.164V
6ns       1.839V     1.484V     2.173V
[Rising Waveform]
V_fixture = 2.5V
V_fixture_min = 2.25V
V_fixture_max = 2.75V
R_fixture = 200Ohm
C_fixture = 0F
|   Time   V(typ)   V(min)   V(max)
0s        652.4mV    767.8mV    583.1mV
431.5ps   646.9mV    762.5mV    639.7mV
579.5ps   777mV      760.7mV    1.466V
757.1ps   1.59V      883.7mV    2.456V
823.3ps   1.806V     1.098V     2.637V
915.6ps   2.112V     1.435V     2.708V
1.069ns   2.421V     1.791V     2.735V
1.321ns   2.482V     2.105V     2.746V
1.563ns   2.492V     2.212V     2.748V
6ns       2.5V       2.25V      2.75V
[Falling Waveform]
|Gnd
V_fixture = 0V
V_fixture_min = 0V
V_fixture_max = 0V
R_fixture = 200Ohm
C_fixture = 0F
|   Time   V(typ)   V(min)   V(max)
0s        1.84V      1.488V     2.173V
372.7ps   1.837V     1.494V     2.029V
438.3ps   1.761V     1.495V     1.702V
514.8ps   1.598V     1.478V     1.054V
619.1ps   1.107V     1.38V      289mV
763.8ps   343.5mV    1.092V     27.23mV
861ps     97.59mV    781.3mV    10.75mV
1.062ns   15.05mV    227.4mV    3.786mV
1.321ns   4.619mV    26.14mV    1.311mV
6ns       402.6uV    387.2uV    538.9uV
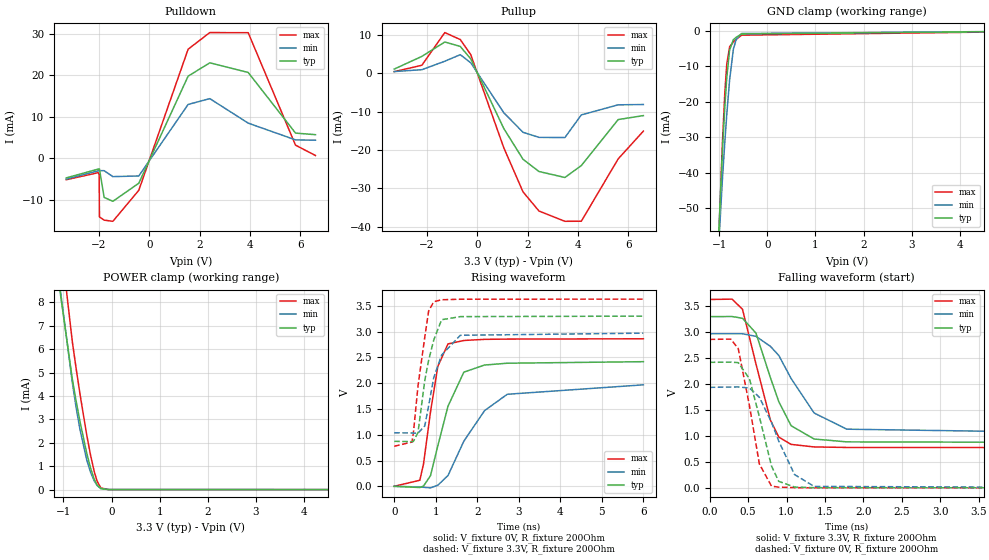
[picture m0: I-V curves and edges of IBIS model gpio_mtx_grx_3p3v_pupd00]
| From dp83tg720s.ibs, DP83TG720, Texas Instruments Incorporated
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[Model]   gpio_mtx_grx_3p3v_pupd00
Model_type   I/O
Polarity   Non-Inverting
Enable   Active-Low
Vinl = 0.99
Vinh = 2.31
Vmeas = 1.65
Vref = 0
Cref = 2pF
Rref = 100000
|   typ   min   max
C_comp   1.19pF   1.18pF   1.2pF
[Voltage Range]   3.3   2.97   3.63
[Temperature Range]   27   150   -40
[Pullup Reference]   3.3   2.97   3.63
[Pulldown Reference]   0   0   0
[Power Clamp Reference]   3.3   2.97   3.63
[GND Clamp Reference]   0   0   0
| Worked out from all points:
|   slope of the pulldown table from 0 to 0.495 V, typ, clamps not added: 69.8 ohm
|   slope of the pullup table from 0 to 0.495 V, typ, clamps not added: 70 ohm
|   GND clamp passes 1 mA (typ) near -0.55 V on its own axis
|   POWER clamp passes 1 mA (typ) near -0.45 V on its own axis
|   falling waveform, V_fixture 3.3V, R_fixture 200Ohm: 20-80 % time 343ps typ, 490ps min, 274ps max; typ from 3.3 V to 0.873 V
|   rising waveform, V_fixture 0V, R_fixture 200Ohm: 20-80 % time 496ps typ, 910ps min, 312ps max; typ from 0 V to 2.42 V
|   rising waveform, V_fixture 3.3V, R_fixture 200Ohm: 20-80 % time 320ps typ, 363ps min, 265ps max; typ from 0.873 V to 3.3 V
|   falling waveform, V_fixture 0V, R_fixture 200Ohm: 20-80 % time 238ps typ, 331ps min, 191ps max; typ from 2.42 V to 0 V
[Pulldown]
|   Voltage   I(typ)   I(min)   I(max)
-3.3V     -4.691mA   -4.982mA   -5.135mA
-2.033V   -2.58mA    -2.999mA   -3.442mA
-1.993V   -2.544mA   -2.966mA   -3.898mA
-1.983V   -2.536mA   -2.959mA   -14.07mA
-1.795V   -9.393mA   -2.96mA    -14.85mA
-1.449V   -10.32mA   -4.39mA    -15.13mA
-419.1mV  -5.983mA   -4.232mA   -7.676mA
1.541V    19.76mA    12.96mA    26.24mA
2.402V    22.97mA    14.36mA    30.24mA
3.927V    20.65mA    8.469mA    30.21mA
5.808V    6.077mA    4.441mA    3.172mA
6.6V      5.691mA    4.365mA    685.5uA
[GND Clamp]
|   Voltage   I(typ)   I(min)   I(max)
-3.3V     -930.6mA   -801.8mA   -1.027A
-1.132V   -96.96mA   -92.61mA   -104.3mA
-1.053V   -69.99mA   -70.65mA   -73.66mA
-1.043V   -66.73mA   -68.03mA   -69.92mA
-933.9mV  -33.68mA   -41.73mA   -31.47mA
-884.4mV  -21.41mA   -31.36mA   -17.43mA
-844.8mV  -13.36mA   -23.78mA   -9.447mA
-785.4mV  -5.447mA   -13.9mA    -4.502mA
-706.2mV  -2.49mA    -5.128mA   -3.139mA
-646.8mV  -1.818mA   -2.382mA   -2.415mA
-537.9mV  -877uA     -765.7uA   -1.229mA
6.6V      0A         0A         0A
[Pullup]
|   Voltage   I(typ)   I(min)   I(max)
-3.3V     1.091mA    447uA      427.8uA
-2.201V   4.405mA    938uA      2.088mA
-1.29V    8.16mA     3.141mA    10.62mA
-676.5mV  7.008mA    4.855mA    8.806mA
-260.7mV  3.771mA    2.752mA    4.883mA
1.056V    -14.43mA   -10.3mA    -19.46mA
1.818V    -22.43mA   -15.39mA   -30.93mA
2.452V    -25.62mA   -16.72mA   -35.93mA
3.482V    -27.18mA   -16.76mA   -38.61mA
4.135V    -24.07mA   -10.86mA   -38.59mA
5.6V      -12.07mA   -8.226mA   -22.32mA
6.6V      -11.04mA   -8.152mA   -15.09mA
[POWER Clamp]
|   Voltage   I(typ)   I(min)   I(max)
-3.3V     249.6mA    167.6mA    340.6mA
-1.28V    11.55mA    11.95mA    14.63mA
-815.1mV  4.721mA    4.572mA    6.321mA
-735.9mV  3.784mA    3.512mA    5.178mA
-656.7mV  2.914mA    2.572mA    4.098mA
-518.1mV  1.58mA     1.288mA    2.365mA
-438.9mV  942.9uA    758.3uA    1.499mA
-359.7mV  441.2uA    372.4uA    770.8uA
-300.3mV  189.8uA    181.4uA    360.8uA
-221.1mV  37.42uA    50.63uA    70.98uA
-52.8mV   196.2nA    1.014uA    184.3nA
6.6V      0A         0A         0A
[Ramp]
R_load = 200
|   typ   min   max
dV/dt_r   1.44974/4.9391e-10   1.18087/9.01534e-10   1.71628/3.1093e-10
dV/dt_f   1.45641/3.43482e-10   1.15867/4.87574e-10   1.71202/2.73424e-10
[Falling Waveform]
V_fixture = 3.3V
V_fixture_min = 2.97V
V_fixture_max = 3.63V
R_fixture = 200Ohm
C_fixture = 0F
|   Time   V(typ)   V(min)   V(max)
0s        3.3V       2.97V      3.63V
291.4ps   3.302V     2.97V      3.637V
427.2ps   3.268V     2.97V      3.442V
602.5ps   2.982V     2.92V      2.388V
791.3ps   2.121V     2.726V     1.304V
899.8ps   1.66V      2.551V     977.9mV
1.06ns    1.197V     2.107V     837.8mV
1.359ns   941.9mV    1.443V     789.1mV
1.783ns   886.3mV    1.131V     778.8mV
6ns       872.6mV    1.039V     776.6mV
[Rising Waveform]
V_fixture = 0V
V_fixture_min = 0V
V_fixture_max = 0V
R_fixture = 200Ohm
C_fixture = 0F
|   Time   V(typ)   V(min)   V(max)
0s        400.2uV    332.4uV    542.8uV
616.9ps   -23.23mV   -13.02mV   117.1mV
705.6ps   4.713mV    -18.88mV   432mV
873.9ps   206mV      -30mV      1.442V
1.051ns   787.3mV    21.92mV    2.327V
1.295ns   1.553V     209mV      2.761V
1.677ns   2.214V     875.8mV    2.828V
2.176ns   2.352V     1.468V     2.85V
2.723ns   2.387V     1.785V     2.855V
6ns       2.417V     1.968V     2.861V
[Rising Waveform]
V_fixture = 3.3V
V_fixture_min = 2.97V
V_fixture_max = 3.63V
R_fixture = 200Ohm
C_fixture = 0F
|   Time   V(typ)   V(min)   V(max)
0s        872.6mV    1.039V     776.6mV
427.2ps   866.8mV    1.033V     858.2mV
461.6ps   869.6mV    1.032V     1.03V
572.9ps   1.043V     1.031V     1.945V
736.5ps   2.054V     1.172V     2.893V
828.9ps   2.443V     1.561V     3.398V
951.5ps   2.835V     2.103V     3.579V
1.141ns   3.23V      2.545V     3.618V
1.592ns   3.291V     2.929V     3.628V
6ns       3.3V       2.97V      3.63V
[Falling Waveform]
|Gnd
V_fixture = 0V
V_fixture_min = 0V
V_fixture_max = 0V
R_fixture = 200Ohm
C_fixture = 0F
|   Time   V(typ)   V(min)   V(max)
0s        2.419V     1.937V     2.861V
274.7ps   2.423V     1.943V     2.867V
372.3ps   2.413V     1.945V     2.682V
518.3ps   2.1V       1.924V     1.578V
646.6ps   1.372V     1.746V     461.6mV
804.3ps   422.6mV    1.266V     34.26mV
898.2ps   126.8mV    902.1mV    13.65mV
1.105ns   15.42mV    255.6mV    4.478mV
1.359ns   4.22mV     28.76mV    1.091mV
6ns       402.7uV    357.2uV    543.9uV
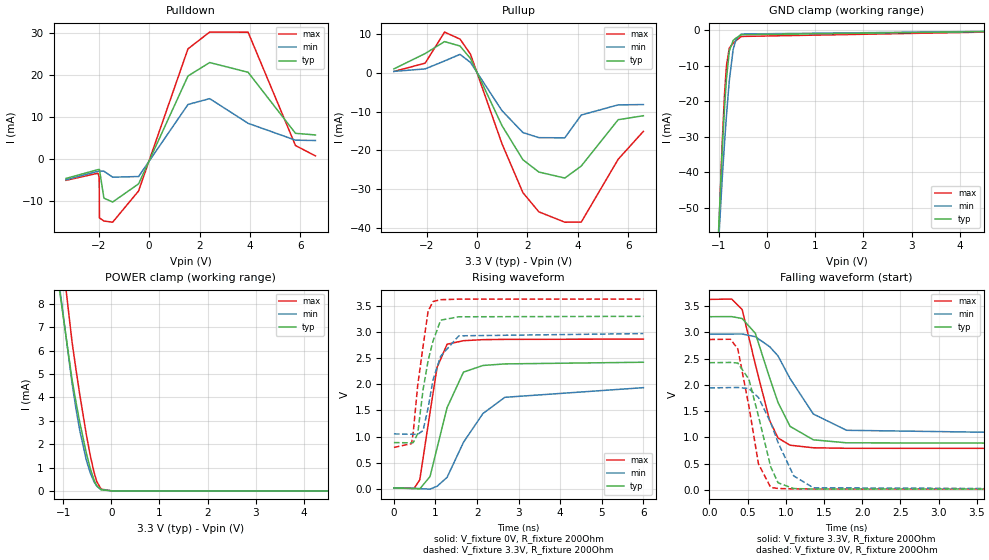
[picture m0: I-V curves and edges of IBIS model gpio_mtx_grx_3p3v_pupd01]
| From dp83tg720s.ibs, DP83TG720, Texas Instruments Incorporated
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[Model]   gpio_mtx_grx_3p3v_pupd01
Model_type   I/O
Polarity   Non-Inverting
Enable   Active-Low
Vinl = 0.99
Vinh = 2.31
Vmeas = 1.65
Vref = 0
Cref = 2pF
Rref = 100000
|   typ   min   max
C_comp   1.19pF   1.18pF   1.2pF
[Voltage Range]   3.3   2.97   3.63
[Temperature Range]   27   150   -40
[Pullup Reference]   3.3   2.97   3.63
[Pulldown Reference]   0   0   0
[Power Clamp Reference]   3.3   2.97   3.63
[GND Clamp Reference]   0   0   0
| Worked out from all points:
|   slope of the pulldown table from 0 to 0.495 V, typ, clamps not added: 69.8 ohm
|   slope of the pullup table from 0 to 0.495 V, typ, clamps not added: 70 ohm
|   GND clamp passes 1 mA (typ) near -0.50 V on its own axis
|   POWER clamp passes 1 mA (typ) near -0.44 V on its own axis
|   falling waveform, V_fixture 3.3V, R_fixture 200Ohm: 20-80 % time 343ps typ, 488ps min, 274ps max; typ from 3.3 V to 0.886 V
|   rising waveform, V_fixture 0V, R_fixture 200Ohm: 20-80 % time 488ps typ, 892ps min, 308ps max; typ from 0.017 V to 2.42 V
|   rising waveform, V_fixture 3.3V, R_fixture 200Ohm: 20-80 % time 314ps typ, 352ps min, 262ps max; typ from 0.886 V to 3.3 V
|   falling waveform, V_fixture 0V, R_fixture 200Ohm: 20-80 % time 237ps typ, 330ps min, 190ps max; typ from 2.42 V to 0.017 V
[Pulldown]
|   Voltage   I(typ)   I(min)   I(max)
-3.3V     -4.691mA   -4.982mA   -5.135mA
-2.033V   -2.58mA    -2.999mA   -3.442mA
-1.983V   -2.536mA   -2.959mA   -4.371mA
-1.973V   -2.529mA   -2.952mA   -14.12mA
-1.795V   -9.393mA   -2.96mA    -14.85mA
-1.449V   -10.32mA   -4.39mA    -15.13mA
-419.1mV  -5.983mA   -4.232mA   -7.676mA
1.541V    19.76mA    12.96mA    26.24mA
2.402V    22.97mA    14.36mA    30.24mA
3.927V    20.65mA    8.469mA    30.21mA
5.808V    6.077mA    4.441mA    3.172mA
6.6V      5.691mA    4.365mA    685.5uA
[GND Clamp]
|   Voltage   I(typ)   I(min)   I(max)
-3.3V     -931mA     -802.1mA   -1.028A
-1.132V   -97.33mA   -92.89mA   -104.8mA
-1.053V   -70.36mA   -70.93mA   -74.17mA
-1.043V   -67.1mA    -68.31mA   -70.42mA
-933.9mV  -34.05mA   -42.01mA   -31.98mA
-884.4mV  -21.78mA   -31.64mA   -17.94mA
-844.8mV  -13.73mA   -24.06mA   -9.949mA
-785.4mV  -5.817mA   -14.18mA   -5.005mA
-706.2mV  -2.86mA    -5.404mA   -3.64mA
-646.8mV  -2.187mA   -2.657mA   -2.915mA
-537.9mV  -1.244mA   -1.039mA   -1.726mA
6.6V      0A         0A         0A
[Pullup]
|   Voltage   I(typ)   I(min)   I(max)
-3.3V     1.091mA    447uA      427.8uA
-2.062V   5.059mA    1.084mA    2.568mA
-1.29V    8.16mA     3.141mA    10.62mA
-676.5mV  7.008mA    4.855mA    8.806mA
-260.7mV  3.771mA    2.752mA    4.883mA
986.7mV   -13.57mA   -9.711mA   -18.26mA
1.818V    -22.43mA   -15.39mA   -30.94mA
2.452V    -25.62mA   -16.72mA   -35.93mA
3.482V    -27.18mA   -16.76mA   -38.61mA
4.135V    -24.07mA   -10.86mA   -38.59mA
5.6V      -12.07mA   -8.226mA   -22.32mA
6.6V      -11.04mA   -8.152mA   -15.09mA
[POWER Clamp]
|   Voltage   I(typ)   I(min)   I(max)
-3.3V     249.7mA    167.6mA    340.7mA
-1.28V    11.59mA    11.98mA    14.68mA
-815.1mV  4.758mA    4.602mA    6.364mA
-735.9mV  3.82mA     3.542mA    5.22mA
-656.7mV  2.949mA    2.601mA    4.139mA
-518.1mV  1.613mA    1.314mA    2.403mA
-438.9mV  973.4uA    782.8uA    1.535mA
-359.7mV  469.2uA    394.8uA    803.7uA
-300.3mV  215.3uA    201.6uA    391.1uA
-211.2mV  49.32uA    57.92uA    79.16uA
16.5mV    0A         0A         0A
6.6V      0A         0A         0A
[Ramp]
R_load = 200
|   typ   min   max
dV/dt_r   1.44296/4.86097e-10   1.15216/8.8488e-10   1.70774/3.06847e-10
dV/dt_f   1.44838/3.42691e-10   1.15138/4.86224e-10   1.70266/2.72945e-10
[Falling Waveform]
V_fixture = 3.3V
V_fixture_min = 2.97V
V_fixture_max = 3.63V
R_fixture = 200Ohm
C_fixture = 0F
|   Time   V(typ)   V(min)   V(max)
0s        3.3V       2.97V      3.63V
292.5ps   3.302V     2.97V      3.636V
429.3ps   3.265V     2.971V     3.437V
602ps     2.984V     2.919V     2.392V
789.5ps   2.133V     2.729V     1.321V
899.1ps   1.666V     2.553V     990.3mV
1.057ns   1.211V     2.12V      852.9mV
1.361ns   955.8mV    1.447V     804mV
1.796ns   898.4mV    1.137V     794.3mV
6ns       886mV      1.051V     792.2mV
[Rising Waveform]
V_fixture = 0V
V_fixture_min = 0V
V_fixture_max = 0V
R_fixture = 200Ohm
C_fixture = 0F
|   Time   V(typ)   V(min)   V(max)
0s        16.78mV    15.83mV    18.99mV
484.8ps   7.214mV    12.21mV    8.691mV
622.4ps   62.27uV    5.528mV    174.6mV
869.1ps   237.1mV    -5.137mV   1.465V
1.039ns   786.1mV    51.12mV    2.325V
1.279ns   1.554V     221.3mV    2.766V
1.673ns   2.233V     890.3mV    2.834V
2.14ns    2.36V      1.44V      2.854V
2.667ns   2.39V      1.751V     2.859V
6ns       2.422V     1.936V     2.865V
[Rising Waveform]
V_fixture = 3.3V
V_fixture_min = 2.97V
V_fixture_max = 3.63V
R_fixture = 200Ohm
C_fixture = 0F
|   Time   V(typ)   V(min)   V(max)
0s        886mV      1.051V     792.2mV
423.4ps   880.4mV    1.045V     866mV
463.9ps   883.7mV    1.045V     1.071V
572.3ps   1.058V     1.043V     1.981V
701.5ps   1.896V     1.116V     2.728V
821.8ps   2.451V     1.545V     3.397V
940.4ps   2.827V     2.087V     3.582V
1.125ns   3.227V     2.539V     3.618V
1.562ns   3.291V     2.927V     3.628V
6ns       3.3V       2.97V      3.63V
[Falling Waveform]
|Gnd
V_fixture = 0V
V_fixture_min = 0V
V_fixture_max = 0V
R_fixture = 200Ohm
C_fixture = 0F
|   Time   V(typ)   V(min)   V(max)
0s        2.424V     1.944V     2.866V
275.8ps   2.429V     1.95V      2.871V
372.7ps   2.418V     1.952V     2.686V
517.8ps   2.108V     1.931V     1.593V
643.1ps   1.405V     1.761V     495.3mV
802.9ps   440.9mV    1.283V     49.04mV
899.8ps   136.6mV    902.6mV    28.23mV
1.104ns   27.91mV    269.2mV    21.46mV
1.361ns   18.7mV     41.87mV    18.82mV
6ns       16.78mV    15.83mV    18.99mV
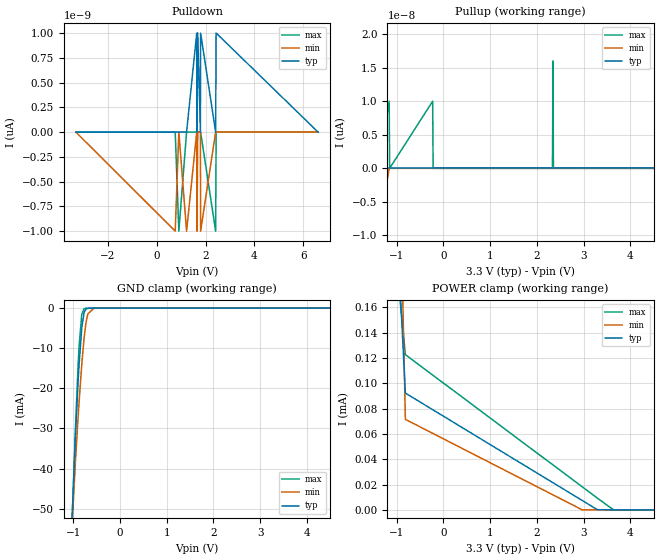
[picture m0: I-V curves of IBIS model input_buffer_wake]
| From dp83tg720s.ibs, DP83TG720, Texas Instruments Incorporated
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[Model]   input_buffer_wake
Model_type   Input
Vinl = 0.99
Vinh = 2.31
|   typ   min   max
C_comp   0.196pF   0.195pF   0.197pF
[Voltage Range]   3.3   2.97   3.63
[Temperature Range]   27   150   -40
[Power Clamp Reference]   3.3   2.97   3.63
[GND Clamp Reference]   0   0   0
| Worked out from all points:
|   GND clamp passes 1 mA (typ) near -0.76 V on its own axis
|   POWER clamp passes 1 mA (typ) near -1.70 V on its own axis
[Pulldown]
|   Voltage   I(typ)   I(min)   I(max)
-3.3V     0A         0A         0A
759mV     0A         -1fA       0A
907.5mV   0A         0A         -1fA
1.224V    0A         -1fA       0A
1.64V     1fA        0A         0A
1.65V     0A         -1fA       0A
1.68V     1fA        0A         0A
1.789V    0A         0A         0A
1.798V    1fA        -1fA       0A
2.412V    0A         0A         -1fA
2.432V    1fA        0A         0A
6.6V      0A         0A         0A
[GND Clamp]
|   Voltage   I(typ)   I(min)   I(max)
-3.3V     -849.9mA   -739.2mA   -927.9mA
-1.053V   -60.77mA   -61.08mA   -63.6mA
-1.043V   -57.75mA   -58.68mA   -60.17mA
-953.7mV  -32.37mA   -38.69mA   -30.8mA
-894.3mV  -18.26mA   -27.12mA   -14.23mA
-874.5mV  -14.25mA   -23.56mA   -9.757mA
-815.1mV  -4.863mA   -13.89mA   -1.521mA
-765.6mV  -1.078mA   -7.368mA   -155.9uA
-726mV    -237.9uA   -3.637mA   -38.31uA
-686.4mV  -57.39uA   -1.458mA   -21.67uA
-557.7mV  -12.7uA    -44.17uA   -15.38uA
6.6V      0A         0A         0A
[Pullup]
|   Voltage   I(typ)   I(min)   I(max)
-3.3V     0A         0A         20pA
-3.29V    0A         0A         0A
-1.399V   0A         0A         0A
-1.389V   0A         -10fA      0A
-1.162V   0A         0A         10fA
-1.152V   0A         0A         0A
-231mV    0A         0A         10fA
-221.1mV  0A         0A         0A
2.333V    0A         0A         0A
2.343V    0A         0A         16fA
2.353V    0A         0A         0A
6.6V      0A         0A         0A
[POWER Clamp]
|   Voltage   I(typ)   I(min)   I(max)
-3.3V     193mA      118.3mA    257.8mA
-1.676V   725uA      1.542mA    446.3uA
-815.1mV  92.24uA    71.48uA    122.6uA
2.967V    7.459uA    49.78nA    18.28uA
3.293V    135.8nA    0A         9.272uA
3.64V     0A         0A         0A
6.6V      0A         0A         0A
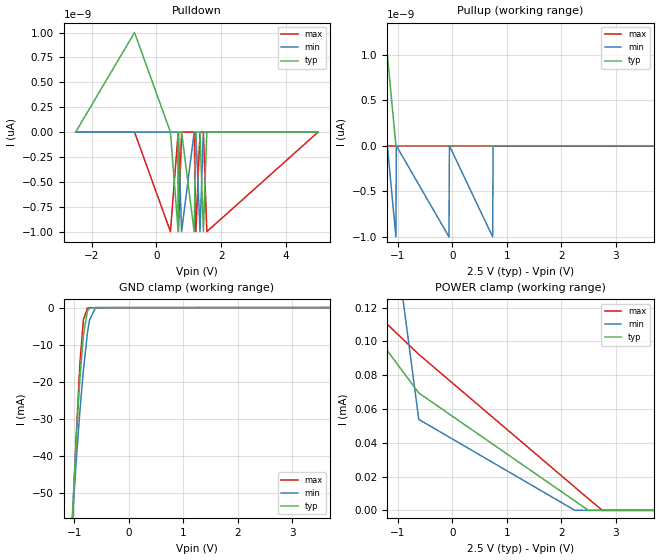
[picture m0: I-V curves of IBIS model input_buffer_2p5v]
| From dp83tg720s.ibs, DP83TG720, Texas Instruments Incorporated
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[Model]   input_buffer_2p5v
Model_type   Input
Vinl = 0.75
Vinh = 1.75
|   typ   min   max
C_comp   0.4pF   0.39pF   0.41pF
[Voltage Range]   2.5   2.25   2.75
[Temperature Range]   27   150   -40
[Power Clamp Reference]   2.5   2.25   2.75
[GND Clamp Reference]   0   0   0
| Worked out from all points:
|   GND clamp passes 1 mA (typ) near -0.76 V on its own axis
|   POWER clamp passes 1 mA (typ) near -1.70 V on its own axis
[Pulldown]
|   Voltage   I(typ)   I(min)   I(max)
-2.5V     0A         0A         0A
-677.5mV  1fA        0A         0A
432.5mV   0A         0A         -1fA
672.5mV   -1fA       0A         0A
680mV     0A         0A         -1fA
777.5mV   0A         -1fA       0A
1.167V    -1fA       0A         0A
1.22V     0A         0A         -1fA
1.347V    0A         -1fA       0A
1.452V    -1fA       0A         0A
1.558V    0A         0A         -1fA
5V        0A         0A         0A
[GND Clamp]
|   Voltage   I(typ)   I(min)   I(max)
-2.5V     -563.5mA   -490.8mA   -615.7mA
-1.097V   -74.74mA   -72.32mA   -79.4mA
-1.03V    -53.89mA   -55.62mA   -55.77mA
-970mV    -36.71mA   -42.11mA   -35.89mA
-917.5mV  -23.43mA   -31.47mA   -20.24mA
-895mV    -18.41mA   -27.24mA   -14.4mA
-835mV    -7.498mA   -16.94mA   -3.293mA
-760mV    -878.3uA   -6.749mA   -122.1uA
-722.5mV  -207.8uA   -3.382mA   -35.21uA
-617.5mV  -16.1uA    -217.6uA   -17.07uA
-565mV    -12.87uA   -52.65uA   -15.51uA
5V        0A         0A         0A
[Pullup]
|   Voltage   I(typ)   I(min)   I(max)
-2.5V     1pA        0A         0A
-2.493V   0A         0A         0A
-1.337V   1fA        0A         0A
-1.292V   0A         -1fA       0A
-1.195V   1fA        0A         0A
-1.038V   0A         -1fA       0A
-1.03V    0A         0A         0A
-62.5mV   0A         -1fA       0A
-55mV     0A         0A         0A
740mV     0A         -1fA       0A
747.5mV   0A         0A         0A
5V        0A         0A         0A
[POWER Clamp]
|   Voltage   I(typ)   I(min)   I(max)
-2.5V     59.67mA    26.33mA    96.4mA
-1.623V   365uA      1.022mA    212.7uA
-1.472V   106.5uA    262.8uA    118.6uA
-617.5mV  69.47uA    53.83uA    92.34uA
2.248V    5.624uA    43.31nA    13.78uA
2.495V    108.1nA    0A         6.989uA
2.757V    0A         0A         0A
5V        0A         0A         0A
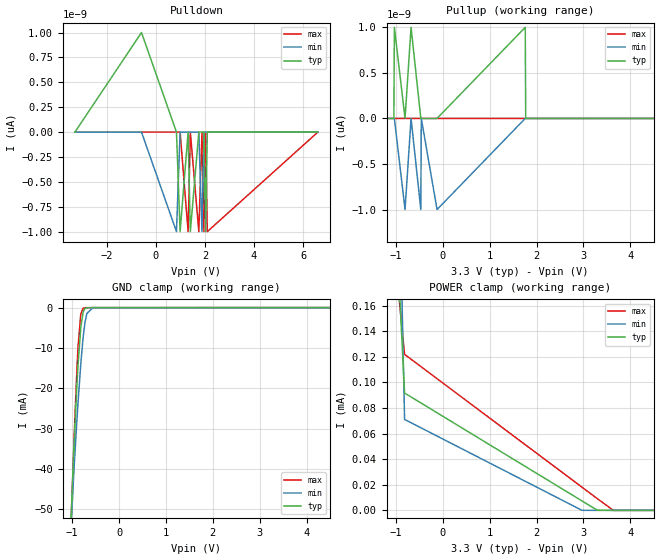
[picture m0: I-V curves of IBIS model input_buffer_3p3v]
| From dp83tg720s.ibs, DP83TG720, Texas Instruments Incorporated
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[Model]   input_buffer_3p3v
Model_type   Input
Vinl = 0.99
Vinh = 2.31
|   typ   min   max
C_comp   0.4pF   0.39pF   0.41pF
[Voltage Range]   3.3   2.97   3.63
[Temperature Range]   27   150   -40
[Power Clamp Reference]   3.3   2.97   3.63
[GND Clamp Reference]   0   0   0
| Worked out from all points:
|   GND clamp passes 1 mA (typ) near -0.76 V on its own axis
|   POWER clamp passes 1 mA (typ) near -1.70 V on its own axis
[Pulldown]
|   Voltage   I(typ)   I(min)   I(max)
-3.3V     0A         0A         0A
-587.4mV  1fA        0A         0A
838.2mV   0A         -1fA       0A
986.7mV   -1fA       0A         0A
1.313V    0A         0A         -1fA
1.403V    -1fA       0A         0A
1.749V    0A         0A         -1fA
1.878V    0A         -1fA       0A
1.957V    0A         0A         -1fA
2.026V    -1fA       0A         0A
2.095V    0A         0A         -1fA
6.6V      0A         0A         0A
[GND Clamp]
|   Voltage   I(typ)   I(min)   I(max)
-3.3V     -849.9mA   -739.2mA   -927.9mA
-1.053V   -60.77mA   -61.08mA   -63.6mA
-1.043V   -57.75mA   -58.68mA   -60.17mA
-953.7mV  -32.37mA   -38.69mA   -30.8mA
-894.3mV  -18.26mA   -27.12mA   -14.23mA
-874.5mV  -14.25mA   -23.56mA   -9.756mA
-815.1mV  -4.863mA   -13.89mA   -1.521mA
-765.6mV  -1.078mA   -7.368mA   -155.8uA
-726mV    -237.8uA   -3.636mA   -38.2uA
-686.4mV  -57.31uA   -1.457mA   -21.57uA
-557.7mV  -12.63uA   -44.12uA   -15.3uA
6.6V      0A         0A         0A
[Pullup]
|   Voltage   I(typ)   I(min)   I(max)
-3.3V     0A         0A         -10pA
-3.29V    0A         0A         0A
-1.043V   0A         0A         0A
-1.033V   1fA        0A         0A
-805.2mV  0A         -1fA       0A
-676.5mV  1fA        0A         0A
-468.6mV  0A         -1fA       0A
-458.7mV  0A         0A         0A
-122.1mV  0A         -1fA       0A
1.759V    1fA        0A         0A
1.769V    0A         0A         0A
6.6V      0A         0A         0A
[POWER Clamp]
|   Voltage   I(typ)   I(min)   I(max)
-3.3V     193mA      118.3mA    257.8mA
-1.676V   724.3uA    1.541mA    445.5uA
-815.1mV  91.7uA     71.07uA    121.9uA
2.967V    7.424uA    57.19nA    18.18uA
3.293V    142.7nA    0A         9.226uA
3.64V     0A         0A         0A
6.6V      0A         0A         0A
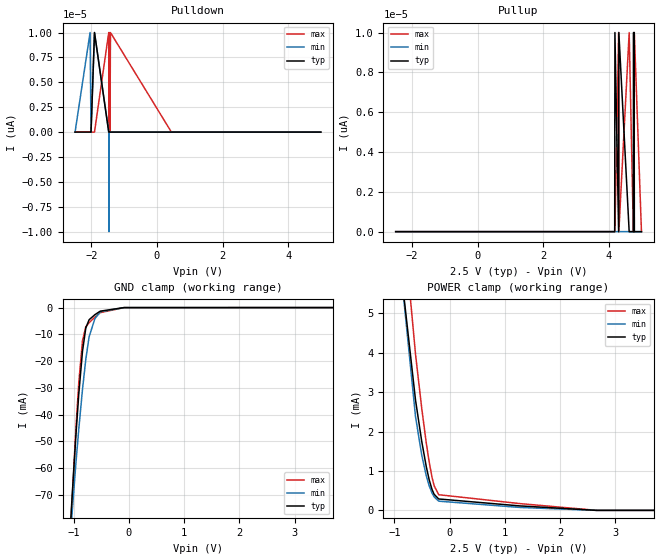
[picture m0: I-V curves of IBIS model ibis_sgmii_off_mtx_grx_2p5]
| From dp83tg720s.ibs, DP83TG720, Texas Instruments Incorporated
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|IBIS Model File - Generated by SIMDE
| http://www.iometh.com/Product/SIMDE
[Model]   ibis_sgmii_off_mtx_grx_2p5
Model_type   Input
Vinl = 0.75
Vinh = 1.75
|   typ   min   max
C_comp   3pF   2.9pF   3.1pF
[Voltage Range]   2.5   2.25   2.75
[Temperature Range]   27   150   -40
[Power Clamp Reference]   2.5   2.25   2.75
[GND Clamp Reference]   0   0   0
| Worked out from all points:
|   GND clamp passes 1 mA (typ) near -0.49 V on its own axis
|   POWER clamp passes 1 mA (typ) near -0.41 V on its own axis
[Pulldown]
|   Voltage   I(typ)   I(min)   I(max)
-2.5V     0A         0A         0A
-2.042V   0A         10pA       0A
-2.013V   0A         0A         0A
-1.907V   10pA       10pA       0A
-1.472V   0A         0A         10pA
-1.465V   0A         -10pA      0A
-1.458V   0A         0A         10pA
-1.435V   0A         0A         0A
-1.42V    0A         0A         10pA
440mV     0A         -11fA      0A
1.355V    0A         10fA       0A
5V        0A         0A         0A
[GND Clamp]
|   Voltage   I(typ)   I(min)   I(max)
-2.5V     -670.7mA   -585.3mA   -740.7mA
-1.097V   -94.99mA   -96.45mA   -99.24mA
-1.038V   -73.2mA    -78.7mA    -74.45mA
-962.5mV  -47.88mA   -58.33mA   -45.54mA
-910mV    -32.33mA   -45.47mA   -28.11mA
-842.5mV  -16.32mA   -30.6mA    -12.35mA
-782.5mV  -7.609mA   -19.31mA   -7.197mA
-722.5mV  -4.546mA   -10.91mA   -5.657mA
-617.5mV  -2.648mA   -4.114mA   -3.575mA
-520mV    -1.342mA   -1.591mA   -1.894mA
-92.5mV   -20.29uA   -15.29uA   -27.56uA
5V        0A         0A         0A
[Pullup]
|   Voltage   I(typ)   I(min)   I(max)
-2.5V     0A         0A         0A
4.183V    0A         0A         0A
4.19V     10pA       0A         0A
4.303V    0A         0A         10pA
4.31V     10pA       0A         0A
4.625V    0A         0A         10pA
4.753V    0A         0A         0A
4.76V     10pA       0A         0A
4.768V    0A         0A         0A
4.775V    10pA       10pA       0A
4.782V    0A         0A         10pA
5V        0A         0A         0A
[POWER Clamp]
|   Voltage   I(typ)   I(min)   I(max)
-2.5V     97.79mA    60.73mA    150.7mA
-1.09V    8.704mA    8.991mA    11.15mA
-617.5mV  2.796mA    2.375mA    3.961mA
-505mV    1.749mA    1.402mA    2.588mA
-422.5mV  1.106mA    876.6uA    1.706mA
-370mV    774.7uA    623uA      1.225mA
-317.5mV  525.8uA    434.9uA    831.7uA
-280mV    406.3uA    340.9uA    622.2uA
-197.5mV  289.2uA    233.4uA    397.1uA
1.272V    113.3uA    74.18uA    172.1uA
2.66V     0A         0A         424.8nA
5V        0A         0A         0A
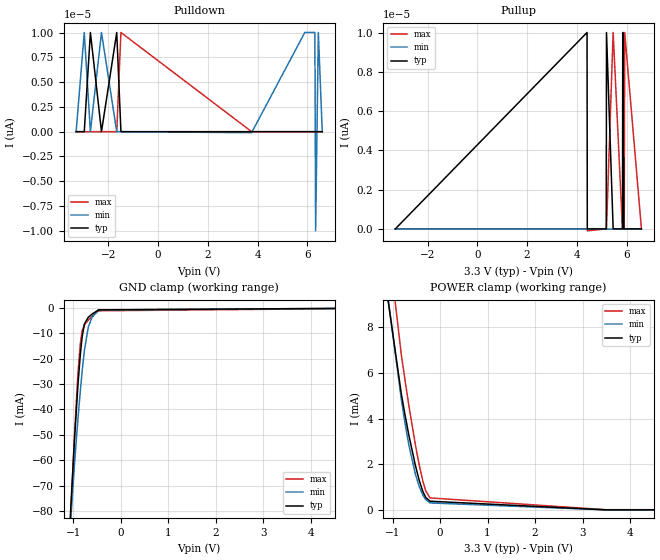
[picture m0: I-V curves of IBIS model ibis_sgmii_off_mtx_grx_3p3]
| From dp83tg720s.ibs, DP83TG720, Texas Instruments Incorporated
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|IBIS Model File - Generated by SIMDE
| http://www.iometh.com/Product/SIMDE
[Model]   ibis_sgmii_off_mtx_grx_3p3
Model_type   Input
Vinl = 0.75
Vinh = 1.75
|   typ   min   max
C_comp   3pF   2.9pF   3.1pF
[Voltage Range]   3.3   2.97   3.63
[Temperature Range]   27   150   -40
[Power Clamp Reference]   3.3   2.97   3.63
[GND Clamp Reference]   0   0   0
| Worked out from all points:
|   GND clamp passes 1 mA (typ) near -0.49 V on its own axis
|   POWER clamp passes 1 mA (typ) near -0.39 V on its own axis
[Pulldown]
|   Voltage   I(typ)   I(min)   I(max)
-3.3V     0A         0A         0A
-2.973V   0A         10pA       0A
-2.726V   10pA       0A         0A
-2.28V    0A         10pA       0A
-1.667V   10pA       0A         0A
-1.498V   0A         0A         10pA
3.759V    0A         -100fA     0A
5.897V    0A         10pA       0A
6.303V    0A         10pA       0A
6.333V    0A         -10pA      0A
6.442V    0A         10pA       0A
6.6V      0A         0A         0A
[GND Clamp]
|   Voltage   I(typ)   I(min)   I(max)
-3.3V     -1.009A    -874.8mA   -1.117A
-1.142V   -111.6mA   -110.2mA   -118.1mA
-1.053V   -78.63mA   -83.09mA   -80.63mA
-973.5mV  -51.4mA    -61.18mA   -49.56mA
-904.2mV  -30.76mA   -44.12mA   -26.41mA
-854.7mV  -18.82mA   -33.14mA   -14.45mA
-815.1mV  -11.54mA   -25.17mA   -9.059mA
-765.6mV  -6.324mA   -16.6mA    -6.663mA
-686.4mV  -3.764mA   -7.644mA   -4.915mA
-607.2mV  -2.497mA   -3.761mA   -3.384mA
-468.6mV  -799.8uA   -856.7uA   -1.172mA
6.6V      0A         0A         0A
[Pullup]
|   Voltage   I(typ)   I(min)   I(max)
-3.3V     0A         0A         0A
4.412V    10pA       0A         0A
4.422V    0A         0A         -100fA
5.184V    0A         0A         0A
5.194V    10pA       0A         0A
5.462V    0A         0A         10pA
5.838V    0A         0A         0A
5.848V    10pA       0A         0A
5.897V    0A         0A         10pA
5.907V    0A         0A         0A
5.927V    0A         0A         10pA
6.6V      0A         0A         0A
[POWER Clamp]
|   Voltage   I(typ)   I(min)   I(max)
-3.3V     250mA      167.9mA    341.1mA
-1.28V    11.92mA    12.22mA    15.12mA
-815.1mV  5.087mA    4.847mA    6.806mA
-735.9mV  4.149mA    3.786mA    5.663mA
-656.7mV  3.278mA    2.846mA    4.581mA
-518.1mV  1.942mA    1.559mA    2.846mA
-438.9mV  1.302mA    1.028mA    1.978mA
-359.7mV  798.2uA    639.6uA    1.247mA
-300.3mV  544.3uA    446.5uA    834.6uA
-211.2mV  378.3uA    302.8uA    522.8uA
3.482V    0A         0A         7.522uA
6.6V      0A         0A         0A
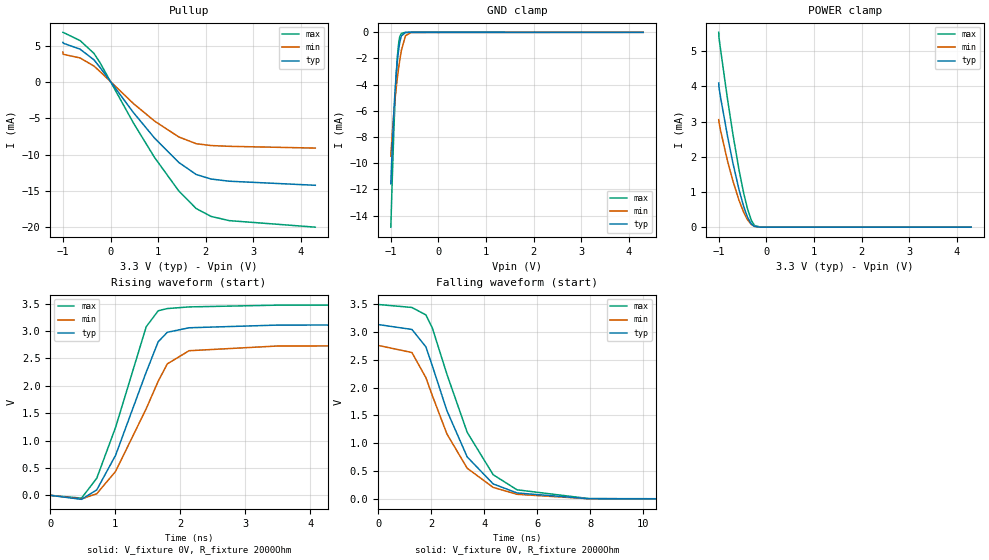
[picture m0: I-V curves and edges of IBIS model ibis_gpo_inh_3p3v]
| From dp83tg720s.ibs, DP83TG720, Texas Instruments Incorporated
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|IBIS Model File - Generated by SIMDE
| http://www.iometh.com/Product/SIMDE
|IBIS Model File - Generated by SIMDE
| http://www.iometh.com/Product/SIMDE
[Model]   ibis_gpo_inh_3p3v
Model_type   Open_source
Polarity   Non-Inverting
Vmeas = 1.65
Vref = 0
Cref = 2pF
Rref = 2000
|   typ   min   max
C_comp   0.8pF   0.79pF   0.81pF
[Voltage Range]   3.3   2.97   3.63
[Temperature Range]   27   150   -40
[Pullup Reference]   3.3   2.97   3.63
[Pulldown Reference]   0   0   0
[Power Clamp Reference]   3.3   2.97   3.63
[GND Clamp Reference]   0   0   0
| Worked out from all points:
|   slope of the pullup table from 0 to 0.495 V, typ, clamps not added: 114 ohm
|   GND clamp passes 1 mA (typ) near -0.82 V on its own axis
|   POWER clamp passes 1 mA (typ) near -0.56 V on its own axis
|   falling waveform, V_fixture 0V, R_fixture 2000Ohm: 20-80 % time 1.58ns typ, 1.59ns min, 1.67ns max; typ from 3.13 V to 0 V
|   rising waveform, V_fixture 0V, R_fixture 2000Ohm: 20-80 % time 587ps typ, 645ps min, 546ps max; typ from 0 V to 3.13 V
[GND Clamp]
|   Voltage   I(typ)   I(min)   I(max)
-1V       -11.57mA   -9.466mA   -14.89mA
-968.2mV  -8.625mA   -7.656mA   -11.06mA
-936.4mV  -6.107mA   -6.139mA   -7.577mA
-915.2mV  -4.706mA   -5.269mA   -5.534mA
-883.4mV  -3.031mA   -4.135mA   -3.038mA
-862.2mV  -2.168mA   -3.47mA    -1.821mA
-830.4mV  -1.188mA   -2.584mA   -674.8uA
-809.2mV  -719.5uA   -2.06mA    -295.6uA
-777.4mV  -278.6uA   -1.375mA   -74.66uA
-692.6mV  -11.02uA   -265.2uA   -2.11uA
-576mV    -157.8nA   -9.603uA   -26.69nA
4.3V      0A         0A         0A
[Pullup]
|   Voltage   I(typ)   I(min)   I(max)
-1V       5.471mA    4.129mA    6.846mA
-994.7mV  5.352mA    3.821mA    6.837mA
-639.6mV  4.527mA    3.317mA    5.715mA
-348.1mV  3.06mA     2.2mA      3.945mA
-220.9mV  2.018mA    1.444mA    2.671mA
478.7mV   -4.192mA   -2.955mA   -5.619mA
923.9mV   -7.722mA   -5.378mA   -10.39mA
1.433V    -11.08mA   -7.567mA   -15.01mA
1.798V    -12.74mA   -8.499mA   -17.43mA
2.111V    -13.37mA   -8.755mA   -18.52mA
2.493V    -13.67mA   -8.862mA   -19.1mA
4.3V      -14.23mA   -9.105mA   -20mA
[POWER Clamp]
|   Voltage   I(typ)   I(min)   I(max)
-1V       4.096mA    3.054mA    5.535mA
-994.7mV  3.975mA    2.987mA    5.386mA
-962.9mV  3.697mA    2.752mA    5.058mA
-814.5mV  2.578mA    1.874mA    3.629mA
-703.2mV  1.827mA    1.318mA    2.647mA
-576mV    1.075mA    770.1uA    1.643mA
-475.3mV  583uA      419.4uA    961.7uA
-395.8mV  282.7uA    210.3uA    518.9uA
-316.3mV  89.85uA    77.06uA    194.8uA
-247.4mV  19.73uA    23.23uA    46.5uA
-125.5mV  495nA      1.536uA    786.1nA
4.3V      0A         0A         0A
[Ramp]
R_load = 2000
|   typ   min   max
dV/dt_r   1.87559/5.86864e-10   1.65178/6.44511e-10   2.09114/5.45749e-10
dV/dt_f   1.87559/1.57807e-09   1.65179/1.58307e-09   2.09114/1.66608e-09
[Falling Waveform]
V_fixture = 0V
V_fixture_min = 0V
V_fixture_max = 0V
R_fixture = 2000Ohm
C_fixture = 0F
|   Time   V(typ)   V(min)   V(max)
0s        3.126V     2.753V     3.485V
1.272ns   3.039V     2.626V     3.432V
1.801ns   2.726V     2.176V     3.298V
2.042ns   2.388V     1.856V     3.067V
2.594ns   1.585V     1.169V     2.236V
3.358ns   758.6mV    556.4mV    1.199V
4.338ns   276.1mV    213.3mV    440.4mV
5.238ns   114mV      89.83mV    170.5mV
7.938ns   11.12mV    10.82mV    13.8mV
20ns      12.49uV    137.9uV    9.732uV
[Rising Waveform]
V_fixture = 0V
V_fixture_min = 0V
V_fixture_max = 0V
R_fixture = 2000Ohm
C_fixture = 0F
|   Time   V(typ)   V(min)   V(max)
0s        12.47uV    137.9uV    9.734uV
481.2ps   -72.89mV   -65.24mV   -50.79mV
715.2ps   99.66mV    29.02mV    312.8mV
1.005ns   731.8mV    437.8mV    1.242V
1.476ns   2.25V      1.582V     3.079V
1.661ns   2.805V     2.085V     3.371V
1.801ns   2.978V     2.401V     3.411V
2.136ns   3.06V      2.641V     3.441V
3.494ns   3.109V     2.727V     3.473V
20ns      3.126V     2.753V     3.485V
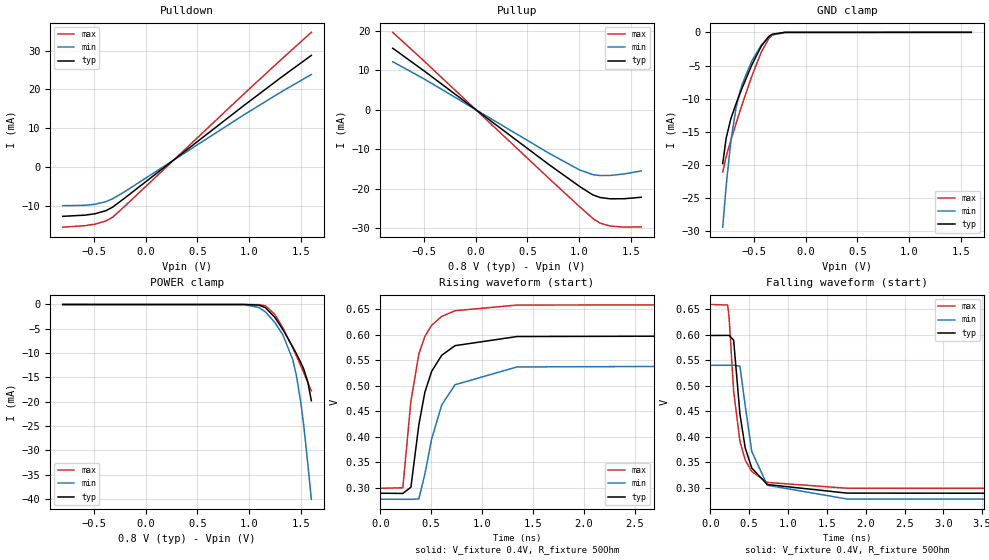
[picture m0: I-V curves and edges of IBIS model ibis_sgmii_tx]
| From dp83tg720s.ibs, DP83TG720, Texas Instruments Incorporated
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|   ibis_sgmii_tx
[Model]   ibis_sgmii_tx
Model_type   Output
Polarity   Non-Inverting
Vmeas = 0.4
Vref = 0
Cref = 2pF
Rref = 50
|   typ   min   max
C_comp   3.9pF   3.8pF   4pF
[Voltage Range]   0.8   0.75   0.85
[Temperature Range]   27   150   -40
[Pullup Reference]   0.8   0.75   0.85
[Pulldown Reference]   -0   0   -0
[Power Clamp Reference]   0.8   0.75   0.85
[GND Clamp Reference]   0   0   0
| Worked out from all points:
|   slope of the pulldown table from 0 to 0.12 V, typ, clamps not added: 47.9 ohm
|   slope of the pullup table from 0 to 0.12 V, typ, clamps not added: 50.6 ohm
|   GND clamp passes 1 mA (typ) near -0.38 V on its own axis
|   falling waveform, V_fixture 0.4V, R_fixture 50Ohm: 20-80 % time 170ps typ, 189ps min, 154ps max; typ from 0.599 V to 0.289 V
|   rising waveform, V_fixture 0.4V, R_fixture 50Ohm: 20-80 % time 192ps typ, 232ps min, 160ps max; typ from 0.289 V to 0.599 V
[Pulldown]
|   Voltage   I(typ)   I(min)   I(max)
-800mV    -12.73mA   -9.979mA   -15.52mA
-588.8mV  -12.43mA   -9.899mA   -15.15mA
-490.4mV  -12.08mA   -9.622mA   -14.76mA
-382.4mV  -11.28mA   -8.933mA   -13.92mA
-317.6mV  -10.35mA   -8.201mA   -12.94mA
-200mV    -7.991mA   -6.343mA   -10.1mA
947.2mV   15.8mA     13.4mA     18.77mA
1.305V    23.01mA    19.28mA    27.6mA
1.6V      28.75mA    23.83mA    34.7mA
[GND Clamp]
|   Voltage   I(typ)   I(min)   I(max)
-800mV    -19.78mA   -29.36mA   -21.03mA
-766.4mV  -15.92mA   -23.1mA    -18.68mA
-720.8mV  -12.99mA   -16.31mA   -16.23mA
-670.4mV  -10.73mA   -11.33mA   -13.7mA
-636.8mV  -9.36mA    -9.124mA   -12.05mA
-610.4mV  -8.315mA   -7.755mA   -10.78mA
-519.2mV  -4.925mA   -4.316mA   -6.607mA
-428mV    -2.094mA   -1.943mA   -3.003mA
-356mV    -639.5uA   -743.6uA   -969.3uA
-320mV    -270.7uA   -396.8uA   -392.4uA
-200mV    -5.953uA   -28.08uA   -3.461uA
1.6V      -23.79nA   -379.3nA   -7.829nA
[Pullup]
|   Voltage   I(typ)   I(min)   I(max)
-800mV    15.64mA    12.22mA    19.67mA
-490.4mV  9.761mA    7.753mA    12.22mA
707.2mV   -13.85mA   -10.97mA   -17.36mA
1.002V    -19.38mA   -15.2mA    -24.5mA
1.132V    -21.56mA   -16.42mA   -27.53mA
1.202V    -22.21mA   -16.65mA   -28.72mA
1.298V    -22.55mA   -16.64mA   -29.45mA
1.437V    -22.53mA   -16.24mA   -29.74mA
1.6V      -22.15mA   -15.48mA   -29.66mA
[POWER Clamp]
|   Voltage   I(typ)   I(min)   I(max)
-800mV    -34.89nA   -394.9nA   -18.53nA
952mV     -1.18uA    -29.48uA   -78.57nA
1.096V    -138uA     -631uA     -25.64uA
1.156V    -639.6uA   -1.506mA   -254.5uA
1.247V    -2.619mA   -3.666mA   -2.012mA
1.326V    -5.178mA   -6.294mA   -4.818mA
1.42V     -8.692mA   -11.3mA    -8.884mA
1.456V    -10.14mA   -14.59mA   -10.57mA
1.499V    -11.97mA   -20.29mA   -12.65mA
1.526V    -13.23mA   -24.72mA   -13.96mA
1.566V    -15.92mA   -32.71mA   -16.01mA
1.6V      -19.78mA   -40.07mA   -17.76mA
[Ramp]
R_load = 50
|   typ   min   max
dV/dt_r   0.185838/1.91648e-10   0.15777/2.3147e-10   0.216499/1.605e-10
dV/dt_f   0.185838/1.70072e-10   0.15777/1.88647e-10   0.216499/1.53952e-10
[Falling Waveform]
V_fixture = 0.4V
V_fixture_min = 0.375V
V_fixture_max = 0.425V
R_fixture = 50Ohm
C_fixture = 0F
|   Time   V(typ)   V(min)   V(max)
0s        598.8mV    540.3mV    659.6mV
223.8ps   599mV      540.4mV    658.6mV
242.9ps   599mV      540.4mV    632.4mV
300.6ps   589.7mV    540.5mV    489.2mV
382.2ps   443.9mV    538.5mV    391mV
449.9ps   378mV      460.6mV    354.4mV
534.2ps   338.7mV    371.2mV    332mV
734ps     306.4mV    305.1mV    310.6mV
1.76ns    289.6mV    278mV      299.2mV
6ns       289.1mV    277.4mV    298.8mV
[Rising Waveform]
V_fixture = 0.4V
V_fixture_min = 0.375V
V_fixture_max = 0.425V
R_fixture = 50Ohm
C_fixture = 0F
|   Time   V(typ)   V(min)   V(max)
0s        289.1mV    277.4mV    298.8mV
221.2ps   288.7mV    277.1mV    299.8mV
300.6ps   300.9mV    277.1mV    469.9mV
378.5ps   423.4mV    278mV      562.6mV
437.8ps   487.5mV    326.7mV    597.2mV
504ps     528.3mV    395.4mV    618.8mV
603ps     559.9mV    462.4mV    636.2mV
734ps     578.8mV    502.1mV    647.4mV
1.342ns   596.7mV    537mV      658.5mV
6ns       598.8mV    540.3mV    659.6mV
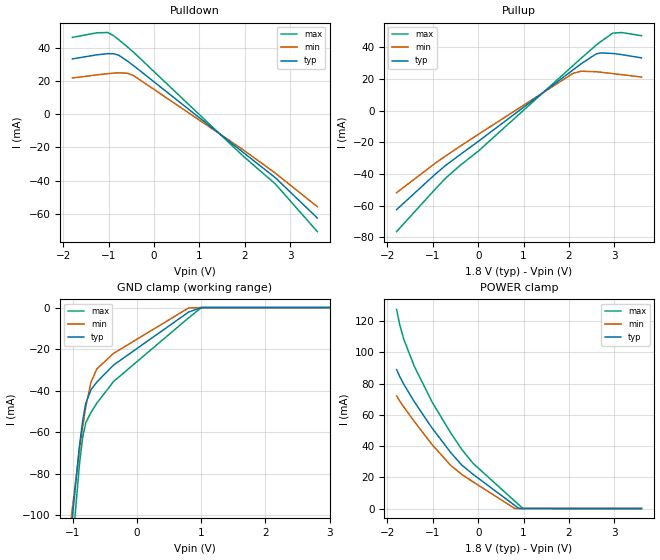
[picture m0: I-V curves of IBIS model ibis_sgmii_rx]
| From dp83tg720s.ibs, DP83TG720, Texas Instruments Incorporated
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|   ibis_sgmii_rx
[Model]   ibis_sgmii_rx
Model_type   Input
Vinl = 0.54
Vinh = 1.26
|   typ   min   max
C_comp   5pF   5pF   5pF
[Voltage Range]   1.8   1.62   1.98
[Temperature Range]   27   150   -40
[Power Clamp Reference]   1.8   1.62   1.98
[GND Clamp Reference]   0   0   0
[Pulldown]
|   Voltage   I(typ)   I(min)   I(max)
-1.8V     33.35mA    21.85mA    46.29mA
-1.26V    35.79mA    23.7mA     49.07mA
-1.017V   36.49mA    24.46mA    49.21mA
-882mV    36.41mA    24.8mA     47.13mA
-779.4mV  35.56mA    24.96mA    44.89mA
-585mV    32.01mA    24.67mA    40.55mA
-444.6mV  29.1mA     23.16mA    37.17mA
1.964V    -22.95mA   -21.38mA   -25.19mA
2.671V    -38.15mA   -35.41mA   -41.88mA
3.6V      -62.5mA    -55.66mA   -70.69mA
[GND Clamp]
|   Voltage   I(typ)   I(min)   I(max)
-1.8V     -414.3mA   -360mA     -464.4mA
-1.071V   -122.6mA   -114mA     -139.6mA
-1.028V   -107.1mA   -101.5mA   -122.1mA
-898.2mV  -66.3mA    -68.27mA   -75.16mA
-849.6mV  -54.67mA   -57.58mA   -62.58mA
-801mV    -46.09mA   -48.01mA   -55.55mA
-720mV    -39.57mA   -35.98mA   -50.57mA
-628.2mV  -35.91mA   -29.56mA   -46.06mA
-369mV    -27.72mA   -22.1mA    -35.66mA
802.8mV   -2.164mA   -184.8uA   -4.932mA
1.003V    0A         0A         0A
3.6V      0A         0A         0A
[Pullup]
|   Voltage   I(typ)   I(min)   I(max)
-1.8V     -62.5mA    -51.8mA    -76.37mA
-936mV    -39.81mA   -32.92mA   -49.18mA
-709.2mV  -34.37mA   -28.44mA   -42.37mA
-385.2mV  -27.48mA   -22.19mA   -34.24mA
9mV       -19.24mA   -14.83mA   -25.37mA
2.093V    25.76mA    23.6mA     28.53mA
2.272V    29.67mA    24.91mA    33.16mA
2.601V    35.83mA    24.56mA    41.38mA
2.704V    36.48mA    24.27mA    43.67mA
2.968V    36.11mA    23.4mA     48.97mA
3.163V    35.37mA    22.73mA    49.32mA
3.6V      33.35mA    21.27mA    47.32mA
[POWER Clamp]
|   Voltage   I(typ)   I(min)   I(max)
-1.8V     88.96mA    72.09mA    127.5mA
-1.73V    84.54mA    68.84mA    117.7mA
-1.643V   79.67mA    65.12mA    108.6mA
-1.411V   68.51mA    55.85mA    91.18mA
-1.022V   51.71mA    41.11mA    68.46mA
-612mV    36.05mA    27.8mA     48.69mA
-358.2mV  27.71mA    21.73mA    37.68mA
-109.8mV  21.81mA    17.01mA    28.81mA
802.8mV   2.05mA     82.59uA    4.801mA
894.6mV   60.37uA    0A         2.416mA
986.4mV   0A         0A         29.51uA
3.6V      0A         0A         0A
